VERSION 5.8 ;
BUSBITCHARS "[]" ;
DIVIDERCHAR "/" ;
UNITS
    DATABASE MICRONS 1000 ;
END UNITS

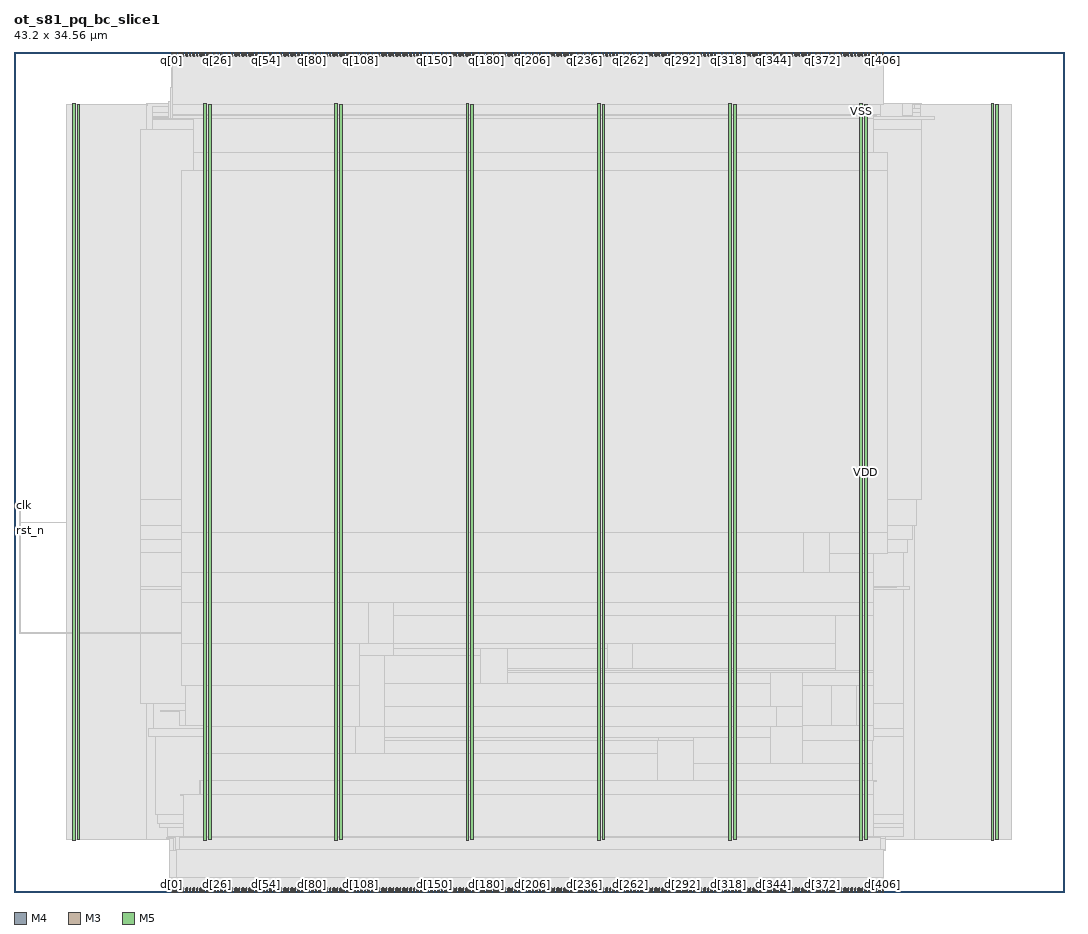
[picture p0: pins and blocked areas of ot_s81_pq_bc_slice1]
MACRO ot_s81_pq_bc_slice1
  FOREIGN ot_s81_pq_bc_slice1 0 0 ;
  CLASS BLOCK ;
  SIZE 43.2 BY 34.56 ;
  PIN clk
    DIRECTION INPUT ;
    USE SIGNAL ;
    PORT
      LAYER M4 ;
        RECT  0 15.888 0.192 15.912 ;
    END
    PORT
      LAYER M4 ;
        RECT  0.156 15.888 0.275 15.912 ;
    END
  END clk
  PIN d[0]
    DIRECTION INPUT ;
    USE SIGNAL ;
    PORT
      LAYER M3 ;
        RECT  6.48 0 6.498 0.144 ;
    END
  END d[0]
  PIN d[100]
    DIRECTION INPUT ;
    USE SIGNAL ;
    PORT
      LAYER M3 ;
        RECT  13.68 0 13.698 0.144 ;
    END
  END d[100]
  PIN d[101]
    DIRECTION INPUT ;
    USE SIGNAL ;
    PORT
      LAYER M5 ;
        RECT  13.728 0 13.752 0.192 ;
    END
  END d[101]
  PIN d[102]
    DIRECTION INPUT ;
    USE SIGNAL ;
    PORT
      LAYER M3 ;
        RECT  13.824 0 13.842 0.144 ;
    END
  END d[102]
  PIN d[103]
    DIRECTION INPUT ;
    USE SIGNAL ;
    PORT
      LAYER M5 ;
        RECT  13.872 0 13.896 0.192 ;
    END
  END d[103]
  PIN d[104]
    DIRECTION INPUT ;
    USE SIGNAL ;
    PORT
      LAYER M3 ;
        RECT  13.968 0 13.986 0.144 ;
    END
  END d[104]
  PIN d[105]
    DIRECTION INPUT ;
    USE SIGNAL ;
    PORT
      LAYER M5 ;
        RECT  14.016 0 14.04 0.192 ;
    END
  END d[105]
  PIN d[106]
    DIRECTION INPUT ;
    USE SIGNAL ;
    PORT
      LAYER M3 ;
        RECT  14.112 0 14.13 0.144 ;
    END
  END d[106]
  PIN d[107]
    DIRECTION INPUT ;
    USE SIGNAL ;
    PORT
      LAYER M5 ;
        RECT  14.16 0 14.184 0.192 ;
    END
  END d[107]
  PIN d[108]
    DIRECTION INPUT ;
    USE SIGNAL ;
    PORT
      LAYER M3 ;
        RECT  14.256 0 14.274 0.144 ;
    END
  END d[108]
  PIN d[109]
    DIRECTION INPUT ;
    USE SIGNAL ;
    PORT
      LAYER M5 ;
        RECT  14.304 0 14.328 0.192 ;
    END
  END d[109]
  PIN d[10]
    DIRECTION INPUT ;
    USE SIGNAL ;
    PORT
      LAYER M3 ;
        RECT  7.2 0 7.218 0.144 ;
    END
  END d[10]
  PIN d[110]
    DIRECTION INPUT ;
    USE SIGNAL ;
    PORT
      LAYER M3 ;
        RECT  14.4 0 14.418 0.144 ;
    END
  END d[110]
  PIN d[111]
    DIRECTION INPUT ;
    USE SIGNAL ;
    PORT
      LAYER M5 ;
        RECT  14.448 0 14.472 0.192 ;
    END
  END d[111]
  PIN d[112]
    DIRECTION INPUT ;
    USE SIGNAL ;
    PORT
      LAYER M3 ;
        RECT  14.544 0 14.562 0.144 ;
    END
  END d[112]
  PIN d[113]
    DIRECTION INPUT ;
    USE SIGNAL ;
    PORT
      LAYER M5 ;
        RECT  14.592 0 14.616 0.192 ;
    END
  END d[113]
  PIN d[114]
    DIRECTION INPUT ;
    USE SIGNAL ;
    PORT
      LAYER M3 ;
        RECT  14.688 0 14.706 0.144 ;
    END
  END d[114]
  PIN d[115]
    DIRECTION INPUT ;
    USE SIGNAL ;
    PORT
      LAYER M5 ;
        RECT  14.736 0 14.76 0.192 ;
    END
  END d[115]
  PIN d[116]
    DIRECTION INPUT ;
    USE SIGNAL ;
    PORT
      LAYER M3 ;
        RECT  14.832 0 14.85 0.144 ;
    END
  END d[116]
  PIN d[117]
    DIRECTION INPUT ;
    USE SIGNAL ;
    PORT
      LAYER M5 ;
        RECT  14.88 0 14.904 0.192 ;
    END
  END d[117]
  PIN d[118]
    DIRECTION INPUT ;
    USE SIGNAL ;
    PORT
      LAYER M3 ;
        RECT  14.976 0 14.994 0.144 ;
    END
  END d[118]
  PIN d[119]
    DIRECTION INPUT ;
    USE SIGNAL ;
    PORT
      LAYER M5 ;
        RECT  15.024 0 15.048 0.192 ;
    END
  END d[119]
  PIN d[11]
    DIRECTION INPUT ;
    USE SIGNAL ;
    PORT
      LAYER M5 ;
        RECT  7.248 0 7.272 0.192 ;
    END
  END d[11]
  PIN d[120]
    DIRECTION INPUT ;
    USE SIGNAL ;
    PORT
      LAYER M3 ;
        RECT  15.12 0 15.138 0.144 ;
    END
  END d[120]
  PIN d[121]
    DIRECTION INPUT ;
    USE SIGNAL ;
    PORT
      LAYER M5 ;
        RECT  15.168 0 15.192 0.192 ;
    END
  END d[121]
  PIN d[122]
    DIRECTION INPUT ;
    USE SIGNAL ;
    PORT
      LAYER M3 ;
        RECT  15.264 0 15.282 0.144 ;
    END
  END d[122]
  PIN d[123]
    DIRECTION INPUT ;
    USE SIGNAL ;
    PORT
      LAYER M5 ;
        RECT  15.312 0 15.336 0.192 ;
    END
  END d[123]
  PIN d[124]
    DIRECTION INPUT ;
    USE SIGNAL ;
    PORT
      LAYER M3 ;
        RECT  15.408 0 15.426 0.144 ;
    END
  END d[124]
  PIN d[125]
    DIRECTION INPUT ;
    USE SIGNAL ;
    PORT
      LAYER M5 ;
        RECT  15.456 0 15.48 0.192 ;
    END
  END d[125]
  PIN d[126]
    DIRECTION INPUT ;
    USE SIGNAL ;
    PORT
      LAYER M3 ;
        RECT  15.552 0 15.57 0.144 ;
    END
  END d[126]
  PIN d[127]
    DIRECTION INPUT ;
    USE SIGNAL ;
    PORT
      LAYER M5 ;
        RECT  15.6 0 15.624 0.192 ;
    END
  END d[127]
  PIN d[128]
    DIRECTION INPUT ;
    USE SIGNAL ;
    PORT
      LAYER M3 ;
        RECT  15.696 0 15.714 0.144 ;
    END
  END d[128]
  PIN d[129]
    DIRECTION INPUT ;
    USE SIGNAL ;
    PORT
      LAYER M5 ;
        RECT  15.744 0 15.768 0.192 ;
    END
  END d[129]
  PIN d[12]
    DIRECTION INPUT ;
    USE SIGNAL ;
    PORT
      LAYER M3 ;
        RECT  7.344 0 7.362 0.144 ;
    END
  END d[12]
  PIN d[130]
    DIRECTION INPUT ;
    USE SIGNAL ;
    PORT
      LAYER M3 ;
        RECT  15.84 0 15.858 0.144 ;
    END
  END d[130]
  PIN d[131]
    DIRECTION INPUT ;
    USE SIGNAL ;
    PORT
      LAYER M5 ;
        RECT  15.888 0 15.912 0.192 ;
    END
  END d[131]
  PIN d[132]
    DIRECTION INPUT ;
    USE SIGNAL ;
    PORT
      LAYER M3 ;
        RECT  15.984 0 16.002 0.144 ;
    END
  END d[132]
  PIN d[133]
    DIRECTION INPUT ;
    USE SIGNAL ;
    PORT
      LAYER M5 ;
        RECT  16.032 0 16.056 0.192 ;
    END
  END d[133]
  PIN d[134]
    DIRECTION INPUT ;
    USE SIGNAL ;
    PORT
      LAYER M3 ;
        RECT  16.128 0 16.146 0.144 ;
    END
  END d[134]
  PIN d[135]
    DIRECTION INPUT ;
    USE SIGNAL ;
    PORT
      LAYER M5 ;
        RECT  16.176 0 16.2 0.192 ;
    END
  END d[135]
  PIN d[136]
    DIRECTION INPUT ;
    USE SIGNAL ;
    PORT
      LAYER M3 ;
        RECT  16.272 0 16.29 0.144 ;
    END
  END d[136]
  PIN d[137]
    DIRECTION INPUT ;
    USE SIGNAL ;
    PORT
      LAYER M5 ;
        RECT  16.32 0 16.344 0.192 ;
    END
  END d[137]
  PIN d[138]
    DIRECTION INPUT ;
    USE SIGNAL ;
    PORT
      LAYER M3 ;
        RECT  16.416 0 16.434 0.144 ;
    END
  END d[138]
  PIN d[139]
    DIRECTION INPUT ;
    USE SIGNAL ;
    PORT
      LAYER M5 ;
        RECT  16.464 0 16.488 0.192 ;
    END
  END d[139]
  PIN d[13]
    DIRECTION INPUT ;
    USE SIGNAL ;
    PORT
      LAYER M5 ;
        RECT  7.392 0 7.416 0.192 ;
    END
  END d[13]
  PIN d[140]
    DIRECTION INPUT ;
    USE SIGNAL ;
    PORT
      LAYER M3 ;
        RECT  16.56 0 16.578 0.144 ;
    END
  END d[140]
  PIN d[141]
    DIRECTION INPUT ;
    USE SIGNAL ;
    PORT
      LAYER M5 ;
        RECT  16.608 0 16.632 0.192 ;
    END
  END d[141]
  PIN d[142]
    DIRECTION INPUT ;
    USE SIGNAL ;
    PORT
      LAYER M3 ;
        RECT  16.704 0 16.722 0.144 ;
    END
  END d[142]
  PIN d[143]
    DIRECTION INPUT ;
    USE SIGNAL ;
    PORT
      LAYER M5 ;
        RECT  16.752 0 16.776 0.192 ;
    END
  END d[143]
  PIN d[144]
    DIRECTION INPUT ;
    USE SIGNAL ;
    PORT
      LAYER M3 ;
        RECT  16.848 0 16.866 0.144 ;
    END
  END d[144]
  PIN d[145]
    DIRECTION INPUT ;
    USE SIGNAL ;
    PORT
      LAYER M5 ;
        RECT  16.896 0 16.92 0.192 ;
    END
  END d[145]
  PIN d[146]
    DIRECTION INPUT ;
    USE SIGNAL ;
    PORT
      LAYER M3 ;
        RECT  16.992 0 17.01 0.144 ;
    END
  END d[146]
  PIN d[147]
    DIRECTION INPUT ;
    USE SIGNAL ;
    PORT
      LAYER M5 ;
        RECT  17.04 0 17.064 0.192 ;
    END
  END d[147]
  PIN d[148]
    DIRECTION INPUT ;
    USE SIGNAL ;
    PORT
      LAYER M3 ;
        RECT  17.136 0 17.154 0.144 ;
    END
  END d[148]
  PIN d[149]
    DIRECTION INPUT ;
    USE SIGNAL ;
    PORT
      LAYER M5 ;
        RECT  17.184 0 17.208 0.192 ;
    END
  END d[149]
  PIN d[14]
    DIRECTION INPUT ;
    USE SIGNAL ;
    PORT
      LAYER M3 ;
        RECT  7.488 0 7.506 0.144 ;
    END
  END d[14]
  PIN d[150]
    DIRECTION INPUT ;
    USE SIGNAL ;
    PORT
      LAYER M3 ;
        RECT  17.28 0 17.298 0.144 ;
    END
  END d[150]
  PIN d[151]
    DIRECTION INPUT ;
    USE SIGNAL ;
    PORT
      LAYER M5 ;
        RECT  17.328 0 17.352 0.192 ;
    END
  END d[151]
  PIN d[152]
    DIRECTION INPUT ;
    USE SIGNAL ;
    PORT
      LAYER M3 ;
        RECT  17.424 0 17.442 0.144 ;
    END
  END d[152]
  PIN d[153]
    DIRECTION INPUT ;
    USE SIGNAL ;
    PORT
      LAYER M5 ;
        RECT  17.472 0 17.496 0.192 ;
    END
  END d[153]
  PIN d[154]
    DIRECTION INPUT ;
    USE SIGNAL ;
    PORT
      LAYER M3 ;
        RECT  17.568 0 17.586 0.144 ;
    END
  END d[154]
  PIN d[155]
    DIRECTION INPUT ;
    USE SIGNAL ;
    PORT
      LAYER M5 ;
        RECT  17.616 0 17.64 0.192 ;
    END
  END d[155]
  PIN d[156]
    DIRECTION INPUT ;
    USE SIGNAL ;
    PORT
      LAYER M3 ;
        RECT  17.712 0 17.73 0.144 ;
    END
  END d[156]
  PIN d[157]
    DIRECTION INPUT ;
    USE SIGNAL ;
    PORT
      LAYER M5 ;
        RECT  17.76 0 17.784 0.192 ;
    END
  END d[157]
  PIN d[158]
    DIRECTION INPUT ;
    USE SIGNAL ;
    PORT
      LAYER M3 ;
        RECT  17.856 0 17.874 0.144 ;
    END
  END d[158]
  PIN d[159]
    DIRECTION INPUT ;
    USE SIGNAL ;
    PORT
      LAYER M5 ;
        RECT  17.904 0 17.928 0.192 ;
    END
  END d[159]
  PIN d[15]
    DIRECTION INPUT ;
    USE SIGNAL ;
    PORT
      LAYER M5 ;
        RECT  7.536 0 7.56 0.192 ;
    END
  END d[15]
  PIN d[160]
    DIRECTION INPUT ;
    USE SIGNAL ;
    PORT
      LAYER M3 ;
        RECT  18 0 18.018 0.144 ;
    END
  END d[160]
  PIN d[161]
    DIRECTION INPUT ;
    USE SIGNAL ;
    PORT
      LAYER M5 ;
        RECT  18.048 0 18.072 0.192 ;
    END
  END d[161]
  PIN d[162]
    DIRECTION INPUT ;
    USE SIGNAL ;
    PORT
      LAYER M3 ;
        RECT  18.144 0 18.162 0.144 ;
    END
  END d[162]
  PIN d[163]
    DIRECTION INPUT ;
    USE SIGNAL ;
    PORT
      LAYER M5 ;
        RECT  18.192 0 18.216 0.192 ;
    END
  END d[163]
  PIN d[164]
    DIRECTION INPUT ;
    USE SIGNAL ;
    PORT
      LAYER M3 ;
        RECT  18.288 0 18.306 0.144 ;
    END
  END d[164]
  PIN d[165]
    DIRECTION INPUT ;
    USE SIGNAL ;
    PORT
      LAYER M5 ;
        RECT  18.336 0 18.36 0.192 ;
    END
  END d[165]
  PIN d[166]
    DIRECTION INPUT ;
    USE SIGNAL ;
    PORT
      LAYER M3 ;
        RECT  18.432 0 18.45 0.144 ;
    END
  END d[166]
  PIN d[167]
    DIRECTION INPUT ;
    USE SIGNAL ;
    PORT
      LAYER M5 ;
        RECT  18.48 0 18.504 0.192 ;
    END
  END d[167]
  PIN d[168]
    DIRECTION INPUT ;
    USE SIGNAL ;
    PORT
      LAYER M3 ;
        RECT  18.576 0 18.594 0.144 ;
    END
  END d[168]
  PIN d[169]
    DIRECTION INPUT ;
    USE SIGNAL ;
    PORT
      LAYER M5 ;
        RECT  18.624 0 18.648 0.192 ;
    END
  END d[169]
  PIN d[16]
    DIRECTION INPUT ;
    USE SIGNAL ;
    PORT
      LAYER M3 ;
        RECT  7.632 0 7.65 0.144 ;
    END
  END d[16]
  PIN d[170]
    DIRECTION INPUT ;
    USE SIGNAL ;
    PORT
      LAYER M3 ;
        RECT  18.72 0 18.738 0.144 ;
    END
  END d[170]
  PIN d[171]
    DIRECTION INPUT ;
    USE SIGNAL ;
    PORT
      LAYER M5 ;
        RECT  18.768 0 18.792 0.192 ;
    END
  END d[171]
  PIN d[172]
    DIRECTION INPUT ;
    USE SIGNAL ;
    PORT
      LAYER M3 ;
        RECT  18.864 0 18.882 0.144 ;
    END
  END d[172]
  PIN d[173]
    DIRECTION INPUT ;
    USE SIGNAL ;
    PORT
      LAYER M5 ;
        RECT  18.912 0 18.936 0.192 ;
    END
  END d[173]
  PIN d[174]
    DIRECTION INPUT ;
    USE SIGNAL ;
    PORT
      LAYER M3 ;
        RECT  19.008 0 19.026 0.144 ;
    END
  END d[174]
  PIN d[175]
    DIRECTION INPUT ;
    USE SIGNAL ;
    PORT
      LAYER M5 ;
        RECT  19.056 0 19.08 0.192 ;
    END
  END d[175]
  PIN d[176]
    DIRECTION INPUT ;
    USE SIGNAL ;
    PORT
      LAYER M3 ;
        RECT  19.152 0 19.17 0.144 ;
    END
  END d[176]
  PIN d[177]
    DIRECTION INPUT ;
    USE SIGNAL ;
    PORT
      LAYER M5 ;
        RECT  19.2 0 19.224 0.192 ;
    END
  END d[177]
  PIN d[178]
    DIRECTION INPUT ;
    USE SIGNAL ;
    PORT
      LAYER M3 ;
        RECT  19.296 0 19.314 0.144 ;
    END
  END d[178]
  PIN d[179]
    DIRECTION INPUT ;
    USE SIGNAL ;
    PORT
      LAYER M5 ;
        RECT  19.344 0 19.368 0.192 ;
    END
  END d[179]
  PIN d[17]
    DIRECTION INPUT ;
    USE SIGNAL ;
    PORT
      LAYER M5 ;
        RECT  7.68 0 7.704 0.192 ;
    END
  END d[17]
  PIN d[180]
    DIRECTION INPUT ;
    USE SIGNAL ;
    PORT
      LAYER M3 ;
        RECT  19.44 0 19.458 0.144 ;
    END
  END d[180]
  PIN d[181]
    DIRECTION INPUT ;
    USE SIGNAL ;
    PORT
      LAYER M5 ;
        RECT  19.488 0 19.512 0.192 ;
    END
  END d[181]
  PIN d[182]
    DIRECTION INPUT ;
    USE SIGNAL ;
    PORT
      LAYER M3 ;
        RECT  19.584 0 19.602 0.144 ;
    END
  END d[182]
  PIN d[183]
    DIRECTION INPUT ;
    USE SIGNAL ;
    PORT
      LAYER M5 ;
        RECT  19.632 0 19.656 0.192 ;
    END
  END d[183]
  PIN d[184]
    DIRECTION INPUT ;
    USE SIGNAL ;
    PORT
      LAYER M3 ;
        RECT  19.728 0 19.746 0.144 ;
    END
  END d[184]
  PIN d[185]
    DIRECTION INPUT ;
    USE SIGNAL ;
    PORT
      LAYER M5 ;
        RECT  19.776 0 19.8 0.192 ;
    END
  END d[185]
  PIN d[186]
    DIRECTION INPUT ;
    USE SIGNAL ;
    PORT
      LAYER M3 ;
        RECT  19.872 0 19.89 0.144 ;
    END
  END d[186]
  PIN d[187]
    DIRECTION INPUT ;
    USE SIGNAL ;
    PORT
      LAYER M5 ;
        RECT  19.92 0 19.944 0.192 ;
    END
  END d[187]
  PIN d[188]
    DIRECTION INPUT ;
    USE SIGNAL ;
    PORT
      LAYER M3 ;
        RECT  20.016 0 20.034 0.144 ;
    END
  END d[188]
  PIN d[189]
    DIRECTION INPUT ;
    USE SIGNAL ;
    PORT
      LAYER M5 ;
        RECT  20.064 0 20.088 0.192 ;
    END
  END d[189]
  PIN d[18]
    DIRECTION INPUT ;
    USE SIGNAL ;
    PORT
      LAYER M3 ;
        RECT  7.776 0 7.794 0.144 ;
    END
  END d[18]
  PIN d[190]
    DIRECTION INPUT ;
    USE SIGNAL ;
    PORT
      LAYER M3 ;
        RECT  20.16 0 20.178 0.144 ;
    END
  END d[190]
  PIN d[191]
    DIRECTION INPUT ;
    USE SIGNAL ;
    PORT
      LAYER M5 ;
        RECT  20.208 0 20.232 0.192 ;
    END
  END d[191]
  PIN d[192]
    DIRECTION INPUT ;
    USE SIGNAL ;
    PORT
      LAYER M3 ;
        RECT  20.304 0 20.322 0.144 ;
    END
  END d[192]
  PIN d[193]
    DIRECTION INPUT ;
    USE SIGNAL ;
    PORT
      LAYER M5 ;
        RECT  20.352 0 20.376 0.192 ;
    END
  END d[193]
  PIN d[194]
    DIRECTION INPUT ;
    USE SIGNAL ;
    PORT
      LAYER M3 ;
        RECT  20.448 0 20.466 0.144 ;
    END
  END d[194]
  PIN d[195]
    DIRECTION INPUT ;
    USE SIGNAL ;
    PORT
      LAYER M5 ;
        RECT  20.496 0 20.52 0.192 ;
    END
  END d[195]
  PIN d[196]
    DIRECTION INPUT ;
    USE SIGNAL ;
    PORT
      LAYER M3 ;
        RECT  20.592 0 20.61 0.144 ;
    END
  END d[196]
  PIN d[197]
    DIRECTION INPUT ;
    USE SIGNAL ;
    PORT
      LAYER M5 ;
        RECT  20.64 0 20.664 0.192 ;
    END
  END d[197]
  PIN d[198]
    DIRECTION INPUT ;
    USE SIGNAL ;
    PORT
      LAYER M3 ;
        RECT  20.736 0 20.754 0.144 ;
    END
  END d[198]
  PIN d[199]
    DIRECTION INPUT ;
    USE SIGNAL ;
    PORT
      LAYER M5 ;
        RECT  20.784 0 20.808 0.192 ;
    END
  END d[199]
  PIN d[19]
    DIRECTION INPUT ;
    USE SIGNAL ;
    PORT
      LAYER M5 ;
        RECT  7.824 0 7.848 0.192 ;
    END
  END d[19]
  PIN d[1]
    DIRECTION INPUT ;
    USE SIGNAL ;
    PORT
      LAYER M5 ;
        RECT  6.528 0 6.552 0.192 ;
    END
  END d[1]
  PIN d[200]
    DIRECTION INPUT ;
    USE SIGNAL ;
    PORT
      LAYER M3 ;
        RECT  20.88 0 20.898 0.144 ;
    END
  END d[200]
  PIN d[201]
    DIRECTION INPUT ;
    USE SIGNAL ;
    PORT
      LAYER M5 ;
        RECT  20.928 0 20.952 0.192 ;
    END
  END d[201]
  PIN d[202]
    DIRECTION INPUT ;
    USE SIGNAL ;
    PORT
      LAYER M3 ;
        RECT  21.024 0 21.042 0.144 ;
    END
  END d[202]
  PIN d[203]
    DIRECTION INPUT ;
    USE SIGNAL ;
    PORT
      LAYER M5 ;
        RECT  21.072 0 21.096 0.192 ;
    END
  END d[203]
  PIN d[204]
    DIRECTION INPUT ;
    USE SIGNAL ;
    PORT
      LAYER M3 ;
        RECT  21.168 0 21.186 0.144 ;
    END
  END d[204]
  PIN d[205]
    DIRECTION INPUT ;
    USE SIGNAL ;
    PORT
      LAYER M5 ;
        RECT  21.216 0 21.24 0.192 ;
    END
  END d[205]
  PIN d[206]
    DIRECTION INPUT ;
    USE SIGNAL ;
    PORT
      LAYER M3 ;
        RECT  21.312 0 21.33 0.144 ;
    END
  END d[206]
  PIN d[207]
    DIRECTION INPUT ;
    USE SIGNAL ;
    PORT
      LAYER M5 ;
        RECT  21.36 0 21.384 0.192 ;
    END
  END d[207]
  PIN d[208]
    DIRECTION INPUT ;
    USE SIGNAL ;
    PORT
      LAYER M3 ;
        RECT  21.456 0 21.474 0.144 ;
    END
  END d[208]
  PIN d[209]
    DIRECTION INPUT ;
    USE SIGNAL ;
    PORT
      LAYER M5 ;
        RECT  21.504 0 21.528 0.192 ;
    END
  END d[209]
  PIN d[20]
    DIRECTION INPUT ;
    USE SIGNAL ;
    PORT
      LAYER M3 ;
        RECT  7.92 0 7.938 0.144 ;
    END
  END d[20]
  PIN d[210]
    DIRECTION INPUT ;
    USE SIGNAL ;
    PORT
      LAYER M3 ;
        RECT  21.6 0 21.618 0.144 ;
    END
  END d[210]
  PIN d[211]
    DIRECTION INPUT ;
    USE SIGNAL ;
    PORT
      LAYER M5 ;
        RECT  21.648 0 21.672 0.192 ;
    END
  END d[211]
  PIN d[212]
    DIRECTION INPUT ;
    USE SIGNAL ;
    PORT
      LAYER M3 ;
        RECT  21.744 0 21.762 0.144 ;
    END
  END d[212]
  PIN d[213]
    DIRECTION INPUT ;
    USE SIGNAL ;
    PORT
      LAYER M5 ;
        RECT  21.792 0 21.816 0.192 ;
    END
  END d[213]
  PIN d[214]
    DIRECTION INPUT ;
    USE SIGNAL ;
    PORT
      LAYER M3 ;
        RECT  21.888 0 21.906 0.144 ;
    END
  END d[214]
  PIN d[215]
    DIRECTION INPUT ;
    USE SIGNAL ;
    PORT
      LAYER M5 ;
        RECT  21.936 0 21.96 0.192 ;
    END
  END d[215]
  PIN d[216]
    DIRECTION INPUT ;
    USE SIGNAL ;
    PORT
      LAYER M3 ;
        RECT  22.032 0 22.05 0.144 ;
    END
  END d[216]
  PIN d[217]
    DIRECTION INPUT ;
    USE SIGNAL ;
    PORT
      LAYER M5 ;
        RECT  22.08 0 22.104 0.192 ;
    END
  END d[217]
  PIN d[218]
    DIRECTION INPUT ;
    USE SIGNAL ;
    PORT
      LAYER M3 ;
        RECT  22.176 0 22.194 0.144 ;
    END
  END d[218]
  PIN d[219]
    DIRECTION INPUT ;
    USE SIGNAL ;
    PORT
      LAYER M5 ;
        RECT  22.224 0 22.248 0.192 ;
    END
  END d[219]
  PIN d[21]
    DIRECTION INPUT ;
    USE SIGNAL ;
    PORT
      LAYER M5 ;
        RECT  7.968 0 7.992 0.192 ;
    END
  END d[21]
  PIN d[220]
    DIRECTION INPUT ;
    USE SIGNAL ;
    PORT
      LAYER M3 ;
        RECT  22.32 0 22.338 0.144 ;
    END
  END d[220]
  PIN d[221]
    DIRECTION INPUT ;
    USE SIGNAL ;
    PORT
      LAYER M5 ;
        RECT  22.368 0 22.392 0.192 ;
    END
  END d[221]
  PIN d[222]
    DIRECTION INPUT ;
    USE SIGNAL ;
    PORT
      LAYER M3 ;
        RECT  22.464 0 22.482 0.144 ;
    END
  END d[222]
  PIN d[223]
    DIRECTION INPUT ;
    USE SIGNAL ;
    PORT
      LAYER M5 ;
        RECT  22.512 0 22.536 0.192 ;
    END
  END d[223]
  PIN d[224]
    DIRECTION INPUT ;
    USE SIGNAL ;
    PORT
      LAYER M3 ;
        RECT  22.608 0 22.626 0.144 ;
    END
  END d[224]
  PIN d[225]
    DIRECTION INPUT ;
    USE SIGNAL ;
    PORT
      LAYER M5 ;
        RECT  22.656 0 22.68 0.192 ;
    END
  END d[225]
  PIN d[226]
    DIRECTION INPUT ;
    USE SIGNAL ;
    PORT
      LAYER M3 ;
        RECT  22.752 0 22.77 0.144 ;
    END
  END d[226]
  PIN d[227]
    DIRECTION INPUT ;
    USE SIGNAL ;
    PORT
      LAYER M5 ;
        RECT  22.8 0 22.824 0.192 ;
    END
  END d[227]
  PIN d[228]
    DIRECTION INPUT ;
    USE SIGNAL ;
    PORT
      LAYER M3 ;
        RECT  22.896 0 22.914 0.144 ;
    END
  END d[228]
  PIN d[229]
    DIRECTION INPUT ;
    USE SIGNAL ;
    PORT
      LAYER M5 ;
        RECT  22.944 0 22.968 0.192 ;
    END
  END d[229]
  PIN d[22]
    DIRECTION INPUT ;
    USE SIGNAL ;
    PORT
      LAYER M3 ;
        RECT  8.064 0 8.082 0.144 ;
    END
  END d[22]
  PIN d[230]
    DIRECTION INPUT ;
    USE SIGNAL ;
    PORT
      LAYER M3 ;
        RECT  23.04 0 23.058 0.144 ;
    END
  END d[230]
  PIN d[231]
    DIRECTION INPUT ;
    USE SIGNAL ;
    PORT
      LAYER M5 ;
        RECT  23.088 0 23.112 0.192 ;
    END
  END d[231]
  PIN d[232]
    DIRECTION INPUT ;
    USE SIGNAL ;
    PORT
      LAYER M3 ;
        RECT  23.184 0 23.202 0.144 ;
    END
  END d[232]
  PIN d[233]
    DIRECTION INPUT ;
    USE SIGNAL ;
    PORT
      LAYER M5 ;
        RECT  23.232 0 23.256 0.192 ;
    END
  END d[233]
  PIN d[234]
    DIRECTION INPUT ;
    USE SIGNAL ;
    PORT
      LAYER M3 ;
        RECT  23.328 0 23.346 0.144 ;
    END
  END d[234]
  PIN d[235]
    DIRECTION INPUT ;
    USE SIGNAL ;
    PORT
      LAYER M5 ;
        RECT  23.376 0 23.4 0.192 ;
    END
  END d[235]
  PIN d[236]
    DIRECTION INPUT ;
    USE SIGNAL ;
    PORT
      LAYER M3 ;
        RECT  23.472 0 23.49 0.144 ;
    END
  END d[236]
  PIN d[237]
    DIRECTION INPUT ;
    USE SIGNAL ;
    PORT
      LAYER M5 ;
        RECT  23.52 0 23.544 0.192 ;
    END
  END d[237]
  PIN d[238]
    DIRECTION INPUT ;
    USE SIGNAL ;
    PORT
      LAYER M3 ;
        RECT  23.616 0 23.634 0.144 ;
    END
  END d[238]
  PIN d[239]
    DIRECTION INPUT ;
    USE SIGNAL ;
    PORT
      LAYER M5 ;
        RECT  23.664 0 23.688 0.192 ;
    END
  END d[239]
  PIN d[23]
    DIRECTION INPUT ;
    USE SIGNAL ;
    PORT
      LAYER M5 ;
        RECT  8.112 0 8.136 0.192 ;
    END
  END d[23]
  PIN d[240]
    DIRECTION INPUT ;
    USE SIGNAL ;
    PORT
      LAYER M3 ;
        RECT  23.76 0 23.778 0.144 ;
    END
  END d[240]
  PIN d[241]
    DIRECTION INPUT ;
    USE SIGNAL ;
    PORT
      LAYER M5 ;
        RECT  23.808 0 23.832 0.192 ;
    END
  END d[241]
  PIN d[242]
    DIRECTION INPUT ;
    USE SIGNAL ;
    PORT
      LAYER M3 ;
        RECT  23.904 0 23.922 0.144 ;
    END
  END d[242]
  PIN d[243]
    DIRECTION INPUT ;
    USE SIGNAL ;
    PORT
      LAYER M5 ;
        RECT  23.952 0 23.976 0.192 ;
    END
  END d[243]
  PIN d[244]
    DIRECTION INPUT ;
    USE SIGNAL ;
    PORT
      LAYER M3 ;
        RECT  24.048 0 24.066 0.144 ;
    END
  END d[244]
  PIN d[245]
    DIRECTION INPUT ;
    USE SIGNAL ;
    PORT
      LAYER M5 ;
        RECT  24.096 0 24.12 0.192 ;
    END
  END d[245]
  PIN d[246]
    DIRECTION INPUT ;
    USE SIGNAL ;
    PORT
      LAYER M3 ;
        RECT  24.192 0 24.21 0.144 ;
    END
  END d[246]
  PIN d[247]
    DIRECTION INPUT ;
    USE SIGNAL ;
    PORT
      LAYER M5 ;
        RECT  24.24 0 24.264 0.192 ;
    END
  END d[247]
  PIN d[248]
    DIRECTION INPUT ;
    USE SIGNAL ;
    PORT
      LAYER M3 ;
        RECT  24.336 0 24.354 0.144 ;
    END
  END d[248]
  PIN d[249]
    DIRECTION INPUT ;
    USE SIGNAL ;
    PORT
      LAYER M5 ;
        RECT  24.384 0 24.408 0.192 ;
    END
  END d[249]
  PIN d[24]
    DIRECTION INPUT ;
    USE SIGNAL ;
    PORT
      LAYER M3 ;
        RECT  8.208 0 8.226 0.144 ;
    END
  END d[24]
  PIN d[250]
    DIRECTION INPUT ;
    USE SIGNAL ;
    PORT
      LAYER M3 ;
        RECT  24.48 0 24.498 0.144 ;
    END
  END d[250]
  PIN d[251]
    DIRECTION INPUT ;
    USE SIGNAL ;
    PORT
      LAYER M5 ;
        RECT  24.528 0 24.552 0.192 ;
    END
  END d[251]
  PIN d[252]
    DIRECTION INPUT ;
    USE SIGNAL ;
    PORT
      LAYER M3 ;
        RECT  24.624 0 24.642 0.144 ;
    END
  END d[252]
  PIN d[253]
    DIRECTION INPUT ;
    USE SIGNAL ;
    PORT
      LAYER M5 ;
        RECT  24.672 0 24.696 0.192 ;
    END
  END d[253]
  PIN d[254]
    DIRECTION INPUT ;
    USE SIGNAL ;
    PORT
      LAYER M3 ;
        RECT  24.768 0 24.786 0.144 ;
    END
  END d[254]
  PIN d[255]
    DIRECTION INPUT ;
    USE SIGNAL ;
    PORT
      LAYER M5 ;
        RECT  24.816 0 24.84 0.192 ;
    END
  END d[255]
  PIN d[256]
    DIRECTION INPUT ;
    USE SIGNAL ;
    PORT
      LAYER M3 ;
        RECT  24.912 0 24.93 0.144 ;
    END
  END d[256]
  PIN d[257]
    DIRECTION INPUT ;
    USE SIGNAL ;
    PORT
      LAYER M5 ;
        RECT  24.96 0 24.984 0.192 ;
    END
  END d[257]
  PIN d[258]
    DIRECTION INPUT ;
    USE SIGNAL ;
    PORT
      LAYER M3 ;
        RECT  25.056 0 25.074 0.144 ;
    END
  END d[258]
  PIN d[259]
    DIRECTION INPUT ;
    USE SIGNAL ;
    PORT
      LAYER M5 ;
        RECT  25.104 0 25.128 0.192 ;
    END
  END d[259]
  PIN d[25]
    DIRECTION INPUT ;
    USE SIGNAL ;
    PORT
      LAYER M5 ;
        RECT  8.256 0 8.28 0.192 ;
    END
  END d[25]
  PIN d[260]
    DIRECTION INPUT ;
    USE SIGNAL ;
    PORT
      LAYER M3 ;
        RECT  25.2 0 25.218 0.144 ;
    END
  END d[260]
  PIN d[261]
    DIRECTION INPUT ;
    USE SIGNAL ;
    PORT
      LAYER M5 ;
        RECT  25.248 0 25.272 0.192 ;
    END
  END d[261]
  PIN d[262]
    DIRECTION INPUT ;
    USE SIGNAL ;
    PORT
      LAYER M3 ;
        RECT  25.344 0 25.362 0.144 ;
    END
  END d[262]
  PIN d[263]
    DIRECTION INPUT ;
    USE SIGNAL ;
    PORT
      LAYER M5 ;
        RECT  25.392 0 25.416 0.192 ;
    END
  END d[263]
  PIN d[264]
    DIRECTION INPUT ;
    USE SIGNAL ;
    PORT
      LAYER M3 ;
        RECT  25.488 0 25.506 0.144 ;
    END
  END d[264]
  PIN d[265]
    DIRECTION INPUT ;
    USE SIGNAL ;
    PORT
      LAYER M5 ;
        RECT  25.536 0 25.56 0.192 ;
    END
  END d[265]
  PIN d[266]
    DIRECTION INPUT ;
    USE SIGNAL ;
    PORT
      LAYER M3 ;
        RECT  25.632 0 25.65 0.144 ;
    END
  END d[266]
  PIN d[267]
    DIRECTION INPUT ;
    USE SIGNAL ;
    PORT
      LAYER M5 ;
        RECT  25.68 0 25.704 0.192 ;
    END
  END d[267]
  PIN d[268]
    DIRECTION INPUT ;
    USE SIGNAL ;
    PORT
      LAYER M3 ;
        RECT  25.776 0 25.794 0.144 ;
    END
  END d[268]
  PIN d[269]
    DIRECTION INPUT ;
    USE SIGNAL ;
    PORT
      LAYER M5 ;
        RECT  25.824 0 25.848 0.192 ;
    END
  END d[269]
  PIN d[26]
    DIRECTION INPUT ;
    USE SIGNAL ;
    PORT
      LAYER M3 ;
        RECT  8.352 0 8.37 0.144 ;
    END
  END d[26]
  PIN d[270]
    DIRECTION INPUT ;
    USE SIGNAL ;
    PORT
      LAYER M3 ;
        RECT  25.92 0 25.938 0.144 ;
    END
  END d[270]
  PIN d[271]
    DIRECTION INPUT ;
    USE SIGNAL ;
    PORT
      LAYER M5 ;
        RECT  25.968 0 25.992 0.192 ;
    END
  END d[271]
  PIN d[272]
    DIRECTION INPUT ;
    USE SIGNAL ;
    PORT
      LAYER M3 ;
        RECT  26.064 0 26.082 0.144 ;
    END
  END d[272]
  PIN d[273]
    DIRECTION INPUT ;
    USE SIGNAL ;
    PORT
      LAYER M5 ;
        RECT  26.112 0 26.136 0.192 ;
    END
  END d[273]
  PIN d[274]
    DIRECTION INPUT ;
    USE SIGNAL ;
    PORT
      LAYER M3 ;
        RECT  26.208 0 26.226 0.144 ;
    END
  END d[274]
  PIN d[275]
    DIRECTION INPUT ;
    USE SIGNAL ;
    PORT
      LAYER M5 ;
        RECT  26.256 0 26.28 0.192 ;
    END
  END d[275]
  PIN d[276]
    DIRECTION INPUT ;
    USE SIGNAL ;
    PORT
      LAYER M3 ;
        RECT  26.352 0 26.37 0.144 ;
    END
  END d[276]
  PIN d[277]
    DIRECTION INPUT ;
    USE SIGNAL ;
    PORT
      LAYER M5 ;
        RECT  26.4 0 26.424 0.192 ;
    END
  END d[277]
  PIN d[278]
    DIRECTION INPUT ;
    USE SIGNAL ;
    PORT
      LAYER M3 ;
        RECT  26.496 0 26.514 0.144 ;
    END
  END d[278]
  PIN d[279]
    DIRECTION INPUT ;
    USE SIGNAL ;
    PORT
      LAYER M5 ;
        RECT  26.544 0 26.568 0.192 ;
    END
  END d[279]
  PIN d[27]
    DIRECTION INPUT ;
    USE SIGNAL ;
    PORT
      LAYER M5 ;
        RECT  8.4 0 8.424 0.192 ;
    END
  END d[27]
  PIN d[280]
    DIRECTION INPUT ;
    USE SIGNAL ;
    PORT
      LAYER M3 ;
        RECT  26.64 0 26.658 0.144 ;
    END
  END d[280]
  PIN d[281]
    DIRECTION INPUT ;
    USE SIGNAL ;
    PORT
      LAYER M5 ;
        RECT  26.688 0 26.712 0.192 ;
    END
  END d[281]
  PIN d[282]
    DIRECTION INPUT ;
    USE SIGNAL ;
    PORT
      LAYER M3 ;
        RECT  26.784 0 26.802 0.144 ;
    END
  END d[282]
  PIN d[283]
    DIRECTION INPUT ;
    USE SIGNAL ;
    PORT
      LAYER M5 ;
        RECT  26.832 0 26.856 0.192 ;
    END
  END d[283]
  PIN d[284]
    DIRECTION INPUT ;
    USE SIGNAL ;
    PORT
      LAYER M3 ;
        RECT  26.928 0 26.946 0.144 ;
    END
  END d[284]
  PIN d[285]
    DIRECTION INPUT ;
    USE SIGNAL ;
    PORT
      LAYER M5 ;
        RECT  26.976 0 27 0.192 ;
    END
  END d[285]
  PIN d[286]
    DIRECTION INPUT ;
    USE SIGNAL ;
    PORT
      LAYER M3 ;
        RECT  27.072 0 27.09 0.144 ;
    END
  END d[286]
  PIN d[287]
    DIRECTION INPUT ;
    USE SIGNAL ;
    PORT
      LAYER M5 ;
        RECT  27.12 0 27.144 0.192 ;
    END
  END d[287]
  PIN d[288]
    DIRECTION INPUT ;
    USE SIGNAL ;
    PORT
      LAYER M3 ;
        RECT  27.216 0 27.234 0.144 ;
    END
  END d[288]
  PIN d[289]
    DIRECTION INPUT ;
    USE SIGNAL ;
    PORT
      LAYER M5 ;
        RECT  27.264 0 27.288 0.192 ;
    END
  END d[289]
  PIN d[28]
    DIRECTION INPUT ;
    USE SIGNAL ;
    PORT
      LAYER M3 ;
        RECT  8.496 0 8.514 0.144 ;
    END
  END d[28]
  PIN d[290]
    DIRECTION INPUT ;
    USE SIGNAL ;
    PORT
      LAYER M3 ;
        RECT  27.36 0 27.378 0.144 ;
    END
  END d[290]
  PIN d[291]
    DIRECTION INPUT ;
    USE SIGNAL ;
    PORT
      LAYER M5 ;
        RECT  27.408 0 27.432 0.192 ;
    END
  END d[291]
  PIN d[292]
    DIRECTION INPUT ;
    USE SIGNAL ;
    PORT
      LAYER M3 ;
        RECT  27.504 0 27.522 0.144 ;
    END
  END d[292]
  PIN d[293]
    DIRECTION INPUT ;
    USE SIGNAL ;
    PORT
      LAYER M5 ;
        RECT  27.552 0 27.576 0.192 ;
    END
  END d[293]
  PIN d[294]
    DIRECTION INPUT ;
    USE SIGNAL ;
    PORT
      LAYER M3 ;
        RECT  27.648 0 27.666 0.144 ;
    END
  END d[294]
  PIN d[295]
    DIRECTION INPUT ;
    USE SIGNAL ;
    PORT
      LAYER M5 ;
        RECT  27.696 0 27.72 0.192 ;
    END
  END d[295]
  PIN d[296]
    DIRECTION INPUT ;
    USE SIGNAL ;
    PORT
      LAYER M3 ;
        RECT  27.792 0 27.81 0.144 ;
    END
  END d[296]
  PIN d[297]
    DIRECTION INPUT ;
    USE SIGNAL ;
    PORT
      LAYER M5 ;
        RECT  27.84 0 27.864 0.192 ;
    END
  END d[297]
  PIN d[298]
    DIRECTION INPUT ;
    USE SIGNAL ;
    PORT
      LAYER M3 ;
        RECT  27.936 0 27.954 0.144 ;
    END
  END d[298]
  PIN d[299]
    DIRECTION INPUT ;
    USE SIGNAL ;
    PORT
      LAYER M5 ;
        RECT  27.984 0 28.008 0.192 ;
    END
  END d[299]
  PIN d[29]
    DIRECTION INPUT ;
    USE SIGNAL ;
    PORT
      LAYER M5 ;
        RECT  8.544 0 8.568 0.192 ;
    END
  END d[29]
  PIN d[2]
    DIRECTION INPUT ;
    USE SIGNAL ;
    PORT
      LAYER M3 ;
        RECT  6.624 0 6.642 0.144 ;
    END
  END d[2]
  PIN d[300]
    DIRECTION INPUT ;
    USE SIGNAL ;
    PORT
      LAYER M3 ;
        RECT  28.08 0 28.098 0.144 ;
    END
  END d[300]
  PIN d[301]
    DIRECTION INPUT ;
    USE SIGNAL ;
    PORT
      LAYER M5 ;
        RECT  28.128 0 28.152 0.192 ;
    END
  END d[301]
  PIN d[302]
    DIRECTION INPUT ;
    USE SIGNAL ;
    PORT
      LAYER M3 ;
        RECT  28.224 0 28.242 0.144 ;
    END
  END d[302]
  PIN d[303]
    DIRECTION INPUT ;
    USE SIGNAL ;
    PORT
      LAYER M5 ;
        RECT  28.272 0 28.296 0.192 ;
    END
  END d[303]
  PIN d[304]
    DIRECTION INPUT ;
    USE SIGNAL ;
    PORT
      LAYER M3 ;
        RECT  28.368 0 28.386 0.144 ;
    END
  END d[304]
  PIN d[305]
    DIRECTION INPUT ;
    USE SIGNAL ;
    PORT
      LAYER M5 ;
        RECT  28.416 0 28.44 0.192 ;
    END
  END d[305]
  PIN d[306]
    DIRECTION INPUT ;
    USE SIGNAL ;
    PORT
      LAYER M3 ;
        RECT  28.512 0 28.53 0.144 ;
    END
  END d[306]
  PIN d[307]
    DIRECTION INPUT ;
    USE SIGNAL ;
    PORT
      LAYER M5 ;
        RECT  28.56 0 28.584 0.192 ;
    END
  END d[307]
  PIN d[308]
    DIRECTION INPUT ;
    USE SIGNAL ;
    PORT
      LAYER M3 ;
        RECT  28.656 0 28.674 0.144 ;
    END
  END d[308]
  PIN d[309]
    DIRECTION INPUT ;
    USE SIGNAL ;
    PORT
      LAYER M5 ;
        RECT  28.704 0 28.728 0.192 ;
    END
  END d[309]
  PIN d[30]
    DIRECTION INPUT ;
    USE SIGNAL ;
    PORT
      LAYER M3 ;
        RECT  8.64 0 8.658 0.144 ;
    END
  END d[30]
  PIN d[310]
    DIRECTION INPUT ;
    USE SIGNAL ;
    PORT
      LAYER M3 ;
        RECT  28.8 0 28.818 0.144 ;
    END
  END d[310]
  PIN d[311]
    DIRECTION INPUT ;
    USE SIGNAL ;
    PORT
      LAYER M5 ;
        RECT  28.848 0 28.872 0.192 ;
    END
  END d[311]
  PIN d[312]
    DIRECTION INPUT ;
    USE SIGNAL ;
    PORT
      LAYER M3 ;
        RECT  28.944 0 28.962 0.144 ;
    END
  END d[312]
  PIN d[313]
    DIRECTION INPUT ;
    USE SIGNAL ;
    PORT
      LAYER M5 ;
        RECT  28.992 0 29.016 0.192 ;
    END
  END d[313]
  PIN d[314]
    DIRECTION INPUT ;
    USE SIGNAL ;
    PORT
      LAYER M3 ;
        RECT  29.088 0 29.106 0.144 ;
    END
  END d[314]
  PIN d[315]
    DIRECTION INPUT ;
    USE SIGNAL ;
    PORT
      LAYER M5 ;
        RECT  29.136 0 29.16 0.192 ;
    END
  END d[315]
  PIN d[316]
    DIRECTION INPUT ;
    USE SIGNAL ;
    PORT
      LAYER M3 ;
        RECT  29.232 0 29.25 0.144 ;
    END
  END d[316]
  PIN d[317]
    DIRECTION INPUT ;
    USE SIGNAL ;
    PORT
      LAYER M5 ;
        RECT  29.28 0 29.304 0.192 ;
    END
  END d[317]
  PIN d[318]
    DIRECTION INPUT ;
    USE SIGNAL ;
    PORT
      LAYER M3 ;
        RECT  29.376 0 29.394 0.144 ;
    END
  END d[318]
  PIN d[319]
    DIRECTION INPUT ;
    USE SIGNAL ;
    PORT
      LAYER M5 ;
        RECT  29.424 0 29.448 0.192 ;
    END
  END d[319]
  PIN d[31]
    DIRECTION INPUT ;
    USE SIGNAL ;
    PORT
      LAYER M5 ;
        RECT  8.688 0 8.712 0.192 ;
    END
  END d[31]
  PIN d[320]
    DIRECTION INPUT ;
    USE SIGNAL ;
    PORT
      LAYER M3 ;
        RECT  29.52 0 29.538 0.144 ;
    END
  END d[320]
  PIN d[321]
    DIRECTION INPUT ;
    USE SIGNAL ;
    PORT
      LAYER M5 ;
        RECT  29.568 0 29.592 0.192 ;
    END
  END d[321]
  PIN d[322]
    DIRECTION INPUT ;
    USE SIGNAL ;
    PORT
      LAYER M3 ;
        RECT  29.664 0 29.682 0.144 ;
    END
  END d[322]
  PIN d[323]
    DIRECTION INPUT ;
    USE SIGNAL ;
    PORT
      LAYER M5 ;
        RECT  29.712 0 29.736 0.192 ;
    END
  END d[323]
  PIN d[324]
    DIRECTION INPUT ;
    USE SIGNAL ;
    PORT
      LAYER M3 ;
        RECT  29.808 0 29.826 0.144 ;
    END
  END d[324]
  PIN d[325]
    DIRECTION INPUT ;
    USE SIGNAL ;
    PORT
      LAYER M5 ;
        RECT  29.856 0 29.88 0.192 ;
    END
  END d[325]
  PIN d[326]
    DIRECTION INPUT ;
    USE SIGNAL ;
    PORT
      LAYER M3 ;
        RECT  29.952 0 29.97 0.144 ;
    END
  END d[326]
  PIN d[327]
    DIRECTION INPUT ;
    USE SIGNAL ;
    PORT
      LAYER M5 ;
        RECT  30 0 30.024 0.192 ;
    END
  END d[327]
  PIN d[328]
    DIRECTION INPUT ;
    USE SIGNAL ;
    PORT
      LAYER M3 ;
        RECT  30.096 0 30.114 0.144 ;
    END
  END d[328]
  PIN d[329]
    DIRECTION INPUT ;
    USE SIGNAL ;
    PORT
      LAYER M5 ;
        RECT  30.144 0 30.168 0.192 ;
    END
  END d[329]
  PIN d[32]
    DIRECTION INPUT ;
    USE SIGNAL ;
    PORT
      LAYER M3 ;
        RECT  8.784 0 8.802 0.144 ;
    END
  END d[32]
  PIN d[330]
    DIRECTION INPUT ;
    USE SIGNAL ;
    PORT
      LAYER M3 ;
        RECT  30.24 0 30.258 0.144 ;
    END
  END d[330]
  PIN d[331]
    DIRECTION INPUT ;
    USE SIGNAL ;
    PORT
      LAYER M5 ;
        RECT  30.288 0 30.312 0.192 ;
    END
  END d[331]
  PIN d[332]
    DIRECTION INPUT ;
    USE SIGNAL ;
    PORT
      LAYER M3 ;
        RECT  30.384 0 30.402 0.144 ;
    END
  END d[332]
  PIN d[333]
    DIRECTION INPUT ;
    USE SIGNAL ;
    PORT
      LAYER M5 ;
        RECT  30.432 0 30.456 0.192 ;
    END
  END d[333]
  PIN d[334]
    DIRECTION INPUT ;
    USE SIGNAL ;
    PORT
      LAYER M3 ;
        RECT  30.528 0 30.546 0.144 ;
    END
  END d[334]
  PIN d[335]
    DIRECTION INPUT ;
    USE SIGNAL ;
    PORT
      LAYER M5 ;
        RECT  30.576 0 30.6 0.192 ;
    END
  END d[335]
  PIN d[336]
    DIRECTION INPUT ;
    USE SIGNAL ;
    PORT
      LAYER M3 ;
        RECT  30.672 0 30.69 0.144 ;
    END
  END d[336]
  PIN d[337]
    DIRECTION INPUT ;
    USE SIGNAL ;
    PORT
      LAYER M5 ;
        RECT  30.72 0 30.744 0.192 ;
    END
  END d[337]
  PIN d[338]
    DIRECTION INPUT ;
    USE SIGNAL ;
    PORT
      LAYER M3 ;
        RECT  30.816 0 30.834 0.144 ;
    END
  END d[338]
  PIN d[339]
    DIRECTION INPUT ;
    USE SIGNAL ;
    PORT
      LAYER M5 ;
        RECT  30.864 0 30.888 0.192 ;
    END
  END d[339]
  PIN d[33]
    DIRECTION INPUT ;
    USE SIGNAL ;
    PORT
      LAYER M5 ;
        RECT  8.832 0 8.856 0.192 ;
    END
  END d[33]
  PIN d[340]
    DIRECTION INPUT ;
    USE SIGNAL ;
    PORT
      LAYER M3 ;
        RECT  30.96 0 30.978 0.144 ;
    END
  END d[340]
  PIN d[341]
    DIRECTION INPUT ;
    USE SIGNAL ;
    PORT
      LAYER M5 ;
        RECT  31.008 0 31.032 0.192 ;
    END
  END d[341]
  PIN d[342]
    DIRECTION INPUT ;
    USE SIGNAL ;
    PORT
      LAYER M3 ;
        RECT  31.104 0 31.122 0.144 ;
    END
  END d[342]
  PIN d[343]
    DIRECTION INPUT ;
    USE SIGNAL ;
    PORT
      LAYER M5 ;
        RECT  31.152 0 31.176 0.192 ;
    END
  END d[343]
  PIN d[344]
    DIRECTION INPUT ;
    USE SIGNAL ;
    PORT
      LAYER M3 ;
        RECT  31.248 0 31.266 0.144 ;
    END
  END d[344]
  PIN d[345]
    DIRECTION INPUT ;
    USE SIGNAL ;
    PORT
      LAYER M5 ;
        RECT  31.296 0 31.32 0.192 ;
    END
  END d[345]
  PIN d[346]
    DIRECTION INPUT ;
    USE SIGNAL ;
    PORT
      LAYER M3 ;
        RECT  31.392 0 31.41 0.144 ;
    END
  END d[346]
  PIN d[347]
    DIRECTION INPUT ;
    USE SIGNAL ;
    PORT
      LAYER M5 ;
        RECT  31.44 0 31.464 0.192 ;
    END
  END d[347]
  PIN d[348]
    DIRECTION INPUT ;
    USE SIGNAL ;
    PORT
      LAYER M3 ;
        RECT  31.536 0 31.554 0.144 ;
    END
  END d[348]
  PIN d[349]
    DIRECTION INPUT ;
    USE SIGNAL ;
    PORT
      LAYER M5 ;
        RECT  31.584 0 31.608 0.192 ;
    END
  END d[349]
  PIN d[34]
    DIRECTION INPUT ;
    USE SIGNAL ;
    PORT
      LAYER M3 ;
        RECT  8.928 0 8.946 0.144 ;
    END
  END d[34]
  PIN d[350]
    DIRECTION INPUT ;
    USE SIGNAL ;
    PORT
      LAYER M3 ;
        RECT  31.68 0 31.698 0.144 ;
    END
  END d[350]
  PIN d[351]
    DIRECTION INPUT ;
    USE SIGNAL ;
    PORT
      LAYER M5 ;
        RECT  31.728 0 31.752 0.192 ;
    END
  END d[351]
  PIN d[352]
    DIRECTION INPUT ;
    USE SIGNAL ;
    PORT
      LAYER M3 ;
        RECT  31.824 0 31.842 0.144 ;
    END
  END d[352]
  PIN d[353]
    DIRECTION INPUT ;
    USE SIGNAL ;
    PORT
      LAYER M5 ;
        RECT  31.872 0 31.896 0.192 ;
    END
  END d[353]
  PIN d[354]
    DIRECTION INPUT ;
    USE SIGNAL ;
    PORT
      LAYER M3 ;
        RECT  31.968 0 31.986 0.144 ;
    END
  END d[354]
  PIN d[355]
    DIRECTION INPUT ;
    USE SIGNAL ;
    PORT
      LAYER M5 ;
        RECT  32.016 0 32.04 0.192 ;
    END
  END d[355]
  PIN d[356]
    DIRECTION INPUT ;
    USE SIGNAL ;
    PORT
      LAYER M3 ;
        RECT  32.112 0 32.13 0.144 ;
    END
  END d[356]
  PIN d[357]
    DIRECTION INPUT ;
    USE SIGNAL ;
    PORT
      LAYER M5 ;
        RECT  32.16 0 32.184 0.192 ;
    END
  END d[357]
  PIN d[358]
    DIRECTION INPUT ;
    USE SIGNAL ;
    PORT
      LAYER M3 ;
        RECT  32.256 0 32.274 0.144 ;
    END
  END d[358]
  PIN d[359]
    DIRECTION INPUT ;
    USE SIGNAL ;
    PORT
      LAYER M5 ;
        RECT  32.304 0 32.328 0.192 ;
    END
  END d[359]
  PIN d[35]
    DIRECTION INPUT ;
    USE SIGNAL ;
    PORT
      LAYER M5 ;
        RECT  8.976 0 9 0.192 ;
    END
  END d[35]
  PIN d[360]
    DIRECTION INPUT ;
    USE SIGNAL ;
    PORT
      LAYER M3 ;
        RECT  32.4 0 32.418 0.144 ;
    END
  END d[360]
  PIN d[361]
    DIRECTION INPUT ;
    USE SIGNAL ;
    PORT
      LAYER M5 ;
        RECT  32.448 0 32.472 0.192 ;
    END
  END d[361]
  PIN d[362]
    DIRECTION INPUT ;
    USE SIGNAL ;
    PORT
      LAYER M3 ;
        RECT  32.544 0 32.562 0.144 ;
    END
  END d[362]
  PIN d[363]
    DIRECTION INPUT ;
    USE SIGNAL ;
    PORT
      LAYER M5 ;
        RECT  32.592 0 32.616 0.192 ;
    END
  END d[363]
  PIN d[364]
    DIRECTION INPUT ;
    USE SIGNAL ;
    PORT
      LAYER M3 ;
        RECT  32.688 0 32.706 0.144 ;
    END
  END d[364]
  PIN d[365]
    DIRECTION INPUT ;
    USE SIGNAL ;
    PORT
      LAYER M5 ;
        RECT  32.736 0 32.76 0.192 ;
    END
  END d[365]
  PIN d[366]
    DIRECTION INPUT ;
    USE SIGNAL ;
    PORT
      LAYER M3 ;
        RECT  32.832 0 32.85 0.144 ;
    END
  END d[366]
  PIN d[367]
    DIRECTION INPUT ;
    USE SIGNAL ;
    PORT
      LAYER M5 ;
        RECT  32.88 0 32.904 0.192 ;
    END
  END d[367]
  PIN d[368]
    DIRECTION INPUT ;
    USE SIGNAL ;
    PORT
      LAYER M3 ;
        RECT  32.976 0 32.994 0.144 ;
    END
  END d[368]
  PIN d[369]
    DIRECTION INPUT ;
    USE SIGNAL ;
    PORT
      LAYER M5 ;
        RECT  33.024 0 33.048 0.192 ;
    END
  END d[369]
  PIN d[36]
    DIRECTION INPUT ;
    USE SIGNAL ;
    PORT
      LAYER M3 ;
        RECT  9.072 0 9.09 0.144 ;
    END
  END d[36]
  PIN d[370]
    DIRECTION INPUT ;
    USE SIGNAL ;
    PORT
      LAYER M3 ;
        RECT  33.12 0 33.138 0.144 ;
    END
  END d[370]
  PIN d[371]
    DIRECTION INPUT ;
    USE SIGNAL ;
    PORT
      LAYER M5 ;
        RECT  33.168 0 33.192 0.192 ;
    END
  END d[371]
  PIN d[372]
    DIRECTION INPUT ;
    USE SIGNAL ;
    PORT
      LAYER M3 ;
        RECT  33.264 0 33.282 0.144 ;
    END
  END d[372]
  PIN d[373]
    DIRECTION INPUT ;
    USE SIGNAL ;
    PORT
      LAYER M5 ;
        RECT  33.312 0 33.336 0.192 ;
    END
  END d[373]
  PIN d[374]
    DIRECTION INPUT ;
    USE SIGNAL ;
    PORT
      LAYER M3 ;
        RECT  33.408 0 33.426 0.144 ;
    END
  END d[374]
  PIN d[375]
    DIRECTION INPUT ;
    USE SIGNAL ;
    PORT
      LAYER M5 ;
        RECT  33.456 0 33.48 0.192 ;
    END
  END d[375]
  PIN d[376]
    DIRECTION INPUT ;
    USE SIGNAL ;
    PORT
      LAYER M3 ;
        RECT  33.552 0 33.57 0.144 ;
    END
  END d[376]
  PIN d[377]
    DIRECTION INPUT ;
    USE SIGNAL ;
    PORT
      LAYER M5 ;
        RECT  33.6 0 33.624 0.192 ;
    END
  END d[377]
  PIN d[378]
    DIRECTION INPUT ;
    USE SIGNAL ;
    PORT
      LAYER M3 ;
        RECT  33.696 0 33.714 0.144 ;
    END
  END d[378]
  PIN d[379]
    DIRECTION INPUT ;
    USE SIGNAL ;
    PORT
      LAYER M5 ;
        RECT  33.744 0 33.768 0.192 ;
    END
  END d[379]
  PIN d[37]
    DIRECTION INPUT ;
    USE SIGNAL ;
    PORT
      LAYER M5 ;
        RECT  9.12 0 9.144 0.192 ;
    END
  END d[37]
  PIN d[380]
    DIRECTION INPUT ;
    USE SIGNAL ;
    PORT
      LAYER M3 ;
        RECT  33.84 0 33.858 0.144 ;
    END
  END d[380]
  PIN d[381]
    DIRECTION INPUT ;
    USE SIGNAL ;
    PORT
      LAYER M5 ;
        RECT  33.888 0 33.912 0.192 ;
    END
  END d[381]
  PIN d[382]
    DIRECTION INPUT ;
    USE SIGNAL ;
    PORT
      LAYER M3 ;
        RECT  33.984 0 34.002 0.144 ;
    END
  END d[382]
  PIN d[383]
    DIRECTION INPUT ;
    USE SIGNAL ;
    PORT
      LAYER M5 ;
        RECT  34.032 0 34.056 0.192 ;
    END
  END d[383]
  PIN d[384]
    DIRECTION INPUT ;
    USE SIGNAL ;
    PORT
      LAYER M3 ;
        RECT  34.128 0 34.146 0.144 ;
    END
  END d[384]
  PIN d[385]
    DIRECTION INPUT ;
    USE SIGNAL ;
    PORT
      LAYER M5 ;
        RECT  34.176 0 34.2 0.192 ;
    END
  END d[385]
  PIN d[386]
    DIRECTION INPUT ;
    USE SIGNAL ;
    PORT
      LAYER M3 ;
        RECT  34.272 0 34.29 0.144 ;
    END
  END d[386]
  PIN d[387]
    DIRECTION INPUT ;
    USE SIGNAL ;
    PORT
      LAYER M5 ;
        RECT  34.32 0 34.344 0.192 ;
    END
  END d[387]
  PIN d[388]
    DIRECTION INPUT ;
    USE SIGNAL ;
    PORT
      LAYER M3 ;
        RECT  34.416 0 34.434 0.144 ;
    END
  END d[388]
  PIN d[389]
    DIRECTION INPUT ;
    USE SIGNAL ;
    PORT
      LAYER M5 ;
        RECT  34.464 0 34.488 0.192 ;
    END
  END d[389]
  PIN d[38]
    DIRECTION INPUT ;
    USE SIGNAL ;
    PORT
      LAYER M3 ;
        RECT  9.216 0 9.234 0.144 ;
    END
  END d[38]
  PIN d[390]
    DIRECTION INPUT ;
    USE SIGNAL ;
    PORT
      LAYER M3 ;
        RECT  34.56 0 34.578 0.144 ;
    END
  END d[390]
  PIN d[391]
    DIRECTION INPUT ;
    USE SIGNAL ;
    PORT
      LAYER M5 ;
        RECT  34.608 0 34.632 0.192 ;
    END
  END d[391]
  PIN d[392]
    DIRECTION INPUT ;
    USE SIGNAL ;
    PORT
      LAYER M3 ;
        RECT  34.704 0 34.722 0.144 ;
    END
  END d[392]
  PIN d[393]
    DIRECTION INPUT ;
    USE SIGNAL ;
    PORT
      LAYER M5 ;
        RECT  34.752 0 34.776 0.192 ;
    END
  END d[393]
  PIN d[394]
    DIRECTION INPUT ;
    USE SIGNAL ;
    PORT
      LAYER M3 ;
        RECT  34.848 0 34.866 0.144 ;
    END
  END d[394]
  PIN d[395]
    DIRECTION INPUT ;
    USE SIGNAL ;
    PORT
      LAYER M5 ;
        RECT  34.896 0 34.92 0.192 ;
    END
  END d[395]
  PIN d[396]
    DIRECTION INPUT ;
    USE SIGNAL ;
    PORT
      LAYER M3 ;
        RECT  34.992 0 35.01 0.144 ;
    END
  END d[396]
  PIN d[397]
    DIRECTION INPUT ;
    USE SIGNAL ;
    PORT
      LAYER M5 ;
        RECT  35.04 0 35.064 0.192 ;
    END
  END d[397]
  PIN d[398]
    DIRECTION INPUT ;
    USE SIGNAL ;
    PORT
      LAYER M3 ;
        RECT  35.136 0 35.154 0.144 ;
    END
  END d[398]
  PIN d[399]
    DIRECTION INPUT ;
    USE SIGNAL ;
    PORT
      LAYER M5 ;
        RECT  35.184 0 35.208 0.192 ;
    END
  END d[399]
  PIN d[39]
    DIRECTION INPUT ;
    USE SIGNAL ;
    PORT
      LAYER M5 ;
        RECT  9.264 0 9.288 0.192 ;
    END
  END d[39]
  PIN d[3]
    DIRECTION INPUT ;
    USE SIGNAL ;
    PORT
      LAYER M5 ;
        RECT  6.672 0 6.696 0.192 ;
    END
  END d[3]
  PIN d[400]
    DIRECTION INPUT ;
    USE SIGNAL ;
    PORT
      LAYER M3 ;
        RECT  35.28 0 35.298 0.144 ;
    END
  END d[400]
  PIN d[401]
    DIRECTION INPUT ;
    USE SIGNAL ;
    PORT
      LAYER M5 ;
        RECT  35.328 0 35.352 0.192 ;
    END
  END d[401]
  PIN d[402]
    DIRECTION INPUT ;
    USE SIGNAL ;
    PORT
      LAYER M3 ;
        RECT  35.424 0 35.442 0.144 ;
    END
  END d[402]
  PIN d[403]
    DIRECTION INPUT ;
    USE SIGNAL ;
    PORT
      LAYER M5 ;
        RECT  35.472 0 35.496 0.192 ;
    END
  END d[403]
  PIN d[404]
    DIRECTION INPUT ;
    USE SIGNAL ;
    PORT
      LAYER M3 ;
        RECT  35.568 0 35.586 0.144 ;
    END
  END d[404]
  PIN d[405]
    DIRECTION INPUT ;
    USE SIGNAL ;
    PORT
      LAYER M5 ;
        RECT  35.616 0 35.64 0.192 ;
    END
  END d[405]
  PIN d[406]
    DIRECTION INPUT ;
    USE SIGNAL ;
    PORT
      LAYER M3 ;
        RECT  35.712 0 35.73 0.144 ;
    END
  END d[406]
  PIN d[407]
    DIRECTION INPUT ;
    USE SIGNAL ;
    PORT
      LAYER M5 ;
        RECT  35.76 0 35.784 0.192 ;
    END
  END d[407]
  PIN d[40]
    DIRECTION INPUT ;
    USE SIGNAL ;
    PORT
      LAYER M3 ;
        RECT  9.36 0 9.378 0.144 ;
    END
  END d[40]
  PIN d[41]
    DIRECTION INPUT ;
    USE SIGNAL ;
    PORT
      LAYER M5 ;
        RECT  9.408 0 9.432 0.192 ;
    END
  END d[41]
  PIN d[42]
    DIRECTION INPUT ;
    USE SIGNAL ;
    PORT
      LAYER M3 ;
        RECT  9.504 0 9.522 0.144 ;
    END
  END d[42]
  PIN d[43]
    DIRECTION INPUT ;
    USE SIGNAL ;
    PORT
      LAYER M5 ;
        RECT  9.552 0 9.576 0.192 ;
    END
  END d[43]
  PIN d[44]
    DIRECTION INPUT ;
    USE SIGNAL ;
    PORT
      LAYER M3 ;
        RECT  9.648 0 9.666 0.144 ;
    END
  END d[44]
  PIN d[45]
    DIRECTION INPUT ;
    USE SIGNAL ;
    PORT
      LAYER M5 ;
        RECT  9.696 0 9.72 0.192 ;
    END
  END d[45]
  PIN d[46]
    DIRECTION INPUT ;
    USE SIGNAL ;
    PORT
      LAYER M3 ;
        RECT  9.792 0 9.81 0.144 ;
    END
  END d[46]
  PIN d[47]
    DIRECTION INPUT ;
    USE SIGNAL ;
    PORT
      LAYER M5 ;
        RECT  9.84 0 9.864 0.192 ;
    END
  END d[47]
  PIN d[48]
    DIRECTION INPUT ;
    USE SIGNAL ;
    PORT
      LAYER M3 ;
        RECT  9.936 0 9.954 0.144 ;
    END
  END d[48]
  PIN d[49]
    DIRECTION INPUT ;
    USE SIGNAL ;
    PORT
      LAYER M5 ;
        RECT  9.984 0 10.008 0.192 ;
    END
  END d[49]
  PIN d[4]
    DIRECTION INPUT ;
    USE SIGNAL ;
    PORT
      LAYER M3 ;
        RECT  6.768 0 6.786 0.144 ;
    END
  END d[4]
  PIN d[50]
    DIRECTION INPUT ;
    USE SIGNAL ;
    PORT
      LAYER M3 ;
        RECT  10.08 0 10.098 0.144 ;
    END
  END d[50]
  PIN d[51]
    DIRECTION INPUT ;
    USE SIGNAL ;
    PORT
      LAYER M5 ;
        RECT  10.128 0 10.152 0.192 ;
    END
  END d[51]
  PIN d[52]
    DIRECTION INPUT ;
    USE SIGNAL ;
    PORT
      LAYER M3 ;
        RECT  10.224 0 10.242 0.144 ;
    END
  END d[52]
  PIN d[53]
    DIRECTION INPUT ;
    USE SIGNAL ;
    PORT
      LAYER M5 ;
        RECT  10.272 0 10.296 0.192 ;
    END
  END d[53]
  PIN d[54]
    DIRECTION INPUT ;
    USE SIGNAL ;
    PORT
      LAYER M3 ;
        RECT  10.368 0 10.386 0.144 ;
    END
  END d[54]
  PIN d[55]
    DIRECTION INPUT ;
    USE SIGNAL ;
    PORT
      LAYER M5 ;
        RECT  10.416 0 10.44 0.192 ;
    END
  END d[55]
  PIN d[56]
    DIRECTION INPUT ;
    USE SIGNAL ;
    PORT
      LAYER M3 ;
        RECT  10.512 0 10.53 0.144 ;
    END
  END d[56]
  PIN d[57]
    DIRECTION INPUT ;
    USE SIGNAL ;
    PORT
      LAYER M5 ;
        RECT  10.56 0 10.584 0.192 ;
    END
  END d[57]
  PIN d[58]
    DIRECTION INPUT ;
    USE SIGNAL ;
    PORT
      LAYER M3 ;
        RECT  10.656 0 10.674 0.144 ;
    END
  END d[58]
  PIN d[59]
    DIRECTION INPUT ;
    USE SIGNAL ;
    PORT
      LAYER M5 ;
        RECT  10.704 0 10.728 0.192 ;
    END
  END d[59]
  PIN d[5]
    DIRECTION INPUT ;
    USE SIGNAL ;
    PORT
      LAYER M5 ;
        RECT  6.816 0 6.84 0.192 ;
    END
  END d[5]
  PIN d[60]
    DIRECTION INPUT ;
    USE SIGNAL ;
    PORT
      LAYER M3 ;
        RECT  10.8 0 10.818 0.144 ;
    END
  END d[60]
  PIN d[61]
    DIRECTION INPUT ;
    USE SIGNAL ;
    PORT
      LAYER M5 ;
        RECT  10.848 0 10.872 0.192 ;
    END
  END d[61]
  PIN d[62]
    DIRECTION INPUT ;
    USE SIGNAL ;
    PORT
      LAYER M3 ;
        RECT  10.944 0 10.962 0.144 ;
    END
  END d[62]
  PIN d[63]
    DIRECTION INPUT ;
    USE SIGNAL ;
    PORT
      LAYER M5 ;
        RECT  10.992 0 11.016 0.192 ;
    END
  END d[63]
  PIN d[64]
    DIRECTION INPUT ;
    USE SIGNAL ;
    PORT
      LAYER M3 ;
        RECT  11.088 0 11.106 0.144 ;
    END
  END d[64]
  PIN d[65]
    DIRECTION INPUT ;
    USE SIGNAL ;
    PORT
      LAYER M5 ;
        RECT  11.136 0 11.16 0.192 ;
    END
  END d[65]
  PIN d[66]
    DIRECTION INPUT ;
    USE SIGNAL ;
    PORT
      LAYER M3 ;
        RECT  11.232 0 11.25 0.144 ;
    END
  END d[66]
  PIN d[67]
    DIRECTION INPUT ;
    USE SIGNAL ;
    PORT
      LAYER M5 ;
        RECT  11.28 0 11.304 0.192 ;
    END
  END d[67]
  PIN d[68]
    DIRECTION INPUT ;
    USE SIGNAL ;
    PORT
      LAYER M3 ;
        RECT  11.376 0 11.394 0.144 ;
    END
  END d[68]
  PIN d[69]
    DIRECTION INPUT ;
    USE SIGNAL ;
    PORT
      LAYER M5 ;
        RECT  11.424 0 11.448 0.192 ;
    END
  END d[69]
  PIN d[6]
    DIRECTION INPUT ;
    USE SIGNAL ;
    PORT
      LAYER M3 ;
        RECT  6.912 0 6.93 0.144 ;
    END
  END d[6]
  PIN d[70]
    DIRECTION INPUT ;
    USE SIGNAL ;
    PORT
      LAYER M3 ;
        RECT  11.52 0 11.538 0.144 ;
    END
  END d[70]
  PIN d[71]
    DIRECTION INPUT ;
    USE SIGNAL ;
    PORT
      LAYER M5 ;
        RECT  11.568 0 11.592 0.192 ;
    END
  END d[71]
  PIN d[72]
    DIRECTION INPUT ;
    USE SIGNAL ;
    PORT
      LAYER M3 ;
        RECT  11.664 0 11.682 0.144 ;
    END
  END d[72]
  PIN d[73]
    DIRECTION INPUT ;
    USE SIGNAL ;
    PORT
      LAYER M5 ;
        RECT  11.712 0 11.736 0.192 ;
    END
  END d[73]
  PIN d[74]
    DIRECTION INPUT ;
    USE SIGNAL ;
    PORT
      LAYER M3 ;
        RECT  11.808 0 11.826 0.144 ;
    END
  END d[74]
  PIN d[75]
    DIRECTION INPUT ;
    USE SIGNAL ;
    PORT
      LAYER M5 ;
        RECT  11.856 0 11.88 0.192 ;
    END
  END d[75]
  PIN d[76]
    DIRECTION INPUT ;
    USE SIGNAL ;
    PORT
      LAYER M3 ;
        RECT  11.952 0 11.97 0.144 ;
    END
  END d[76]
  PIN d[77]
    DIRECTION INPUT ;
    USE SIGNAL ;
    PORT
      LAYER M5 ;
        RECT  12 0 12.024 0.192 ;
    END
  END d[77]
  PIN d[78]
    DIRECTION INPUT ;
    USE SIGNAL ;
    PORT
      LAYER M3 ;
        RECT  12.096 0 12.114 0.144 ;
    END
  END d[78]
  PIN d[79]
    DIRECTION INPUT ;
    USE SIGNAL ;
    PORT
      LAYER M5 ;
        RECT  12.144 0 12.168 0.192 ;
    END
  END d[79]
  PIN d[7]
    DIRECTION INPUT ;
    USE SIGNAL ;
    PORT
      LAYER M5 ;
        RECT  6.96 0 6.984 0.192 ;
    END
  END d[7]
  PIN d[80]
    DIRECTION INPUT ;
    USE SIGNAL ;
    PORT
      LAYER M3 ;
        RECT  12.24 0 12.258 0.144 ;
    END
  END d[80]
  PIN d[81]
    DIRECTION INPUT ;
    USE SIGNAL ;
    PORT
      LAYER M5 ;
        RECT  12.288 0 12.312 0.192 ;
    END
  END d[81]
  PIN d[82]
    DIRECTION INPUT ;
    USE SIGNAL ;
    PORT
      LAYER M3 ;
        RECT  12.384 0 12.402 0.144 ;
    END
  END d[82]
  PIN d[83]
    DIRECTION INPUT ;
    USE SIGNAL ;
    PORT
      LAYER M5 ;
        RECT  12.432 0 12.456 0.192 ;
    END
  END d[83]
  PIN d[84]
    DIRECTION INPUT ;
    USE SIGNAL ;
    PORT
      LAYER M3 ;
        RECT  12.528 0 12.546 0.144 ;
    END
  END d[84]
  PIN d[85]
    DIRECTION INPUT ;
    USE SIGNAL ;
    PORT
      LAYER M5 ;
        RECT  12.576 0 12.6 0.192 ;
    END
  END d[85]
  PIN d[86]
    DIRECTION INPUT ;
    USE SIGNAL ;
    PORT
      LAYER M3 ;
        RECT  12.672 0 12.69 0.144 ;
    END
  END d[86]
  PIN d[87]
    DIRECTION INPUT ;
    USE SIGNAL ;
    PORT
      LAYER M5 ;
        RECT  12.72 0 12.744 0.192 ;
    END
  END d[87]
  PIN d[88]
    DIRECTION INPUT ;
    USE SIGNAL ;
    PORT
      LAYER M3 ;
        RECT  12.816 0 12.834 0.144 ;
    END
  END d[88]
  PIN d[89]
    DIRECTION INPUT ;
    USE SIGNAL ;
    PORT
      LAYER M5 ;
        RECT  12.864 0 12.888 0.192 ;
    END
  END d[89]
  PIN d[8]
    DIRECTION INPUT ;
    USE SIGNAL ;
    PORT
      LAYER M3 ;
        RECT  7.056 0 7.074 0.144 ;
    END
  END d[8]
  PIN d[90]
    DIRECTION INPUT ;
    USE SIGNAL ;
    PORT
      LAYER M3 ;
        RECT  12.96 0 12.978 0.144 ;
    END
  END d[90]
  PIN d[91]
    DIRECTION INPUT ;
    USE SIGNAL ;
    PORT
      LAYER M5 ;
        RECT  13.008 0 13.032 0.192 ;
    END
  END d[91]
  PIN d[92]
    DIRECTION INPUT ;
    USE SIGNAL ;
    PORT
      LAYER M3 ;
        RECT  13.104 0 13.122 0.144 ;
    END
  END d[92]
  PIN d[93]
    DIRECTION INPUT ;
    USE SIGNAL ;
    PORT
      LAYER M5 ;
        RECT  13.152 0 13.176 0.192 ;
    END
  END d[93]
  PIN d[94]
    DIRECTION INPUT ;
    USE SIGNAL ;
    PORT
      LAYER M3 ;
        RECT  13.248 0 13.266 0.144 ;
    END
  END d[94]
  PIN d[95]
    DIRECTION INPUT ;
    USE SIGNAL ;
    PORT
      LAYER M5 ;
        RECT  13.296 0 13.32 0.192 ;
    END
  END d[95]
  PIN d[96]
    DIRECTION INPUT ;
    USE SIGNAL ;
    PORT
      LAYER M3 ;
        RECT  13.392 0 13.41 0.144 ;
    END
  END d[96]
  PIN d[97]
    DIRECTION INPUT ;
    USE SIGNAL ;
    PORT
      LAYER M5 ;
        RECT  13.44 0 13.464 0.192 ;
    END
  END d[97]
  PIN d[98]
    DIRECTION INPUT ;
    USE SIGNAL ;
    PORT
      LAYER M3 ;
        RECT  13.536 0 13.554 0.144 ;
    END
  END d[98]
  PIN d[99]
    DIRECTION INPUT ;
    USE SIGNAL ;
    PORT
      LAYER M5 ;
        RECT  13.584 0 13.608 0.192 ;
    END
  END d[99]
  PIN d[9]
    DIRECTION INPUT ;
    USE SIGNAL ;
    PORT
      LAYER M5 ;
        RECT  7.104 0 7.128 0.192 ;
    END
  END d[9]
  PIN q[0]
    DIRECTION OUTPUT ;
    USE SIGNAL ;
    PORT
      LAYER M3 ;
        RECT  6.48 34.416 6.498 34.56 ;
    END
  END q[0]
  PIN q[100]
    DIRECTION OUTPUT ;
    USE SIGNAL ;
    PORT
      LAYER M3 ;
        RECT  13.68 34.416 13.698 34.56 ;
    END
  END q[100]
  PIN q[101]
    DIRECTION OUTPUT ;
    USE SIGNAL ;
    PORT
      LAYER M5 ;
        RECT  13.728 34.368 13.752 34.56 ;
    END
  END q[101]
  PIN q[102]
    DIRECTION OUTPUT ;
    USE SIGNAL ;
    PORT
      LAYER M3 ;
        RECT  13.824 34.416 13.842 34.56 ;
    END
  END q[102]
  PIN q[103]
    DIRECTION OUTPUT ;
    USE SIGNAL ;
    PORT
      LAYER M5 ;
        RECT  13.872 34.368 13.896 34.56 ;
    END
  END q[103]
  PIN q[104]
    DIRECTION OUTPUT ;
    USE SIGNAL ;
    PORT
      LAYER M3 ;
        RECT  13.968 34.416 13.986 34.56 ;
    END
  END q[104]
  PIN q[105]
    DIRECTION OUTPUT ;
    USE SIGNAL ;
    PORT
      LAYER M5 ;
        RECT  14.016 34.368 14.04 34.56 ;
    END
  END q[105]
  PIN q[106]
    DIRECTION OUTPUT ;
    USE SIGNAL ;
    PORT
      LAYER M3 ;
        RECT  14.112 34.416 14.13 34.56 ;
    END
  END q[106]
  PIN q[107]
    DIRECTION OUTPUT ;
    USE SIGNAL ;
    PORT
      LAYER M5 ;
        RECT  14.16 34.368 14.184 34.56 ;
    END
  END q[107]
  PIN q[108]
    DIRECTION OUTPUT ;
    USE SIGNAL ;
    PORT
      LAYER M3 ;
        RECT  14.256 34.416 14.274 34.56 ;
    END
  END q[108]
  PIN q[109]
    DIRECTION OUTPUT ;
    USE SIGNAL ;
    PORT
      LAYER M5 ;
        RECT  14.304 34.368 14.328 34.56 ;
    END
  END q[109]
  PIN q[10]
    DIRECTION OUTPUT ;
    USE SIGNAL ;
    PORT
      LAYER M3 ;
        RECT  7.2 34.416 7.218 34.56 ;
    END
  END q[10]
  PIN q[110]
    DIRECTION OUTPUT ;
    USE SIGNAL ;
    PORT
      LAYER M3 ;
        RECT  14.4 34.416 14.418 34.56 ;
    END
  END q[110]
  PIN q[111]
    DIRECTION OUTPUT ;
    USE SIGNAL ;
    PORT
      LAYER M5 ;
        RECT  14.448 34.368 14.472 34.56 ;
    END
  END q[111]
  PIN q[112]
    DIRECTION OUTPUT ;
    USE SIGNAL ;
    PORT
      LAYER M3 ;
        RECT  14.544 34.416 14.562 34.56 ;
    END
  END q[112]
  PIN q[113]
    DIRECTION OUTPUT ;
    USE SIGNAL ;
    PORT
      LAYER M5 ;
        RECT  14.592 34.368 14.616 34.56 ;
    END
  END q[113]
  PIN q[114]
    DIRECTION OUTPUT ;
    USE SIGNAL ;
    PORT
      LAYER M3 ;
        RECT  14.688 34.416 14.706 34.56 ;
    END
  END q[114]
  PIN q[115]
    DIRECTION OUTPUT ;
    USE SIGNAL ;
    PORT
      LAYER M5 ;
        RECT  14.736 34.368 14.76 34.56 ;
    END
  END q[115]
  PIN q[116]
    DIRECTION OUTPUT ;
    USE SIGNAL ;
    PORT
      LAYER M3 ;
        RECT  14.832 34.416 14.85 34.56 ;
    END
  END q[116]
  PIN q[117]
    DIRECTION OUTPUT ;
    USE SIGNAL ;
    PORT
      LAYER M5 ;
        RECT  14.88 34.368 14.904 34.56 ;
    END
  END q[117]
  PIN q[118]
    DIRECTION OUTPUT ;
    USE SIGNAL ;
    PORT
      LAYER M3 ;
        RECT  14.976 34.416 14.994 34.56 ;
    END
  END q[118]
  PIN q[119]
    DIRECTION OUTPUT ;
    USE SIGNAL ;
    PORT
      LAYER M5 ;
        RECT  15.024 34.368 15.048 34.56 ;
    END
  END q[119]
  PIN q[11]
    DIRECTION OUTPUT ;
    USE SIGNAL ;
    PORT
      LAYER M5 ;
        RECT  7.248 34.368 7.272 34.56 ;
    END
  END q[11]
  PIN q[120]
    DIRECTION OUTPUT ;
    USE SIGNAL ;
    PORT
      LAYER M3 ;
        RECT  15.12 34.416 15.138 34.56 ;
    END
  END q[120]
  PIN q[121]
    DIRECTION OUTPUT ;
    USE SIGNAL ;
    PORT
      LAYER M5 ;
        RECT  15.168 34.368 15.192 34.56 ;
    END
  END q[121]
  PIN q[122]
    DIRECTION OUTPUT ;
    USE SIGNAL ;
    PORT
      LAYER M3 ;
        RECT  15.264 34.416 15.282 34.56 ;
    END
  END q[122]
  PIN q[123]
    DIRECTION OUTPUT ;
    USE SIGNAL ;
    PORT
      LAYER M5 ;
        RECT  15.312 34.368 15.336 34.56 ;
    END
  END q[123]
  PIN q[124]
    DIRECTION OUTPUT ;
    USE SIGNAL ;
    PORT
      LAYER M3 ;
        RECT  15.408 34.416 15.426 34.56 ;
    END
  END q[124]
  PIN q[125]
    DIRECTION OUTPUT ;
    USE SIGNAL ;
    PORT
      LAYER M5 ;
        RECT  15.456 34.368 15.48 34.56 ;
    END
  END q[125]
  PIN q[126]
    DIRECTION OUTPUT ;
    USE SIGNAL ;
    PORT
      LAYER M3 ;
        RECT  15.552 34.416 15.57 34.56 ;
    END
  END q[126]
  PIN q[127]
    DIRECTION OUTPUT ;
    USE SIGNAL ;
    PORT
      LAYER M5 ;
        RECT  15.6 34.368 15.624 34.56 ;
    END
  END q[127]
  PIN q[128]
    DIRECTION OUTPUT ;
    USE SIGNAL ;
    PORT
      LAYER M3 ;
        RECT  15.696 34.416 15.714 34.56 ;
    END
  END q[128]
  PIN q[129]
    DIRECTION OUTPUT ;
    USE SIGNAL ;
    PORT
      LAYER M5 ;
        RECT  15.744 34.368 15.768 34.56 ;
    END
  END q[129]
  PIN q[12]
    DIRECTION OUTPUT ;
    USE SIGNAL ;
    PORT
      LAYER M3 ;
        RECT  7.344 34.416 7.362 34.56 ;
    END
  END q[12]
  PIN q[130]
    DIRECTION OUTPUT ;
    USE SIGNAL ;
    PORT
      LAYER M3 ;
        RECT  15.84 34.416 15.858 34.56 ;
    END
  END q[130]
  PIN q[131]
    DIRECTION OUTPUT ;
    USE SIGNAL ;
    PORT
      LAYER M5 ;
        RECT  15.888 34.368 15.912 34.56 ;
    END
  END q[131]
  PIN q[132]
    DIRECTION OUTPUT ;
    USE SIGNAL ;
    PORT
      LAYER M3 ;
        RECT  15.984 34.416 16.002 34.56 ;
    END
  END q[132]
  PIN q[133]
    DIRECTION OUTPUT ;
    USE SIGNAL ;
    PORT
      LAYER M5 ;
        RECT  16.032 34.368 16.056 34.56 ;
    END
  END q[133]
  PIN q[134]
    DIRECTION OUTPUT ;
    USE SIGNAL ;
    PORT
      LAYER M3 ;
        RECT  16.128 34.416 16.146 34.56 ;
    END
  END q[134]
  PIN q[135]
    DIRECTION OUTPUT ;
    USE SIGNAL ;
    PORT
      LAYER M5 ;
        RECT  16.176 34.368 16.2 34.56 ;
    END
  END q[135]
  PIN q[136]
    DIRECTION OUTPUT ;
    USE SIGNAL ;
    PORT
      LAYER M3 ;
        RECT  16.272 34.416 16.29 34.56 ;
    END
  END q[136]
  PIN q[137]
    DIRECTION OUTPUT ;
    USE SIGNAL ;
    PORT
      LAYER M5 ;
        RECT  16.32 34.368 16.344 34.56 ;
    END
  END q[137]
  PIN q[138]
    DIRECTION OUTPUT ;
    USE SIGNAL ;
    PORT
      LAYER M3 ;
        RECT  16.416 34.416 16.434 34.56 ;
    END
  END q[138]
  PIN q[139]
    DIRECTION OUTPUT ;
    USE SIGNAL ;
    PORT
      LAYER M5 ;
        RECT  16.464 34.368 16.488 34.56 ;
    END
  END q[139]
  PIN q[13]
    DIRECTION OUTPUT ;
    USE SIGNAL ;
    PORT
      LAYER M5 ;
        RECT  7.392 34.368 7.416 34.56 ;
    END
  END q[13]
  PIN q[140]
    DIRECTION OUTPUT ;
    USE SIGNAL ;
    PORT
      LAYER M3 ;
        RECT  16.56 34.416 16.578 34.56 ;
    END
  END q[140]
  PIN q[141]
    DIRECTION OUTPUT ;
    USE SIGNAL ;
    PORT
      LAYER M5 ;
        RECT  16.608 34.368 16.632 34.56 ;
    END
  END q[141]
  PIN q[142]
    DIRECTION OUTPUT ;
    USE SIGNAL ;
    PORT
      LAYER M3 ;
        RECT  16.704 34.416 16.722 34.56 ;
    END
  END q[142]
  PIN q[143]
    DIRECTION OUTPUT ;
    USE SIGNAL ;
    PORT
      LAYER M5 ;
        RECT  16.752 34.368 16.776 34.56 ;
    END
  END q[143]
  PIN q[144]
    DIRECTION OUTPUT ;
    USE SIGNAL ;
    PORT
      LAYER M3 ;
        RECT  16.848 34.416 16.866 34.56 ;
    END
  END q[144]
  PIN q[145]
    DIRECTION OUTPUT ;
    USE SIGNAL ;
    PORT
      LAYER M5 ;
        RECT  16.896 34.368 16.92 34.56 ;
    END
  END q[145]
  PIN q[146]
    DIRECTION OUTPUT ;
    USE SIGNAL ;
    PORT
      LAYER M3 ;
        RECT  16.992 34.416 17.01 34.56 ;
    END
  END q[146]
  PIN q[147]
    DIRECTION OUTPUT ;
    USE SIGNAL ;
    PORT
      LAYER M5 ;
        RECT  17.04 34.368 17.064 34.56 ;
    END
  END q[147]
  PIN q[148]
    DIRECTION OUTPUT ;
    USE SIGNAL ;
    PORT
      LAYER M3 ;
        RECT  17.136 34.416 17.154 34.56 ;
    END
  END q[148]
  PIN q[149]
    DIRECTION OUTPUT ;
    USE SIGNAL ;
    PORT
      LAYER M5 ;
        RECT  17.184 34.368 17.208 34.56 ;
    END
  END q[149]
  PIN q[14]
    DIRECTION OUTPUT ;
    USE SIGNAL ;
    PORT
      LAYER M3 ;
        RECT  7.488 34.416 7.506 34.56 ;
    END
  END q[14]
  PIN q[150]
    DIRECTION OUTPUT ;
    USE SIGNAL ;
    PORT
      LAYER M3 ;
        RECT  17.28 34.416 17.298 34.56 ;
    END
  END q[150]
  PIN q[151]
    DIRECTION OUTPUT ;
    USE SIGNAL ;
    PORT
      LAYER M5 ;
        RECT  17.328 34.368 17.352 34.56 ;
    END
  END q[151]
  PIN q[152]
    DIRECTION OUTPUT ;
    USE SIGNAL ;
    PORT
      LAYER M3 ;
        RECT  17.424 34.416 17.442 34.56 ;
    END
  END q[152]
  PIN q[153]
    DIRECTION OUTPUT ;
    USE SIGNAL ;
    PORT
      LAYER M5 ;
        RECT  17.472 34.368 17.496 34.56 ;
    END
  END q[153]
  PIN q[154]
    DIRECTION OUTPUT ;
    USE SIGNAL ;
    PORT
      LAYER M3 ;
        RECT  17.568 34.416 17.586 34.56 ;
    END
  END q[154]
  PIN q[155]
    DIRECTION OUTPUT ;
    USE SIGNAL ;
    PORT
      LAYER M5 ;
        RECT  17.616 34.368 17.64 34.56 ;
    END
  END q[155]
  PIN q[156]
    DIRECTION OUTPUT ;
    USE SIGNAL ;
    PORT
      LAYER M3 ;
        RECT  17.712 34.416 17.73 34.56 ;
    END
  END q[156]
  PIN q[157]
    DIRECTION OUTPUT ;
    USE SIGNAL ;
    PORT
      LAYER M5 ;
        RECT  17.76 34.368 17.784 34.56 ;
    END
  END q[157]
  PIN q[158]
    DIRECTION OUTPUT ;
    USE SIGNAL ;
    PORT
      LAYER M3 ;
        RECT  17.856 34.416 17.874 34.56 ;
    END
  END q[158]
  PIN q[159]
    DIRECTION OUTPUT ;
    USE SIGNAL ;
    PORT
      LAYER M5 ;
        RECT  17.904 34.368 17.928 34.56 ;
    END
  END q[159]
  PIN q[15]
    DIRECTION OUTPUT ;
    USE SIGNAL ;
    PORT
      LAYER M5 ;
        RECT  7.536 34.368 7.56 34.56 ;
    END
  END q[15]
  PIN q[160]
    DIRECTION OUTPUT ;
    USE SIGNAL ;
    PORT
      LAYER M3 ;
        RECT  18 34.416 18.018 34.56 ;
    END
  END q[160]
  PIN q[161]
    DIRECTION OUTPUT ;
    USE SIGNAL ;
    PORT
      LAYER M5 ;
        RECT  18.048 34.368 18.072 34.56 ;
    END
  END q[161]
  PIN q[162]
    DIRECTION OUTPUT ;
    USE SIGNAL ;
    PORT
      LAYER M3 ;
        RECT  18.144 34.416 18.162 34.56 ;
    END
  END q[162]
  PIN q[163]
    DIRECTION OUTPUT ;
    USE SIGNAL ;
    PORT
      LAYER M5 ;
        RECT  18.192 34.368 18.216 34.56 ;
    END
  END q[163]
  PIN q[164]
    DIRECTION OUTPUT ;
    USE SIGNAL ;
    PORT
      LAYER M3 ;
        RECT  18.288 34.416 18.306 34.56 ;
    END
  END q[164]
  PIN q[165]
    DIRECTION OUTPUT ;
    USE SIGNAL ;
    PORT
      LAYER M5 ;
        RECT  18.336 34.368 18.36 34.56 ;
    END
  END q[165]
  PIN q[166]
    DIRECTION OUTPUT ;
    USE SIGNAL ;
    PORT
      LAYER M3 ;
        RECT  18.432 34.416 18.45 34.56 ;
    END
  END q[166]
  PIN q[167]
    DIRECTION OUTPUT ;
    USE SIGNAL ;
    PORT
      LAYER M5 ;
        RECT  18.48 34.368 18.504 34.56 ;
    END
  END q[167]
  PIN q[168]
    DIRECTION OUTPUT ;
    USE SIGNAL ;
    PORT
      LAYER M3 ;
        RECT  18.576 34.416 18.594 34.56 ;
    END
  END q[168]
  PIN q[169]
    DIRECTION OUTPUT ;
    USE SIGNAL ;
    PORT
      LAYER M5 ;
        RECT  18.624 34.368 18.648 34.56 ;
    END
  END q[169]
  PIN q[16]
    DIRECTION OUTPUT ;
    USE SIGNAL ;
    PORT
      LAYER M3 ;
        RECT  7.632 34.416 7.65 34.56 ;
    END
  END q[16]
  PIN q[170]
    DIRECTION OUTPUT ;
    USE SIGNAL ;
    PORT
      LAYER M3 ;
        RECT  18.72 34.416 18.738 34.56 ;
    END
  END q[170]
  PIN q[171]
    DIRECTION OUTPUT ;
    USE SIGNAL ;
    PORT
      LAYER M5 ;
        RECT  18.768 34.368 18.792 34.56 ;
    END
  END q[171]
  PIN q[172]
    DIRECTION OUTPUT ;
    USE SIGNAL ;
    PORT
      LAYER M3 ;
        RECT  18.864 34.416 18.882 34.56 ;
    END
  END q[172]
  PIN q[173]
    DIRECTION OUTPUT ;
    USE SIGNAL ;
    PORT
      LAYER M5 ;
        RECT  18.912 34.368 18.936 34.56 ;
    END
  END q[173]
  PIN q[174]
    DIRECTION OUTPUT ;
    USE SIGNAL ;
    PORT
      LAYER M3 ;
        RECT  19.008 34.416 19.026 34.56 ;
    END
  END q[174]
  PIN q[175]
    DIRECTION OUTPUT ;
    USE SIGNAL ;
    PORT
      LAYER M5 ;
        RECT  19.056 34.368 19.08 34.56 ;
    END
  END q[175]
  PIN q[176]
    DIRECTION OUTPUT ;
    USE SIGNAL ;
    PORT
      LAYER M3 ;
        RECT  19.152 34.416 19.17 34.56 ;
    END
  END q[176]
  PIN q[177]
    DIRECTION OUTPUT ;
    USE SIGNAL ;
    PORT
      LAYER M5 ;
        RECT  19.2 34.368 19.224 34.56 ;
    END
  END q[177]
  PIN q[178]
    DIRECTION OUTPUT ;
    USE SIGNAL ;
    PORT
      LAYER M3 ;
        RECT  19.296 34.416 19.314 34.56 ;
    END
  END q[178]
  PIN q[179]
    DIRECTION OUTPUT ;
    USE SIGNAL ;
    PORT
      LAYER M5 ;
        RECT  19.344 34.368 19.368 34.56 ;
    END
  END q[179]
  PIN q[17]
    DIRECTION OUTPUT ;
    USE SIGNAL ;
    PORT
      LAYER M5 ;
        RECT  7.68 34.368 7.704 34.56 ;
    END
  END q[17]
  PIN q[180]
    DIRECTION OUTPUT ;
    USE SIGNAL ;
    PORT
      LAYER M3 ;
        RECT  19.44 34.416 19.458 34.56 ;
    END
  END q[180]
  PIN q[181]
    DIRECTION OUTPUT ;
    USE SIGNAL ;
    PORT
      LAYER M5 ;
        RECT  19.488 34.368 19.512 34.56 ;
    END
  END q[181]
  PIN q[182]
    DIRECTION OUTPUT ;
    USE SIGNAL ;
    PORT
      LAYER M3 ;
        RECT  19.584 34.416 19.602 34.56 ;
    END
  END q[182]
  PIN q[183]
    DIRECTION OUTPUT ;
    USE SIGNAL ;
    PORT
      LAYER M5 ;
        RECT  19.632 34.368 19.656 34.56 ;
    END
  END q[183]
  PIN q[184]
    DIRECTION OUTPUT ;
    USE SIGNAL ;
    PORT
      LAYER M3 ;
        RECT  19.728 34.416 19.746 34.56 ;
    END
  END q[184]
  PIN q[185]
    DIRECTION OUTPUT ;
    USE SIGNAL ;
    PORT
      LAYER M5 ;
        RECT  19.776 34.368 19.8 34.56 ;
    END
  END q[185]
  PIN q[186]
    DIRECTION OUTPUT ;
    USE SIGNAL ;
    PORT
      LAYER M3 ;
        RECT  19.872 34.416 19.89 34.56 ;
    END
  END q[186]
  PIN q[187]
    DIRECTION OUTPUT ;
    USE SIGNAL ;
    PORT
      LAYER M5 ;
        RECT  19.92 34.368 19.944 34.56 ;
    END
  END q[187]
  PIN q[188]
    DIRECTION OUTPUT ;
    USE SIGNAL ;
    PORT
      LAYER M3 ;
        RECT  20.016 34.416 20.034 34.56 ;
    END
  END q[188]
  PIN q[189]
    DIRECTION OUTPUT ;
    USE SIGNAL ;
    PORT
      LAYER M5 ;
        RECT  20.064 34.368 20.088 34.56 ;
    END
  END q[189]
  PIN q[18]
    DIRECTION OUTPUT ;
    USE SIGNAL ;
    PORT
      LAYER M3 ;
        RECT  7.776 34.416 7.794 34.56 ;
    END
  END q[18]
  PIN q[190]
    DIRECTION OUTPUT ;
    USE SIGNAL ;
    PORT
      LAYER M3 ;
        RECT  20.16 34.416 20.178 34.56 ;
    END
  END q[190]
  PIN q[191]
    DIRECTION OUTPUT ;
    USE SIGNAL ;
    PORT
      LAYER M5 ;
        RECT  20.208 34.368 20.232 34.56 ;
    END
  END q[191]
  PIN q[192]
    DIRECTION OUTPUT ;
    USE SIGNAL ;
    PORT
      LAYER M3 ;
        RECT  20.304 34.416 20.322 34.56 ;
    END
  END q[192]
  PIN q[193]
    DIRECTION OUTPUT ;
    USE SIGNAL ;
    PORT
      LAYER M5 ;
        RECT  20.352 34.368 20.376 34.56 ;
    END
  END q[193]
  PIN q[194]
    DIRECTION OUTPUT ;
    USE SIGNAL ;
    PORT
      LAYER M3 ;
        RECT  20.448 34.416 20.466 34.56 ;
    END
  END q[194]
  PIN q[195]
    DIRECTION OUTPUT ;
    USE SIGNAL ;
    PORT
      LAYER M5 ;
        RECT  20.496 34.368 20.52 34.56 ;
    END
  END q[195]
  PIN q[196]
    DIRECTION OUTPUT ;
    USE SIGNAL ;
    PORT
      LAYER M3 ;
        RECT  20.592 34.416 20.61 34.56 ;
    END
  END q[196]
  PIN q[197]
    DIRECTION OUTPUT ;
    USE SIGNAL ;
    PORT
      LAYER M5 ;
        RECT  20.64 34.368 20.664 34.56 ;
    END
  END q[197]
  PIN q[198]
    DIRECTION OUTPUT ;
    USE SIGNAL ;
    PORT
      LAYER M3 ;
        RECT  20.736 34.416 20.754 34.56 ;
    END
  END q[198]
  PIN q[199]
    DIRECTION OUTPUT ;
    USE SIGNAL ;
    PORT
      LAYER M5 ;
        RECT  20.784 34.368 20.808 34.56 ;
    END
  END q[199]
  PIN q[19]
    DIRECTION OUTPUT ;
    USE SIGNAL ;
    PORT
      LAYER M5 ;
        RECT  7.824 34.368 7.848 34.56 ;
    END
  END q[19]
  PIN q[1]
    DIRECTION OUTPUT ;
    USE SIGNAL ;
    PORT
      LAYER M5 ;
        RECT  6.528 34.368 6.552 34.56 ;
    END
  END q[1]
  PIN q[200]
    DIRECTION OUTPUT ;
    USE SIGNAL ;
    PORT
      LAYER M3 ;
        RECT  20.88 34.416 20.898 34.56 ;
    END
  END q[200]
  PIN q[201]
    DIRECTION OUTPUT ;
    USE SIGNAL ;
    PORT
      LAYER M5 ;
        RECT  20.928 34.368 20.952 34.56 ;
    END
  END q[201]
  PIN q[202]
    DIRECTION OUTPUT ;
    USE SIGNAL ;
    PORT
      LAYER M3 ;
        RECT  21.024 34.416 21.042 34.56 ;
    END
  END q[202]
  PIN q[203]
    DIRECTION OUTPUT ;
    USE SIGNAL ;
    PORT
      LAYER M5 ;
        RECT  21.072 34.368 21.096 34.56 ;
    END
  END q[203]
  PIN q[204]
    DIRECTION OUTPUT ;
    USE SIGNAL ;
    PORT
      LAYER M3 ;
        RECT  21.168 34.416 21.186 34.56 ;
    END
  END q[204]
  PIN q[205]
    DIRECTION OUTPUT ;
    USE SIGNAL ;
    PORT
      LAYER M5 ;
        RECT  21.216 34.368 21.24 34.56 ;
    END
  END q[205]
  PIN q[206]
    DIRECTION OUTPUT ;
    USE SIGNAL ;
    PORT
      LAYER M3 ;
        RECT  21.312 34.416 21.33 34.56 ;
    END
  END q[206]
  PIN q[207]
    DIRECTION OUTPUT ;
    USE SIGNAL ;
    PORT
      LAYER M5 ;
        RECT  21.36 34.368 21.384 34.56 ;
    END
  END q[207]
  PIN q[208]
    DIRECTION OUTPUT ;
    USE SIGNAL ;
    PORT
      LAYER M3 ;
        RECT  21.456 34.416 21.474 34.56 ;
    END
  END q[208]
  PIN q[209]
    DIRECTION OUTPUT ;
    USE SIGNAL ;
    PORT
      LAYER M5 ;
        RECT  21.504 34.368 21.528 34.56 ;
    END
  END q[209]
  PIN q[20]
    DIRECTION OUTPUT ;
    USE SIGNAL ;
    PORT
      LAYER M3 ;
        RECT  7.92 34.416 7.938 34.56 ;
    END
  END q[20]
  PIN q[210]
    DIRECTION OUTPUT ;
    USE SIGNAL ;
    PORT
      LAYER M3 ;
        RECT  21.6 34.416 21.618 34.56 ;
    END
  END q[210]
  PIN q[211]
    DIRECTION OUTPUT ;
    USE SIGNAL ;
    PORT
      LAYER M5 ;
        RECT  21.648 34.368 21.672 34.56 ;
    END
  END q[211]
  PIN q[212]
    DIRECTION OUTPUT ;
    USE SIGNAL ;
    PORT
      LAYER M3 ;
        RECT  21.744 34.416 21.762 34.56 ;
    END
  END q[212]
  PIN q[213]
    DIRECTION OUTPUT ;
    USE SIGNAL ;
    PORT
      LAYER M5 ;
        RECT  21.792 34.368 21.816 34.56 ;
    END
  END q[213]
  PIN q[214]
    DIRECTION OUTPUT ;
    USE SIGNAL ;
    PORT
      LAYER M3 ;
        RECT  21.888 34.416 21.906 34.56 ;
    END
  END q[214]
  PIN q[215]
    DIRECTION OUTPUT ;
    USE SIGNAL ;
    PORT
      LAYER M5 ;
        RECT  21.936 34.368 21.96 34.56 ;
    END
  END q[215]
  PIN q[216]
    DIRECTION OUTPUT ;
    USE SIGNAL ;
    PORT
      LAYER M3 ;
        RECT  22.032 34.416 22.05 34.56 ;
    END
  END q[216]
  PIN q[217]
    DIRECTION OUTPUT ;
    USE SIGNAL ;
    PORT
      LAYER M5 ;
        RECT  22.08 34.368 22.104 34.56 ;
    END
  END q[217]
  PIN q[218]
    DIRECTION OUTPUT ;
    USE SIGNAL ;
    PORT
      LAYER M3 ;
        RECT  22.176 34.416 22.194 34.56 ;
    END
  END q[218]
  PIN q[219]
    DIRECTION OUTPUT ;
    USE SIGNAL ;
    PORT
      LAYER M5 ;
        RECT  22.224 34.368 22.248 34.56 ;
    END
  END q[219]
  PIN q[21]
    DIRECTION OUTPUT ;
    USE SIGNAL ;
    PORT
      LAYER M5 ;
        RECT  7.968 34.368 7.992 34.56 ;
    END
  END q[21]
  PIN q[220]
    DIRECTION OUTPUT ;
    USE SIGNAL ;
    PORT
      LAYER M3 ;
        RECT  22.32 34.416 22.338 34.56 ;
    END
  END q[220]
  PIN q[221]
    DIRECTION OUTPUT ;
    USE SIGNAL ;
    PORT
      LAYER M5 ;
        RECT  22.368 34.368 22.392 34.56 ;
    END
  END q[221]
  PIN q[222]
    DIRECTION OUTPUT ;
    USE SIGNAL ;
    PORT
      LAYER M3 ;
        RECT  22.464 34.416 22.482 34.56 ;
    END
  END q[222]
  PIN q[223]
    DIRECTION OUTPUT ;
    USE SIGNAL ;
    PORT
      LAYER M5 ;
        RECT  22.512 34.368 22.536 34.56 ;
    END
  END q[223]
  PIN q[224]
    DIRECTION OUTPUT ;
    USE SIGNAL ;
    PORT
      LAYER M3 ;
        RECT  22.608 34.416 22.626 34.56 ;
    END
  END q[224]
  PIN q[225]
    DIRECTION OUTPUT ;
    USE SIGNAL ;
    PORT
      LAYER M5 ;
        RECT  22.656 34.368 22.68 34.56 ;
    END
  END q[225]
  PIN q[226]
    DIRECTION OUTPUT ;
    USE SIGNAL ;
    PORT
      LAYER M3 ;
        RECT  22.752 34.416 22.77 34.56 ;
    END
  END q[226]
  PIN q[227]
    DIRECTION OUTPUT ;
    USE SIGNAL ;
    PORT
      LAYER M5 ;
        RECT  22.8 34.368 22.824 34.56 ;
    END
  END q[227]
  PIN q[228]
    DIRECTION OUTPUT ;
    USE SIGNAL ;
    PORT
      LAYER M3 ;
        RECT  22.896 34.416 22.914 34.56 ;
    END
  END q[228]
  PIN q[229]
    DIRECTION OUTPUT ;
    USE SIGNAL ;
    PORT
      LAYER M5 ;
        RECT  22.944 34.368 22.968 34.56 ;
    END
  END q[229]
  PIN q[22]
    DIRECTION OUTPUT ;
    USE SIGNAL ;
    PORT
      LAYER M3 ;
        RECT  8.064 34.416 8.082 34.56 ;
    END
  END q[22]
  PIN q[230]
    DIRECTION OUTPUT ;
    USE SIGNAL ;
    PORT
      LAYER M3 ;
        RECT  23.04 34.416 23.058 34.56 ;
    END
  END q[230]
  PIN q[231]
    DIRECTION OUTPUT ;
    USE SIGNAL ;
    PORT
      LAYER M5 ;
        RECT  23.088 34.368 23.112 34.56 ;
    END
  END q[231]
  PIN q[232]
    DIRECTION OUTPUT ;
    USE SIGNAL ;
    PORT
      LAYER M3 ;
        RECT  23.184 34.416 23.202 34.56 ;
    END
  END q[232]
  PIN q[233]
    DIRECTION OUTPUT ;
    USE SIGNAL ;
    PORT
      LAYER M5 ;
        RECT  23.232 34.368 23.256 34.56 ;
    END
  END q[233]
  PIN q[234]
    DIRECTION OUTPUT ;
    USE SIGNAL ;
    PORT
      LAYER M3 ;
        RECT  23.328 34.416 23.346 34.56 ;
    END
  END q[234]
  PIN q[235]
    DIRECTION OUTPUT ;
    USE SIGNAL ;
    PORT
      LAYER M5 ;
        RECT  23.376 34.368 23.4 34.56 ;
    END
  END q[235]
  PIN q[236]
    DIRECTION OUTPUT ;
    USE SIGNAL ;
    PORT
      LAYER M3 ;
        RECT  23.472 34.416 23.49 34.56 ;
    END
  END q[236]
  PIN q[237]
    DIRECTION OUTPUT ;
    USE SIGNAL ;
    PORT
      LAYER M5 ;
        RECT  23.52 34.368 23.544 34.56 ;
    END
  END q[237]
  PIN q[238]
    DIRECTION OUTPUT ;
    USE SIGNAL ;
    PORT
      LAYER M3 ;
        RECT  23.616 34.416 23.634 34.56 ;
    END
  END q[238]
  PIN q[239]
    DIRECTION OUTPUT ;
    USE SIGNAL ;
    PORT
      LAYER M5 ;
        RECT  23.664 34.368 23.688 34.56 ;
    END
  END q[239]
  PIN q[23]
    DIRECTION OUTPUT ;
    USE SIGNAL ;
    PORT
      LAYER M5 ;
        RECT  8.112 34.368 8.136 34.56 ;
    END
  END q[23]
  PIN q[240]
    DIRECTION OUTPUT ;
    USE SIGNAL ;
    PORT
      LAYER M3 ;
        RECT  23.76 34.416 23.778 34.56 ;
    END
  END q[240]
  PIN q[241]
    DIRECTION OUTPUT ;
    USE SIGNAL ;
    PORT
      LAYER M5 ;
        RECT  23.808 34.368 23.832 34.56 ;
    END
  END q[241]
  PIN q[242]
    DIRECTION OUTPUT ;
    USE SIGNAL ;
    PORT
      LAYER M3 ;
        RECT  23.904 34.416 23.922 34.56 ;
    END
  END q[242]
  PIN q[243]
    DIRECTION OUTPUT ;
    USE SIGNAL ;
    PORT
      LAYER M5 ;
        RECT  23.952 34.368 23.976 34.56 ;
    END
  END q[243]
  PIN q[244]
    DIRECTION OUTPUT ;
    USE SIGNAL ;
    PORT
      LAYER M3 ;
        RECT  24.048 34.416 24.066 34.56 ;
    END
  END q[244]
  PIN q[245]
    DIRECTION OUTPUT ;
    USE SIGNAL ;
    PORT
      LAYER M5 ;
        RECT  24.096 34.368 24.12 34.56 ;
    END
  END q[245]
  PIN q[246]
    DIRECTION OUTPUT ;
    USE SIGNAL ;
    PORT
      LAYER M3 ;
        RECT  24.192 34.416 24.21 34.56 ;
    END
  END q[246]
  PIN q[247]
    DIRECTION OUTPUT ;
    USE SIGNAL ;
    PORT
      LAYER M5 ;
        RECT  24.24 34.368 24.264 34.56 ;
    END
  END q[247]
  PIN q[248]
    DIRECTION OUTPUT ;
    USE SIGNAL ;
    PORT
      LAYER M3 ;
        RECT  24.336 34.416 24.354 34.56 ;
    END
  END q[248]
  PIN q[249]
    DIRECTION OUTPUT ;
    USE SIGNAL ;
    PORT
      LAYER M5 ;
        RECT  24.384 34.368 24.408 34.56 ;
    END
  END q[249]
  PIN q[24]
    DIRECTION OUTPUT ;
    USE SIGNAL ;
    PORT
      LAYER M3 ;
        RECT  8.208 34.416 8.226 34.56 ;
    END
  END q[24]
  PIN q[250]
    DIRECTION OUTPUT ;
    USE SIGNAL ;
    PORT
      LAYER M3 ;
        RECT  24.48 34.416 24.498 34.56 ;
    END
  END q[250]
  PIN q[251]
    DIRECTION OUTPUT ;
    USE SIGNAL ;
    PORT
      LAYER M5 ;
        RECT  24.528 34.368 24.552 34.56 ;
    END
  END q[251]
  PIN q[252]
    DIRECTION OUTPUT ;
    USE SIGNAL ;
    PORT
      LAYER M3 ;
        RECT  24.624 34.416 24.642 34.56 ;
    END
  END q[252]
  PIN q[253]
    DIRECTION OUTPUT ;
    USE SIGNAL ;
    PORT
      LAYER M5 ;
        RECT  24.672 34.368 24.696 34.56 ;
    END
  END q[253]
  PIN q[254]
    DIRECTION OUTPUT ;
    USE SIGNAL ;
    PORT
      LAYER M3 ;
        RECT  24.768 34.416 24.786 34.56 ;
    END
  END q[254]
  PIN q[255]
    DIRECTION OUTPUT ;
    USE SIGNAL ;
    PORT
      LAYER M5 ;
        RECT  24.816 34.368 24.84 34.56 ;
    END
  END q[255]
  PIN q[256]
    DIRECTION OUTPUT ;
    USE SIGNAL ;
    PORT
      LAYER M3 ;
        RECT  24.912 34.416 24.93 34.56 ;
    END
  END q[256]
  PIN q[257]
    DIRECTION OUTPUT ;
    USE SIGNAL ;
    PORT
      LAYER M5 ;
        RECT  24.96 34.368 24.984 34.56 ;
    END
  END q[257]
  PIN q[258]
    DIRECTION OUTPUT ;
    USE SIGNAL ;
    PORT
      LAYER M3 ;
        RECT  25.056 34.416 25.074 34.56 ;
    END
  END q[258]
  PIN q[259]
    DIRECTION OUTPUT ;
    USE SIGNAL ;
    PORT
      LAYER M5 ;
        RECT  25.104 34.368 25.128 34.56 ;
    END
  END q[259]
  PIN q[25]
    DIRECTION OUTPUT ;
    USE SIGNAL ;
    PORT
      LAYER M5 ;
        RECT  8.256 34.368 8.28 34.56 ;
    END
  END q[25]
  PIN q[260]
    DIRECTION OUTPUT ;
    USE SIGNAL ;
    PORT
      LAYER M3 ;
        RECT  25.2 34.416 25.218 34.56 ;
    END
  END q[260]
  PIN q[261]
    DIRECTION OUTPUT ;
    USE SIGNAL ;
    PORT
      LAYER M5 ;
        RECT  25.248 34.368 25.272 34.56 ;
    END
  END q[261]
  PIN q[262]
    DIRECTION OUTPUT ;
    USE SIGNAL ;
    PORT
      LAYER M3 ;
        RECT  25.344 34.416 25.362 34.56 ;
    END
  END q[262]
  PIN q[263]
    DIRECTION OUTPUT ;
    USE SIGNAL ;
    PORT
      LAYER M5 ;
        RECT  25.392 34.368 25.416 34.56 ;
    END
  END q[263]
  PIN q[264]
    DIRECTION OUTPUT ;
    USE SIGNAL ;
    PORT
      LAYER M3 ;
        RECT  25.488 34.416 25.506 34.56 ;
    END
  END q[264]
  PIN q[265]
    DIRECTION OUTPUT ;
    USE SIGNAL ;
    PORT
      LAYER M5 ;
        RECT  25.536 34.368 25.56 34.56 ;
    END
  END q[265]
  PIN q[266]
    DIRECTION OUTPUT ;
    USE SIGNAL ;
    PORT
      LAYER M3 ;
        RECT  25.632 34.416 25.65 34.56 ;
    END
  END q[266]
  PIN q[267]
    DIRECTION OUTPUT ;
    USE SIGNAL ;
    PORT
      LAYER M5 ;
        RECT  25.68 34.368 25.704 34.56 ;
    END
  END q[267]
  PIN q[268]
    DIRECTION OUTPUT ;
    USE SIGNAL ;
    PORT
      LAYER M3 ;
        RECT  25.776 34.416 25.794 34.56 ;
    END
  END q[268]
  PIN q[269]
    DIRECTION OUTPUT ;
    USE SIGNAL ;
    PORT
      LAYER M5 ;
        RECT  25.824 34.368 25.848 34.56 ;
    END
  END q[269]
  PIN q[26]
    DIRECTION OUTPUT ;
    USE SIGNAL ;
    PORT
      LAYER M3 ;
        RECT  8.352 34.416 8.37 34.56 ;
    END
  END q[26]
  PIN q[270]
    DIRECTION OUTPUT ;
    USE SIGNAL ;
    PORT
      LAYER M3 ;
        RECT  25.92 34.416 25.938 34.56 ;
    END
  END q[270]
  PIN q[271]
    DIRECTION OUTPUT ;
    USE SIGNAL ;
    PORT
      LAYER M5 ;
        RECT  25.968 34.368 25.992 34.56 ;
    END
  END q[271]
  PIN q[272]
    DIRECTION OUTPUT ;
    USE SIGNAL ;
    PORT
      LAYER M3 ;
        RECT  26.064 34.416 26.082 34.56 ;
    END
  END q[272]
  PIN q[273]
    DIRECTION OUTPUT ;
    USE SIGNAL ;
    PORT
      LAYER M5 ;
        RECT  26.112 34.368 26.136 34.56 ;
    END
  END q[273]
  PIN q[274]
    DIRECTION OUTPUT ;
    USE SIGNAL ;
    PORT
      LAYER M3 ;
        RECT  26.208 34.416 26.226 34.56 ;
    END
  END q[274]
  PIN q[275]
    DIRECTION OUTPUT ;
    USE SIGNAL ;
    PORT
      LAYER M5 ;
        RECT  26.256 34.368 26.28 34.56 ;
    END
  END q[275]
  PIN q[276]
    DIRECTION OUTPUT ;
    USE SIGNAL ;
    PORT
      LAYER M3 ;
        RECT  26.352 34.416 26.37 34.56 ;
    END
  END q[276]
  PIN q[277]
    DIRECTION OUTPUT ;
    USE SIGNAL ;
    PORT
      LAYER M5 ;
        RECT  26.4 34.368 26.424 34.56 ;
    END
  END q[277]
  PIN q[278]
    DIRECTION OUTPUT ;
    USE SIGNAL ;
    PORT
      LAYER M3 ;
        RECT  26.496 34.416 26.514 34.56 ;
    END
  END q[278]
  PIN q[279]
    DIRECTION OUTPUT ;
    USE SIGNAL ;
    PORT
      LAYER M5 ;
        RECT  26.544 34.368 26.568 34.56 ;
    END
  END q[279]
  PIN q[27]
    DIRECTION OUTPUT ;
    USE SIGNAL ;
    PORT
      LAYER M5 ;
        RECT  8.4 34.368 8.424 34.56 ;
    END
  END q[27]
  PIN q[280]
    DIRECTION OUTPUT ;
    USE SIGNAL ;
    PORT
      LAYER M3 ;
        RECT  26.64 34.416 26.658 34.56 ;
    END
  END q[280]
  PIN q[281]
    DIRECTION OUTPUT ;
    USE SIGNAL ;
    PORT
      LAYER M5 ;
        RECT  26.688 34.368 26.712 34.56 ;
    END
  END q[281]
  PIN q[282]
    DIRECTION OUTPUT ;
    USE SIGNAL ;
    PORT
      LAYER M3 ;
        RECT  26.784 34.416 26.802 34.56 ;
    END
  END q[282]
  PIN q[283]
    DIRECTION OUTPUT ;
    USE SIGNAL ;
    PORT
      LAYER M5 ;
        RECT  26.832 34.368 26.856 34.56 ;
    END
  END q[283]
  PIN q[284]
    DIRECTION OUTPUT ;
    USE SIGNAL ;
    PORT
      LAYER M3 ;
        RECT  26.928 34.416 26.946 34.56 ;
    END
  END q[284]
  PIN q[285]
    DIRECTION OUTPUT ;
    USE SIGNAL ;
    PORT
      LAYER M5 ;
        RECT  26.976 34.368 27 34.56 ;
    END
  END q[285]
  PIN q[286]
    DIRECTION OUTPUT ;
    USE SIGNAL ;
    PORT
      LAYER M3 ;
        RECT  27.072 34.416 27.09 34.56 ;
    END
  END q[286]
  PIN q[287]
    DIRECTION OUTPUT ;
    USE SIGNAL ;
    PORT
      LAYER M5 ;
        RECT  27.12 34.368 27.144 34.56 ;
    END
  END q[287]
  PIN q[288]
    DIRECTION OUTPUT ;
    USE SIGNAL ;
    PORT
      LAYER M3 ;
        RECT  27.216 34.416 27.234 34.56 ;
    END
  END q[288]
  PIN q[289]
    DIRECTION OUTPUT ;
    USE SIGNAL ;
    PORT
      LAYER M5 ;
        RECT  27.264 34.368 27.288 34.56 ;
    END
  END q[289]
  PIN q[28]
    DIRECTION OUTPUT ;
    USE SIGNAL ;
    PORT
      LAYER M3 ;
        RECT  8.496 34.416 8.514 34.56 ;
    END
  END q[28]
  PIN q[290]
    DIRECTION OUTPUT ;
    USE SIGNAL ;
    PORT
      LAYER M3 ;
        RECT  27.36 34.416 27.378 34.56 ;
    END
  END q[290]
  PIN q[291]
    DIRECTION OUTPUT ;
    USE SIGNAL ;
    PORT
      LAYER M5 ;
        RECT  27.408 34.368 27.432 34.56 ;
    END
  END q[291]
  PIN q[292]
    DIRECTION OUTPUT ;
    USE SIGNAL ;
    PORT
      LAYER M3 ;
        RECT  27.504 34.416 27.522 34.56 ;
    END
  END q[292]
  PIN q[293]
    DIRECTION OUTPUT ;
    USE SIGNAL ;
    PORT
      LAYER M5 ;
        RECT  27.552 34.368 27.576 34.56 ;
    END
  END q[293]
  PIN q[294]
    DIRECTION OUTPUT ;
    USE SIGNAL ;
    PORT
      LAYER M3 ;
        RECT  27.648 34.416 27.666 34.56 ;
    END
  END q[294]
  PIN q[295]
    DIRECTION OUTPUT ;
    USE SIGNAL ;
    PORT
      LAYER M5 ;
        RECT  27.696 34.368 27.72 34.56 ;
    END
  END q[295]
  PIN q[296]
    DIRECTION OUTPUT ;
    USE SIGNAL ;
    PORT
      LAYER M3 ;
        RECT  27.792 34.416 27.81 34.56 ;
    END
  END q[296]
  PIN q[297]
    DIRECTION OUTPUT ;
    USE SIGNAL ;
    PORT
      LAYER M5 ;
        RECT  27.84 34.368 27.864 34.56 ;
    END
  END q[297]
  PIN q[298]
    DIRECTION OUTPUT ;
    USE SIGNAL ;
    PORT
      LAYER M3 ;
        RECT  27.936 34.416 27.954 34.56 ;
    END
  END q[298]
  PIN q[299]
    DIRECTION OUTPUT ;
    USE SIGNAL ;
    PORT
      LAYER M5 ;
        RECT  27.984 34.368 28.008 34.56 ;
    END
  END q[299]
  PIN q[29]
    DIRECTION OUTPUT ;
    USE SIGNAL ;
    PORT
      LAYER M5 ;
        RECT  8.544 34.368 8.568 34.56 ;
    END
  END q[29]
  PIN q[2]
    DIRECTION OUTPUT ;
    USE SIGNAL ;
    PORT
      LAYER M3 ;
        RECT  6.624 34.416 6.642 34.56 ;
    END
  END q[2]
  PIN q[300]
    DIRECTION OUTPUT ;
    USE SIGNAL ;
    PORT
      LAYER M3 ;
        RECT  28.08 34.416 28.098 34.56 ;
    END
  END q[300]
  PIN q[301]
    DIRECTION OUTPUT ;
    USE SIGNAL ;
    PORT
      LAYER M5 ;
        RECT  28.128 34.368 28.152 34.56 ;
    END
  END q[301]
  PIN q[302]
    DIRECTION OUTPUT ;
    USE SIGNAL ;
    PORT
      LAYER M3 ;
        RECT  28.224 34.416 28.242 34.56 ;
    END
  END q[302]
  PIN q[303]
    DIRECTION OUTPUT ;
    USE SIGNAL ;
    PORT
      LAYER M5 ;
        RECT  28.272 34.368 28.296 34.56 ;
    END
  END q[303]
  PIN q[304]
    DIRECTION OUTPUT ;
    USE SIGNAL ;
    PORT
      LAYER M3 ;
        RECT  28.368 34.416 28.386 34.56 ;
    END
  END q[304]
  PIN q[305]
    DIRECTION OUTPUT ;
    USE SIGNAL ;
    PORT
      LAYER M5 ;
        RECT  28.416 34.368 28.44 34.56 ;
    END
  END q[305]
  PIN q[306]
    DIRECTION OUTPUT ;
    USE SIGNAL ;
    PORT
      LAYER M3 ;
        RECT  28.512 34.416 28.53 34.56 ;
    END
  END q[306]
  PIN q[307]
    DIRECTION OUTPUT ;
    USE SIGNAL ;
    PORT
      LAYER M5 ;
        RECT  28.56 34.368 28.584 34.56 ;
    END
  END q[307]
  PIN q[308]
    DIRECTION OUTPUT ;
    USE SIGNAL ;
    PORT
      LAYER M3 ;
        RECT  28.656 34.416 28.674 34.56 ;
    END
  END q[308]
  PIN q[309]
    DIRECTION OUTPUT ;
    USE SIGNAL ;
    PORT
      LAYER M5 ;
        RECT  28.704 34.368 28.728 34.56 ;
    END
  END q[309]
  PIN q[30]
    DIRECTION OUTPUT ;
    USE SIGNAL ;
    PORT
      LAYER M3 ;
        RECT  8.64 34.416 8.658 34.56 ;
    END
  END q[30]
  PIN q[310]
    DIRECTION OUTPUT ;
    USE SIGNAL ;
    PORT
      LAYER M3 ;
        RECT  28.8 34.416 28.818 34.56 ;
    END
  END q[310]
  PIN q[311]
    DIRECTION OUTPUT ;
    USE SIGNAL ;
    PORT
      LAYER M5 ;
        RECT  28.848 34.368 28.872 34.56 ;
    END
  END q[311]
  PIN q[312]
    DIRECTION OUTPUT ;
    USE SIGNAL ;
    PORT
      LAYER M3 ;
        RECT  28.944 34.416 28.962 34.56 ;
    END
  END q[312]
  PIN q[313]
    DIRECTION OUTPUT ;
    USE SIGNAL ;
    PORT
      LAYER M5 ;
        RECT  28.992 34.368 29.016 34.56 ;
    END
  END q[313]
  PIN q[314]
    DIRECTION OUTPUT ;
    USE SIGNAL ;
    PORT
      LAYER M3 ;
        RECT  29.088 34.416 29.106 34.56 ;
    END
  END q[314]
  PIN q[315]
    DIRECTION OUTPUT ;
    USE SIGNAL ;
    PORT
      LAYER M5 ;
        RECT  29.136 34.368 29.16 34.56 ;
    END
  END q[315]
  PIN q[316]
    DIRECTION OUTPUT ;
    USE SIGNAL ;
    PORT
      LAYER M3 ;
        RECT  29.232 34.416 29.25 34.56 ;
    END
  END q[316]
  PIN q[317]
    DIRECTION OUTPUT ;
    USE SIGNAL ;
    PORT
      LAYER M5 ;
        RECT  29.28 34.368 29.304 34.56 ;
    END
  END q[317]
  PIN q[318]
    DIRECTION OUTPUT ;
    USE SIGNAL ;
    PORT
      LAYER M3 ;
        RECT  29.376 34.416 29.394 34.56 ;
    END
  END q[318]
  PIN q[319]
    DIRECTION OUTPUT ;
    USE SIGNAL ;
    PORT
      LAYER M5 ;
        RECT  29.424 34.368 29.448 34.56 ;
    END
  END q[319]
  PIN q[31]
    DIRECTION OUTPUT ;
    USE SIGNAL ;
    PORT
      LAYER M5 ;
        RECT  8.688 34.368 8.712 34.56 ;
    END
  END q[31]
  PIN q[320]
    DIRECTION OUTPUT ;
    USE SIGNAL ;
    PORT
      LAYER M3 ;
        RECT  29.52 34.416 29.538 34.56 ;
    END
  END q[320]
  PIN q[321]
    DIRECTION OUTPUT ;
    USE SIGNAL ;
    PORT
      LAYER M5 ;
        RECT  29.568 34.368 29.592 34.56 ;
    END
  END q[321]
  PIN q[322]
    DIRECTION OUTPUT ;
    USE SIGNAL ;
    PORT
      LAYER M3 ;
        RECT  29.664 34.416 29.682 34.56 ;
    END
  END q[322]
  PIN q[323]
    DIRECTION OUTPUT ;
    USE SIGNAL ;
    PORT
      LAYER M5 ;
        RECT  29.712 34.368 29.736 34.56 ;
    END
  END q[323]
  PIN q[324]
    DIRECTION OUTPUT ;
    USE SIGNAL ;
    PORT
      LAYER M3 ;
        RECT  29.808 34.416 29.826 34.56 ;
    END
  END q[324]
  PIN q[325]
    DIRECTION OUTPUT ;
    USE SIGNAL ;
    PORT
      LAYER M5 ;
        RECT  29.856 34.368 29.88 34.56 ;
    END
  END q[325]
  PIN q[326]
    DIRECTION OUTPUT ;
    USE SIGNAL ;
    PORT
      LAYER M3 ;
        RECT  29.952 34.416 29.97 34.56 ;
    END
  END q[326]
  PIN q[327]
    DIRECTION OUTPUT ;
    USE SIGNAL ;
    PORT
      LAYER M5 ;
        RECT  30 34.368 30.024 34.56 ;
    END
  END q[327]
  PIN q[328]
    DIRECTION OUTPUT ;
    USE SIGNAL ;
    PORT
      LAYER M3 ;
        RECT  30.096 34.416 30.114 34.56 ;
    END
  END q[328]
  PIN q[329]
    DIRECTION OUTPUT ;
    USE SIGNAL ;
    PORT
      LAYER M5 ;
        RECT  30.144 34.368 30.168 34.56 ;
    END
  END q[329]
  PIN q[32]
    DIRECTION OUTPUT ;
    USE SIGNAL ;
    PORT
      LAYER M3 ;
        RECT  8.784 34.416 8.802 34.56 ;
    END
  END q[32]
  PIN q[330]
    DIRECTION OUTPUT ;
    USE SIGNAL ;
    PORT
      LAYER M3 ;
        RECT  30.24 34.416 30.258 34.56 ;
    END
  END q[330]
  PIN q[331]
    DIRECTION OUTPUT ;
    USE SIGNAL ;
    PORT
      LAYER M5 ;
        RECT  30.288 34.368 30.312 34.56 ;
    END
  END q[331]
  PIN q[332]
    DIRECTION OUTPUT ;
    USE SIGNAL ;
    PORT
      LAYER M3 ;
        RECT  30.384 34.416 30.402 34.56 ;
    END
  END q[332]
  PIN q[333]
    DIRECTION OUTPUT ;
    USE SIGNAL ;
    PORT
      LAYER M5 ;
        RECT  30.432 34.368 30.456 34.56 ;
    END
  END q[333]
  PIN q[334]
    DIRECTION OUTPUT ;
    USE SIGNAL ;
    PORT
      LAYER M3 ;
        RECT  30.528 34.416 30.546 34.56 ;
    END
  END q[334]
  PIN q[335]
    DIRECTION OUTPUT ;
    USE SIGNAL ;
    PORT
      LAYER M5 ;
        RECT  30.576 34.368 30.6 34.56 ;
    END
  END q[335]
  PIN q[336]
    DIRECTION OUTPUT ;
    USE SIGNAL ;
    PORT
      LAYER M3 ;
        RECT  30.672 34.416 30.69 34.56 ;
    END
  END q[336]
  PIN q[337]
    DIRECTION OUTPUT ;
    USE SIGNAL ;
    PORT
      LAYER M5 ;
        RECT  30.72 34.368 30.744 34.56 ;
    END
  END q[337]
  PIN q[338]
    DIRECTION OUTPUT ;
    USE SIGNAL ;
    PORT
      LAYER M3 ;
        RECT  30.816 34.416 30.834 34.56 ;
    END
  END q[338]
  PIN q[339]
    DIRECTION OUTPUT ;
    USE SIGNAL ;
    PORT
      LAYER M5 ;
        RECT  30.864 34.368 30.888 34.56 ;
    END
  END q[339]
  PIN q[33]
    DIRECTION OUTPUT ;
    USE SIGNAL ;
    PORT
      LAYER M5 ;
        RECT  8.832 34.368 8.856 34.56 ;
    END
  END q[33]
  PIN q[340]
    DIRECTION OUTPUT ;
    USE SIGNAL ;
    PORT
      LAYER M3 ;
        RECT  30.96 34.416 30.978 34.56 ;
    END
  END q[340]
  PIN q[341]
    DIRECTION OUTPUT ;
    USE SIGNAL ;
    PORT
      LAYER M5 ;
        RECT  31.008 34.368 31.032 34.56 ;
    END
  END q[341]
  PIN q[342]
    DIRECTION OUTPUT ;
    USE SIGNAL ;
    PORT
      LAYER M3 ;
        RECT  31.104 34.416 31.122 34.56 ;
    END
  END q[342]
  PIN q[343]
    DIRECTION OUTPUT ;
    USE SIGNAL ;
    PORT
      LAYER M5 ;
        RECT  31.152 34.368 31.176 34.56 ;
    END
  END q[343]
  PIN q[344]
    DIRECTION OUTPUT ;
    USE SIGNAL ;
    PORT
      LAYER M3 ;
        RECT  31.248 34.416 31.266 34.56 ;
    END
  END q[344]
  PIN q[345]
    DIRECTION OUTPUT ;
    USE SIGNAL ;
    PORT
      LAYER M5 ;
        RECT  31.296 34.368 31.32 34.56 ;
    END
  END q[345]
  PIN q[346]
    DIRECTION OUTPUT ;
    USE SIGNAL ;
    PORT
      LAYER M3 ;
        RECT  31.392 34.416 31.41 34.56 ;
    END
  END q[346]
  PIN q[347]
    DIRECTION OUTPUT ;
    USE SIGNAL ;
    PORT
      LAYER M5 ;
        RECT  31.44 34.368 31.464 34.56 ;
    END
  END q[347]
  PIN q[348]
    DIRECTION OUTPUT ;
    USE SIGNAL ;
    PORT
      LAYER M3 ;
        RECT  31.536 34.416 31.554 34.56 ;
    END
  END q[348]
  PIN q[349]
    DIRECTION OUTPUT ;
    USE SIGNAL ;
    PORT
      LAYER M5 ;
        RECT  31.584 34.368 31.608 34.56 ;
    END
  END q[349]
  PIN q[34]
    DIRECTION OUTPUT ;
    USE SIGNAL ;
    PORT
      LAYER M3 ;
        RECT  8.928 34.416 8.946 34.56 ;
    END
  END q[34]
  PIN q[350]
    DIRECTION OUTPUT ;
    USE SIGNAL ;
    PORT
      LAYER M3 ;
        RECT  31.68 34.416 31.698 34.56 ;
    END
  END q[350]
  PIN q[351]
    DIRECTION OUTPUT ;
    USE SIGNAL ;
    PORT
      LAYER M5 ;
        RECT  31.728 34.368 31.752 34.56 ;
    END
  END q[351]
  PIN q[352]
    DIRECTION OUTPUT ;
    USE SIGNAL ;
    PORT
      LAYER M3 ;
        RECT  31.824 34.416 31.842 34.56 ;
    END
  END q[352]
  PIN q[353]
    DIRECTION OUTPUT ;
    USE SIGNAL ;
    PORT
      LAYER M5 ;
        RECT  31.872 34.368 31.896 34.56 ;
    END
  END q[353]
  PIN q[354]
    DIRECTION OUTPUT ;
    USE SIGNAL ;
    PORT
      LAYER M3 ;
        RECT  31.968 34.416 31.986 34.56 ;
    END
  END q[354]
  PIN q[355]
    DIRECTION OUTPUT ;
    USE SIGNAL ;
    PORT
      LAYER M5 ;
        RECT  32.016 34.368 32.04 34.56 ;
    END
  END q[355]
  PIN q[356]
    DIRECTION OUTPUT ;
    USE SIGNAL ;
    PORT
      LAYER M3 ;
        RECT  32.112 34.416 32.13 34.56 ;
    END
  END q[356]
  PIN q[357]
    DIRECTION OUTPUT ;
    USE SIGNAL ;
    PORT
      LAYER M5 ;
        RECT  32.16 34.368 32.184 34.56 ;
    END
  END q[357]
  PIN q[358]
    DIRECTION OUTPUT ;
    USE SIGNAL ;
    PORT
      LAYER M3 ;
        RECT  32.256 34.416 32.274 34.56 ;
    END
  END q[358]
  PIN q[359]
    DIRECTION OUTPUT ;
    USE SIGNAL ;
    PORT
      LAYER M5 ;
        RECT  32.304 34.368 32.328 34.56 ;
    END
  END q[359]
  PIN q[35]
    DIRECTION OUTPUT ;
    USE SIGNAL ;
    PORT
      LAYER M5 ;
        RECT  8.976 34.368 9 34.56 ;
    END
  END q[35]
  PIN q[360]
    DIRECTION OUTPUT ;
    USE SIGNAL ;
    PORT
      LAYER M3 ;
        RECT  32.4 34.416 32.418 34.56 ;
    END
  END q[360]
  PIN q[361]
    DIRECTION OUTPUT ;
    USE SIGNAL ;
    PORT
      LAYER M5 ;
        RECT  32.448 34.368 32.472 34.56 ;
    END
  END q[361]
  PIN q[362]
    DIRECTION OUTPUT ;
    USE SIGNAL ;
    PORT
      LAYER M3 ;
        RECT  32.544 34.416 32.562 34.56 ;
    END
  END q[362]
  PIN q[363]
    DIRECTION OUTPUT ;
    USE SIGNAL ;
    PORT
      LAYER M5 ;
        RECT  32.592 34.368 32.616 34.56 ;
    END
  END q[363]
  PIN q[364]
    DIRECTION OUTPUT ;
    USE SIGNAL ;
    PORT
      LAYER M3 ;
        RECT  32.688 34.416 32.706 34.56 ;
    END
  END q[364]
  PIN q[365]
    DIRECTION OUTPUT ;
    USE SIGNAL ;
    PORT
      LAYER M5 ;
        RECT  32.736 34.368 32.76 34.56 ;
    END
  END q[365]
  PIN q[366]
    DIRECTION OUTPUT ;
    USE SIGNAL ;
    PORT
      LAYER M3 ;
        RECT  32.832 34.416 32.85 34.56 ;
    END
  END q[366]
  PIN q[367]
    DIRECTION OUTPUT ;
    USE SIGNAL ;
    PORT
      LAYER M5 ;
        RECT  32.88 34.368 32.904 34.56 ;
    END
  END q[367]
  PIN q[368]
    DIRECTION OUTPUT ;
    USE SIGNAL ;
    PORT
      LAYER M3 ;
        RECT  32.976 34.416 32.994 34.56 ;
    END
  END q[368]
  PIN q[369]
    DIRECTION OUTPUT ;
    USE SIGNAL ;
    PORT
      LAYER M5 ;
        RECT  33.024 34.368 33.048 34.56 ;
    END
  END q[369]
  PIN q[36]
    DIRECTION OUTPUT ;
    USE SIGNAL ;
    PORT
      LAYER M3 ;
        RECT  9.072 34.416 9.09 34.56 ;
    END
  END q[36]
  PIN q[370]
    DIRECTION OUTPUT ;
    USE SIGNAL ;
    PORT
      LAYER M3 ;
        RECT  33.12 34.416 33.138 34.56 ;
    END
  END q[370]
  PIN q[371]
    DIRECTION OUTPUT ;
    USE SIGNAL ;
    PORT
      LAYER M5 ;
        RECT  33.168 34.368 33.192 34.56 ;
    END
  END q[371]
  PIN q[372]
    DIRECTION OUTPUT ;
    USE SIGNAL ;
    PORT
      LAYER M3 ;
        RECT  33.264 34.416 33.282 34.56 ;
    END
  END q[372]
  PIN q[373]
    DIRECTION OUTPUT ;
    USE SIGNAL ;
    PORT
      LAYER M5 ;
        RECT  33.312 34.368 33.336 34.56 ;
    END
  END q[373]
  PIN q[374]
    DIRECTION OUTPUT ;
    USE SIGNAL ;
    PORT
      LAYER M3 ;
        RECT  33.408 34.416 33.426 34.56 ;
    END
  END q[374]
  PIN q[375]
    DIRECTION OUTPUT ;
    USE SIGNAL ;
    PORT
      LAYER M5 ;
        RECT  33.456 34.368 33.48 34.56 ;
    END
  END q[375]
  PIN q[376]
    DIRECTION OUTPUT ;
    USE SIGNAL ;
    PORT
      LAYER M3 ;
        RECT  33.552 34.416 33.57 34.56 ;
    END
  END q[376]
  PIN q[377]
    DIRECTION OUTPUT ;
    USE SIGNAL ;
    PORT
      LAYER M5 ;
        RECT  33.6 34.368 33.624 34.56 ;
    END
  END q[377]
  PIN q[378]
    DIRECTION OUTPUT ;
    USE SIGNAL ;
    PORT
      LAYER M3 ;
        RECT  33.696 34.416 33.714 34.56 ;
    END
  END q[378]
  PIN q[379]
    DIRECTION OUTPUT ;
    USE SIGNAL ;
    PORT
      LAYER M5 ;
        RECT  33.744 34.368 33.768 34.56 ;
    END
  END q[379]
  PIN q[37]
    DIRECTION OUTPUT ;
    USE SIGNAL ;
    PORT
      LAYER M5 ;
        RECT  9.12 34.368 9.144 34.56 ;
    END
  END q[37]
  PIN q[380]
    DIRECTION OUTPUT ;
    USE SIGNAL ;
    PORT
      LAYER M3 ;
        RECT  33.84 34.416 33.858 34.56 ;
    END
  END q[380]
  PIN q[381]
    DIRECTION OUTPUT ;
    USE SIGNAL ;
    PORT
      LAYER M5 ;
        RECT  33.888 34.368 33.912 34.56 ;
    END
  END q[381]
  PIN q[382]
    DIRECTION OUTPUT ;
    USE SIGNAL ;
    PORT
      LAYER M3 ;
        RECT  33.984 34.416 34.002 34.56 ;
    END
  END q[382]
  PIN q[383]
    DIRECTION OUTPUT ;
    USE SIGNAL ;
    PORT
      LAYER M5 ;
        RECT  34.032 34.368 34.056 34.56 ;
    END
  END q[383]
  PIN q[384]
    DIRECTION OUTPUT ;
    USE SIGNAL ;
    PORT
      LAYER M3 ;
        RECT  34.128 34.416 34.146 34.56 ;
    END
  END q[384]
  PIN q[385]
    DIRECTION OUTPUT ;
    USE SIGNAL ;
    PORT
      LAYER M5 ;
        RECT  34.176 34.368 34.2 34.56 ;
    END
  END q[385]
  PIN q[386]
    DIRECTION OUTPUT ;
    USE SIGNAL ;
    PORT
      LAYER M3 ;
        RECT  34.272 34.416 34.29 34.56 ;
    END
  END q[386]
  PIN q[387]
    DIRECTION OUTPUT ;
    USE SIGNAL ;
    PORT
      LAYER M5 ;
        RECT  34.32 34.368 34.344 34.56 ;
    END
  END q[387]
  PIN q[388]
    DIRECTION OUTPUT ;
    USE SIGNAL ;
    PORT
      LAYER M3 ;
        RECT  34.416 34.416 34.434 34.56 ;
    END
  END q[388]
  PIN q[389]
    DIRECTION OUTPUT ;
    USE SIGNAL ;
    PORT
      LAYER M5 ;
        RECT  34.464 34.368 34.488 34.56 ;
    END
  END q[389]
  PIN q[38]
    DIRECTION OUTPUT ;
    USE SIGNAL ;
    PORT
      LAYER M3 ;
        RECT  9.216 34.416 9.234 34.56 ;
    END
  END q[38]
  PIN q[390]
    DIRECTION OUTPUT ;
    USE SIGNAL ;
    PORT
      LAYER M3 ;
        RECT  34.56 34.416 34.578 34.56 ;
    END
  END q[390]
  PIN q[391]
    DIRECTION OUTPUT ;
    USE SIGNAL ;
    PORT
      LAYER M5 ;
        RECT  34.608 34.368 34.632 34.56 ;
    END
  END q[391]
  PIN q[392]
    DIRECTION OUTPUT ;
    USE SIGNAL ;
    PORT
      LAYER M3 ;
        RECT  34.704 34.416 34.722 34.56 ;
    END
  END q[392]
  PIN q[393]
    DIRECTION OUTPUT ;
    USE SIGNAL ;
    PORT
      LAYER M5 ;
        RECT  34.752 34.368 34.776 34.56 ;
    END
  END q[393]
  PIN q[394]
    DIRECTION OUTPUT ;
    USE SIGNAL ;
    PORT
      LAYER M3 ;
        RECT  34.848 34.416 34.866 34.56 ;
    END
  END q[394]
  PIN q[395]
    DIRECTION OUTPUT ;
    USE SIGNAL ;
    PORT
      LAYER M5 ;
        RECT  34.896 34.368 34.92 34.56 ;
    END
  END q[395]
  PIN q[396]
    DIRECTION OUTPUT ;
    USE SIGNAL ;
    PORT
      LAYER M3 ;
        RECT  34.992 34.416 35.01 34.56 ;
    END
  END q[396]
  PIN q[397]
    DIRECTION OUTPUT ;
    USE SIGNAL ;
    PORT
      LAYER M5 ;
        RECT  35.04 34.368 35.064 34.56 ;
    END
  END q[397]
  PIN q[398]
    DIRECTION OUTPUT ;
    USE SIGNAL ;
    PORT
      LAYER M3 ;
        RECT  35.136 34.416 35.154 34.56 ;
    END
  END q[398]
  PIN q[399]
    DIRECTION OUTPUT ;
    USE SIGNAL ;
    PORT
      LAYER M5 ;
        RECT  35.184 34.368 35.208 34.56 ;
    END
  END q[399]
  PIN q[39]
    DIRECTION OUTPUT ;
    USE SIGNAL ;
    PORT
      LAYER M5 ;
        RECT  9.264 34.368 9.288 34.56 ;
    END
  END q[39]
  PIN q[3]
    DIRECTION OUTPUT ;
    USE SIGNAL ;
    PORT
      LAYER M5 ;
        RECT  6.672 34.368 6.696 34.56 ;
    END
  END q[3]
  PIN q[400]
    DIRECTION OUTPUT ;
    USE SIGNAL ;
    PORT
      LAYER M3 ;
        RECT  35.28 34.416 35.298 34.56 ;
    END
  END q[400]
  PIN q[401]
    DIRECTION OUTPUT ;
    USE SIGNAL ;
    PORT
      LAYER M5 ;
        RECT  35.328 34.368 35.352 34.56 ;
    END
  END q[401]
  PIN q[402]
    DIRECTION OUTPUT ;
    USE SIGNAL ;
    PORT
      LAYER M3 ;
        RECT  35.424 34.416 35.442 34.56 ;
    END
  END q[402]
  PIN q[403]
    DIRECTION OUTPUT ;
    USE SIGNAL ;
    PORT
      LAYER M5 ;
        RECT  35.472 34.368 35.496 34.56 ;
    END
  END q[403]
  PIN q[404]
    DIRECTION OUTPUT ;
    USE SIGNAL ;
    PORT
      LAYER M3 ;
        RECT  35.568 34.416 35.586 34.56 ;
    END
  END q[404]
  PIN q[405]
    DIRECTION OUTPUT ;
    USE SIGNAL ;
    PORT
      LAYER M5 ;
        RECT  35.616 34.368 35.64 34.56 ;
    END
  END q[405]
  PIN q[406]
    DIRECTION OUTPUT ;
    USE SIGNAL ;
    PORT
      LAYER M3 ;
        RECT  35.712 34.416 35.73 34.56 ;
    END
  END q[406]
  PIN q[407]
    DIRECTION OUTPUT ;
    USE SIGNAL ;
    PORT
      LAYER M5 ;
        RECT  35.76 34.368 35.784 34.56 ;
    END
  END q[407]
  PIN q[40]
    DIRECTION OUTPUT ;
    USE SIGNAL ;
    PORT
      LAYER M3 ;
        RECT  9.36 34.416 9.378 34.56 ;
    END
  END q[40]
  PIN q[41]
    DIRECTION OUTPUT ;
    USE SIGNAL ;
    PORT
      LAYER M5 ;
        RECT  9.408 34.368 9.432 34.56 ;
    END
  END q[41]
  PIN q[42]
    DIRECTION OUTPUT ;
    USE SIGNAL ;
    PORT
      LAYER M3 ;
        RECT  9.504 34.416 9.522 34.56 ;
    END
  END q[42]
  PIN q[43]
    DIRECTION OUTPUT ;
    USE SIGNAL ;
    PORT
      LAYER M5 ;
        RECT  9.552 34.368 9.576 34.56 ;
    END
  END q[43]
  PIN q[44]
    DIRECTION OUTPUT ;
    USE SIGNAL ;
    PORT
      LAYER M3 ;
        RECT  9.648 34.416 9.666 34.56 ;
    END
  END q[44]
  PIN q[45]
    DIRECTION OUTPUT ;
    USE SIGNAL ;
    PORT
      LAYER M5 ;
        RECT  9.696 34.368 9.72 34.56 ;
    END
  END q[45]
  PIN q[46]
    DIRECTION OUTPUT ;
    USE SIGNAL ;
    PORT
      LAYER M3 ;
        RECT  9.792 34.416 9.81 34.56 ;
    END
  END q[46]
  PIN q[47]
    DIRECTION OUTPUT ;
    USE SIGNAL ;
    PORT
      LAYER M5 ;
        RECT  9.84 34.368 9.864 34.56 ;
    END
  END q[47]
  PIN q[48]
    DIRECTION OUTPUT ;
    USE SIGNAL ;
    PORT
      LAYER M3 ;
        RECT  9.936 34.416 9.954 34.56 ;
    END
  END q[48]
  PIN q[49]
    DIRECTION OUTPUT ;
    USE SIGNAL ;
    PORT
      LAYER M5 ;
        RECT  9.984 34.368 10.008 34.56 ;
    END
  END q[49]
  PIN q[4]
    DIRECTION OUTPUT ;
    USE SIGNAL ;
    PORT
      LAYER M3 ;
        RECT  6.768 34.416 6.786 34.56 ;
    END
  END q[4]
  PIN q[50]
    DIRECTION OUTPUT ;
    USE SIGNAL ;
    PORT
      LAYER M3 ;
        RECT  10.08 34.416 10.098 34.56 ;
    END
  END q[50]
  PIN q[51]
    DIRECTION OUTPUT ;
    USE SIGNAL ;
    PORT
      LAYER M5 ;
        RECT  10.128 34.368 10.152 34.56 ;
    END
  END q[51]
  PIN q[52]
    DIRECTION OUTPUT ;
    USE SIGNAL ;
    PORT
      LAYER M3 ;
        RECT  10.224 34.416 10.242 34.56 ;
    END
  END q[52]
  PIN q[53]
    DIRECTION OUTPUT ;
    USE SIGNAL ;
    PORT
      LAYER M5 ;
        RECT  10.272 34.368 10.296 34.56 ;
    END
  END q[53]
  PIN q[54]
    DIRECTION OUTPUT ;
    USE SIGNAL ;
    PORT
      LAYER M3 ;
        RECT  10.368 34.416 10.386 34.56 ;
    END
  END q[54]
  PIN q[55]
    DIRECTION OUTPUT ;
    USE SIGNAL ;
    PORT
      LAYER M5 ;
        RECT  10.416 34.368 10.44 34.56 ;
    END
  END q[55]
  PIN q[56]
    DIRECTION OUTPUT ;
    USE SIGNAL ;
    PORT
      LAYER M3 ;
        RECT  10.512 34.416 10.53 34.56 ;
    END
  END q[56]
  PIN q[57]
    DIRECTION OUTPUT ;
    USE SIGNAL ;
    PORT
      LAYER M5 ;
        RECT  10.56 34.368 10.584 34.56 ;
    END
  END q[57]
  PIN q[58]
    DIRECTION OUTPUT ;
    USE SIGNAL ;
    PORT
      LAYER M3 ;
        RECT  10.656 34.416 10.674 34.56 ;
    END
  END q[58]
  PIN q[59]
    DIRECTION OUTPUT ;
    USE SIGNAL ;
    PORT
      LAYER M5 ;
        RECT  10.704 34.368 10.728 34.56 ;
    END
  END q[59]
  PIN q[5]
    DIRECTION OUTPUT ;
    USE SIGNAL ;
    PORT
      LAYER M5 ;
        RECT  6.816 34.368 6.84 34.56 ;
    END
  END q[5]
  PIN q[60]
    DIRECTION OUTPUT ;
    USE SIGNAL ;
    PORT
      LAYER M3 ;
        RECT  10.8 34.416 10.818 34.56 ;
    END
  END q[60]
  PIN q[61]
    DIRECTION OUTPUT ;
    USE SIGNAL ;
    PORT
      LAYER M5 ;
        RECT  10.848 34.368 10.872 34.56 ;
    END
  END q[61]
  PIN q[62]
    DIRECTION OUTPUT ;
    USE SIGNAL ;
    PORT
      LAYER M3 ;
        RECT  10.944 34.416 10.962 34.56 ;
    END
  END q[62]
  PIN q[63]
    DIRECTION OUTPUT ;
    USE SIGNAL ;
    PORT
      LAYER M5 ;
        RECT  10.992 34.368 11.016 34.56 ;
    END
  END q[63]
  PIN q[64]
    DIRECTION OUTPUT ;
    USE SIGNAL ;
    PORT
      LAYER M3 ;
        RECT  11.088 34.416 11.106 34.56 ;
    END
  END q[64]
  PIN q[65]
    DIRECTION OUTPUT ;
    USE SIGNAL ;
    PORT
      LAYER M5 ;
        RECT  11.136 34.368 11.16 34.56 ;
    END
  END q[65]
  PIN q[66]
    DIRECTION OUTPUT ;
    USE SIGNAL ;
    PORT
      LAYER M3 ;
        RECT  11.232 34.416 11.25 34.56 ;
    END
  END q[66]
  PIN q[67]
    DIRECTION OUTPUT ;
    USE SIGNAL ;
    PORT
      LAYER M5 ;
        RECT  11.28 34.368 11.304 34.56 ;
    END
  END q[67]
  PIN q[68]
    DIRECTION OUTPUT ;
    USE SIGNAL ;
    PORT
      LAYER M3 ;
        RECT  11.376 34.416 11.394 34.56 ;
    END
  END q[68]
  PIN q[69]
    DIRECTION OUTPUT ;
    USE SIGNAL ;
    PORT
      LAYER M5 ;
        RECT  11.424 34.368 11.448 34.56 ;
    END
  END q[69]
  PIN q[6]
    DIRECTION OUTPUT ;
    USE SIGNAL ;
    PORT
      LAYER M3 ;
        RECT  6.912 34.416 6.93 34.56 ;
    END
  END q[6]
  PIN q[70]
    DIRECTION OUTPUT ;
    USE SIGNAL ;
    PORT
      LAYER M3 ;
        RECT  11.52 34.416 11.538 34.56 ;
    END
  END q[70]
  PIN q[71]
    DIRECTION OUTPUT ;
    USE SIGNAL ;
    PORT
      LAYER M5 ;
        RECT  11.568 34.368 11.592 34.56 ;
    END
  END q[71]
  PIN q[72]
    DIRECTION OUTPUT ;
    USE SIGNAL ;
    PORT
      LAYER M3 ;
        RECT  11.664 34.416 11.682 34.56 ;
    END
  END q[72]
  PIN q[73]
    DIRECTION OUTPUT ;
    USE SIGNAL ;
    PORT
      LAYER M5 ;
        RECT  11.712 34.368 11.736 34.56 ;
    END
  END q[73]
  PIN q[74]
    DIRECTION OUTPUT ;
    USE SIGNAL ;
    PORT
      LAYER M3 ;
        RECT  11.808 34.416 11.826 34.56 ;
    END
  END q[74]
  PIN q[75]
    DIRECTION OUTPUT ;
    USE SIGNAL ;
    PORT
      LAYER M5 ;
        RECT  11.856 34.368 11.88 34.56 ;
    END
  END q[75]
  PIN q[76]
    DIRECTION OUTPUT ;
    USE SIGNAL ;
    PORT
      LAYER M3 ;
        RECT  11.952 34.416 11.97 34.56 ;
    END
  END q[76]
  PIN q[77]
    DIRECTION OUTPUT ;
    USE SIGNAL ;
    PORT
      LAYER M5 ;
        RECT  12 34.368 12.024 34.56 ;
    END
  END q[77]
  PIN q[78]
    DIRECTION OUTPUT ;
    USE SIGNAL ;
    PORT
      LAYER M3 ;
        RECT  12.096 34.416 12.114 34.56 ;
    END
  END q[78]
  PIN q[79]
    DIRECTION OUTPUT ;
    USE SIGNAL ;
    PORT
      LAYER M5 ;
        RECT  12.144 34.368 12.168 34.56 ;
    END
  END q[79]
  PIN q[7]
    DIRECTION OUTPUT ;
    USE SIGNAL ;
    PORT
      LAYER M5 ;
        RECT  6.96 34.368 6.984 34.56 ;
    END
  END q[7]
  PIN q[80]
    DIRECTION OUTPUT ;
    USE SIGNAL ;
    PORT
      LAYER M3 ;
        RECT  12.24 34.416 12.258 34.56 ;
    END
  END q[80]
  PIN q[81]
    DIRECTION OUTPUT ;
    USE SIGNAL ;
    PORT
      LAYER M5 ;
        RECT  12.288 34.368 12.312 34.56 ;
    END
  END q[81]
  PIN q[82]
    DIRECTION OUTPUT ;
    USE SIGNAL ;
    PORT
      LAYER M3 ;
        RECT  12.384 34.416 12.402 34.56 ;
    END
  END q[82]
  PIN q[83]
    DIRECTION OUTPUT ;
    USE SIGNAL ;
    PORT
      LAYER M5 ;
        RECT  12.432 34.368 12.456 34.56 ;
    END
  END q[83]
  PIN q[84]
    DIRECTION OUTPUT ;
    USE SIGNAL ;
    PORT
      LAYER M3 ;
        RECT  12.528 34.416 12.546 34.56 ;
    END
  END q[84]
  PIN q[85]
    DIRECTION OUTPUT ;
    USE SIGNAL ;
    PORT
      LAYER M5 ;
        RECT  12.576 34.368 12.6 34.56 ;
    END
  END q[85]
  PIN q[86]
    DIRECTION OUTPUT ;
    USE SIGNAL ;
    PORT
      LAYER M3 ;
        RECT  12.672 34.416 12.69 34.56 ;
    END
  END q[86]
  PIN q[87]
    DIRECTION OUTPUT ;
    USE SIGNAL ;
    PORT
      LAYER M5 ;
        RECT  12.72 34.368 12.744 34.56 ;
    END
  END q[87]
  PIN q[88]
    DIRECTION OUTPUT ;
    USE SIGNAL ;
    PORT
      LAYER M3 ;
        RECT  12.816 34.416 12.834 34.56 ;
    END
  END q[88]
  PIN q[89]
    DIRECTION OUTPUT ;
    USE SIGNAL ;
    PORT
      LAYER M5 ;
        RECT  12.864 34.368 12.888 34.56 ;
    END
  END q[89]
  PIN q[8]
    DIRECTION OUTPUT ;
    USE SIGNAL ;
    PORT
      LAYER M3 ;
        RECT  7.056 34.416 7.074 34.56 ;
    END
  END q[8]
  PIN q[90]
    DIRECTION OUTPUT ;
    USE SIGNAL ;
    PORT
      LAYER M3 ;
        RECT  12.96 34.416 12.978 34.56 ;
    END
  END q[90]
  PIN q[91]
    DIRECTION OUTPUT ;
    USE SIGNAL ;
    PORT
      LAYER M5 ;
        RECT  13.008 34.368 13.032 34.56 ;
    END
  END q[91]
  PIN q[92]
    DIRECTION OUTPUT ;
    USE SIGNAL ;
    PORT
      LAYER M3 ;
        RECT  13.104 34.416 13.122 34.56 ;
    END
  END q[92]
  PIN q[93]
    DIRECTION OUTPUT ;
    USE SIGNAL ;
    PORT
      LAYER M5 ;
        RECT  13.152 34.368 13.176 34.56 ;
    END
  END q[93]
  PIN q[94]
    DIRECTION OUTPUT ;
    USE SIGNAL ;
    PORT
      LAYER M3 ;
        RECT  13.248 34.416 13.266 34.56 ;
    END
  END q[94]
  PIN q[95]
    DIRECTION OUTPUT ;
    USE SIGNAL ;
    PORT
      LAYER M5 ;
        RECT  13.296 34.368 13.32 34.56 ;
    END
  END q[95]
  PIN q[96]
    DIRECTION OUTPUT ;
    USE SIGNAL ;
    PORT
      LAYER M3 ;
        RECT  13.392 34.416 13.41 34.56 ;
    END
  END q[96]
  PIN q[97]
    DIRECTION OUTPUT ;
    USE SIGNAL ;
    PORT
      LAYER M5 ;
        RECT  13.44 34.368 13.464 34.56 ;
    END
  END q[97]
  PIN q[98]
    DIRECTION OUTPUT ;
    USE SIGNAL ;
    PORT
      LAYER M3 ;
        RECT  13.536 34.416 13.554 34.56 ;
    END
  END q[98]
  PIN q[99]
    DIRECTION OUTPUT ;
    USE SIGNAL ;
    PORT
      LAYER M5 ;
        RECT  13.584 34.368 13.608 34.56 ;
    END
  END q[99]
  PIN q[9]
    DIRECTION OUTPUT ;
    USE SIGNAL ;
    PORT
      LAYER M5 ;
        RECT  7.104 34.368 7.128 34.56 ;
    END
  END q[9]
  PIN rst_n
    DIRECTION INPUT ;
    USE SIGNAL ;
    PORT
      LAYER M4 ;
        RECT  0 14.88 0.192 14.904 ;
    END
    PORT
      LAYER M4 ;
        RECT  0.156 14.88 0.245 14.904 ;
    END
  END rst_n
  PIN VDD
    DIRECTION INOUT ;
    USE POWER ;
    PORT
      LAYER M5 ;
        RECT  40.392 2.151 40.512 32.409 ;
        RECT  34.992 2.151 35.112 32.409 ;
        RECT  29.592 2.151 29.712 32.409 ;
        RECT  24.192 2.151 24.312 32.409 ;
        RECT  18.792 2.151 18.912 32.409 ;
        RECT  13.392 2.151 13.512 32.409 ;
        RECT  7.992 2.151 8.112 32.409 ;
        RECT  2.592 2.151 2.712 32.409 ;
    END
  END VDD
  PIN VSS
    DIRECTION INOUT ;
    USE GROUND ;
    PORT
      LAYER M5 ;
        RECT  40.2 2.137 40.32 32.423 ;
        RECT  34.8 2.137 34.92 32.423 ;
        RECT  29.4 2.137 29.52 32.423 ;
        RECT  24 2.137 24.12 32.423 ;
        RECT  18.6 2.137 18.72 32.423 ;
        RECT  13.2 2.137 13.32 32.423 ;
        RECT  7.8 2.137 7.92 32.423 ;
        RECT  2.4 2.137 2.52 32.423 ;
    END
  END VSS
  # OT_OBS_CLOSED layer=M5 d_um=1.536 added=14
  OBS
    LAYER RVTN ;
     RECT  2.16 2.16 41.04 2.295 ;
     RECT  2.16 2.565 41.04 2.835 ;
     RECT  2.16 3.105 41.04 3.375 ;
     RECT  2.16 3.645 41.04 3.915 ;
     RECT  2.16 4.185 41.04 4.455 ;
     RECT  2.16 4.725 41.04 4.995 ;
     RECT  2.16 5.265 41.04 5.535 ;
     RECT  2.16 5.805 41.04 6.075 ;
     RECT  2.16 6.345 41.04 6.615 ;
     RECT  2.16 6.885 41.04 7.155 ;
     RECT  2.16 7.425 41.04 7.695 ;
     RECT  2.16 7.965 41.04 8.235 ;
     RECT  2.16 8.505 41.04 8.775 ;
     RECT  2.16 9.045 41.04 9.315 ;
     RECT  2.16 9.585 41.04 9.855 ;
     RECT  2.16 10.125 41.04 10.395 ;
     RECT  2.16 10.665 41.04 10.935 ;
     RECT  2.16 11.205 41.04 11.475 ;
     RECT  2.16 11.745 41.04 12.015 ;
     RECT  2.16 12.285 41.04 12.555 ;
     RECT  2.16 12.825 41.04 13.095 ;
     RECT  2.16 13.365 41.04 13.635 ;
     RECT  2.16 13.905 41.04 14.175 ;
     RECT  2.16 14.445 41.04 14.715 ;
     RECT  2.16 14.985 41.04 15.255 ;
     RECT  2.16 15.525 41.04 15.795 ;
     RECT  2.16 16.065 41.04 16.335 ;
     RECT  2.16 16.605 41.04 16.875 ;
     RECT  2.16 17.145 41.04 17.415 ;
     RECT  2.16 17.685 41.04 17.955 ;
     RECT  2.16 18.225 41.04 18.495 ;
     RECT  2.16 18.765 41.04 19.035 ;
     RECT  2.16 19.305 41.04 19.575 ;
     RECT  2.16 19.845 41.04 20.115 ;
     RECT  2.16 20.385 41.04 20.655 ;
     RECT  2.16 20.925 41.04 21.195 ;
     RECT  2.16 21.465 41.04 21.735 ;
     RECT  2.16 22.005 41.04 22.275 ;
     RECT  2.16 22.545 41.04 22.815 ;
     RECT  2.16 23.085 41.04 23.355 ;
     RECT  2.16 23.625 41.04 23.895 ;
     RECT  2.16 24.165 41.04 24.435 ;
     RECT  2.16 24.705 41.04 24.975 ;
     RECT  2.16 25.245 41.04 25.515 ;
     RECT  2.16 25.785 41.04 26.055 ;
     RECT  2.16 26.325 41.04 26.595 ;
     RECT  2.16 26.865 41.04 27.135 ;
     RECT  2.16 27.405 41.04 27.675 ;
     RECT  2.16 27.945 41.04 28.215 ;
     RECT  2.16 28.485 41.04 28.755 ;
     RECT  2.16 29.025 41.04 29.295 ;
     RECT  2.16 29.565 41.04 29.835 ;
     RECT  2.16 30.105 41.04 30.375 ;
     RECT  2.16 30.645 41.04 30.915 ;
     RECT  2.16 31.185 41.04 31.455 ;
     RECT  2.16 31.725 41.04 31.995 ;
     RECT  2.16 32.265 41.04 32.4 ;
    LAYER RVTP ;
     RECT  2.16 2.295 41.04 2.565 ;
     RECT  2.16 2.835 41.04 3.105 ;
     RECT  2.16 3.375 41.04 3.645 ;
     RECT  2.16 3.915 41.04 4.185 ;
     RECT  2.16 4.455 41.04 4.725 ;
     RECT  2.16 4.995 41.04 5.265 ;
     RECT  2.16 5.535 41.04 5.805 ;
     RECT  2.16 6.075 41.04 6.345 ;
     RECT  2.16 6.615 41.04 6.885 ;
     RECT  2.16 7.155 41.04 7.425 ;
     RECT  2.16 7.695 41.04 7.965 ;
     RECT  2.16 8.235 41.04 8.505 ;
     RECT  2.16 8.775 41.04 9.045 ;
     RECT  2.16 9.315 41.04 9.585 ;
     RECT  2.16 9.855 41.04 10.125 ;
     RECT  2.16 10.395 41.04 10.665 ;
     RECT  2.16 10.935 41.04 11.205 ;
     RECT  2.16 11.475 41.04 11.745 ;
     RECT  2.16 12.015 41.04 12.285 ;
     RECT  2.16 12.555 41.04 12.825 ;
     RECT  2.16 13.095 41.04 13.365 ;
     RECT  2.16 13.635 41.04 13.905 ;
     RECT  2.16 14.175 41.04 14.445 ;
     RECT  2.16 14.715 41.04 14.985 ;
     RECT  2.16 15.255 41.04 15.525 ;
     RECT  2.16 15.795 41.04 16.065 ;
     RECT  2.16 16.335 41.04 16.605 ;
     RECT  2.16 16.875 41.04 17.145 ;
     RECT  2.16 17.415 41.04 17.685 ;
     RECT  2.16 17.955 41.04 18.225 ;
     RECT  2.16 18.495 41.04 18.765 ;
     RECT  2.16 19.035 41.04 19.305 ;
     RECT  2.16 19.575 41.04 19.845 ;
     RECT  2.16 20.115 41.04 20.385 ;
     RECT  2.16 20.655 41.04 20.925 ;
     RECT  2.16 21.195 41.04 21.465 ;
     RECT  2.16 21.735 41.04 22.005 ;
     RECT  2.16 22.275 41.04 22.545 ;
     RECT  2.16 22.815 41.04 23.085 ;
     RECT  2.16 23.355 41.04 23.625 ;
     RECT  2.16 23.895 41.04 24.165 ;
     RECT  2.16 24.435 41.04 24.705 ;
     RECT  2.16 24.975 41.04 25.245 ;
     RECT  2.16 25.515 41.04 25.785 ;
     RECT  2.16 26.055 41.04 26.325 ;
     RECT  2.16 26.595 41.04 26.865 ;
     RECT  2.16 27.135 41.04 27.405 ;
     RECT  2.16 27.675 41.04 27.945 ;
     RECT  2.16 28.215 41.04 28.485 ;
     RECT  2.16 28.755 41.04 29.025 ;
     RECT  2.16 29.295 41.04 29.565 ;
     RECT  2.16 29.835 41.04 30.105 ;
     RECT  2.16 30.375 41.04 30.645 ;
     RECT  2.16 30.915 41.04 31.185 ;
     RECT  2.16 31.455 41.04 31.725 ;
     RECT  2.16 31.995 41.04 32.265 ;
    LAYER M1 ;
     RECT  2.16 2.151 41.04 32.409 ;
    LAYER M2 ;
     RECT  0.211 15.192 2.16 15.21 ;
     RECT  2.16 2.151 5.467 32.409 ;
     RECT  5.467 2.151 6.619 32.454 ;
     RECT  6.619 2.151 6.755 33.066 ;
     RECT  6.439 0.576 7.511 0.594 ;
     RECT  6.755 2.151 7.735 32.409 ;
     RECT  7.735 1.728 7.915 32.409 ;
     RECT  7.915 1.728 8.203 32.49 ;
     RECT  7.627 0.144 8.447 0.162 ;
     RECT  8.203 1.728 8.591 33.066 ;
     RECT  9.211 0.144 9.419 0.162 ;
     RECT  8.591 2.151 10.291 33.066 ;
     RECT  10.183 0.144 10.363 0.162 ;
     RECT  10.291 2.106 10.391 33.066 ;
     RECT  10.363 0.144 10.679 0.324 ;
     RECT  10.391 2.106 10.823 32.409 ;
     RECT  10.679 0.144 11.219 0.162 ;
     RECT  10.823 2.151 11.767 32.409 ;
     RECT  11.767 2.151 11.947 32.454 ;
     RECT  11.947 1.728 12.191 32.454 ;
     RECT  12.191 2.151 12.235 32.454 ;
     RECT  12.235 2.151 12.371 33.066 ;
     RECT  12.371 2.151 13.531 32.409 ;
     RECT  13.531 2.151 13.667 33.066 ;
     RECT  12.667 0.144 13.927 0.162 ;
     RECT  13.927 0.144 14.099 0.63 ;
     RECT  13.667 2.151 14.107 32.409 ;
     RECT  14.099 0.144 14.279 0.162 ;
     RECT  14.107 1.728 14.459 32.409 ;
     RECT  14.459 2.151 15.187 32.409 ;
     RECT  15.403 0.144 15.691 0.162 ;
     RECT  15.691 0.144 15.791 0.234 ;
     RECT  15.791 0.144 16.295 0.162 ;
     RECT  15.187 2.151 16.943 33.066 ;
     RECT  16.943 2.151 17.627 32.598 ;
     RECT  17.131 0.144 17.959 0.162 ;
     RECT  17.959 0.144 18.247 0.234 ;
     RECT  17.627 2.151 18.355 32.409 ;
     RECT  18.247 0.144 18.391 0.324 ;
     RECT  18.355 2.106 18.391 32.409 ;
     RECT  18.391 0.144 18.527 0.396 ;
     RECT  18.527 0.144 18.743 0.162 ;
     RECT  18.391 2.106 19.003 32.49 ;
     RECT  19.003 2.106 19.103 32.598 ;
     RECT  19.103 2.106 19.139 32.409 ;
     RECT  19.723 0.144 19.795 0.162 ;
     RECT  19.795 0.144 19.895 0.234 ;
     RECT  20.371 33.201 20.471 33.219 ;
     RECT  19.895 0.144 20.615 0.162 ;
     RECT  23.035 33.822 23.135 33.84 ;
     RECT  19.139 2.151 23.323 32.409 ;
     RECT  23.323 1.728 23.459 32.409 ;
     RECT  22.315 0.144 24.071 0.162 ;
     RECT  23.459 2.151 24.475 32.409 ;
     RECT  24.475 1.728 24.611 32.832 ;
     RECT  24.611 1.728 24.719 32.409 ;
     RECT  24.719 2.151 25.483 32.409 ;
     RECT  25.483 2.151 25.583 32.454 ;
     RECT  24.799 0.144 25.799 0.162 ;
     RECT  26.599 0.576 26.807 0.594 ;
     RECT  26.923 34.398 26.959 34.416 ;
     RECT  26.959 34.398 27.059 34.488 ;
     RECT  27.355 0.144 28.147 0.162 ;
     RECT  25.583 2.151 28.327 32.409 ;
     RECT  28.147 0.144 28.391 0.234 ;
     RECT  28.327 2.106 28.939 32.409 ;
     RECT  28.939 2.106 29.039 32.598 ;
     RECT  29.039 2.106 29.327 32.49 ;
     RECT  29.327 2.151 29.543 32.49 ;
     RECT  28.391 0.144 29.803 0.162 ;
     RECT  29.543 2.151 29.939 32.454 ;
     RECT  29.803 0.144 30.083 0.234 ;
     RECT  30.083 0.144 30.479 0.162 ;
     RECT  29.939 2.151 30.739 32.409 ;
     RECT  30.739 2.106 31.199 32.409 ;
     RECT  31.199 2.151 32.107 32.409 ;
     RECT  32.215 33.741 32.423 33.759 ;
     RECT  32.107 2.151 33.547 32.454 ;
     RECT  33.547 1.728 33.647 32.454 ;
     RECT  33.647 2.151 34.267 32.454 ;
     RECT  34.267 2.151 34.555 32.49 ;
     RECT  34.555 2.151 34.771 33.066 ;
     RECT  34.771 1.728 34.871 33.066 ;
     RECT  34.871 2.151 35.231 33.066 ;
     RECT  35.231 2.151 35.375 32.598 ;
     RECT  35.375 2.151 35.555 32.526 ;
     RECT  31.639 0.144 35.663 0.162 ;
     RECT  35.555 2.151 37.067 32.454 ;
     RECT  37.067 2.151 41.04 32.409 ;
    LAYER M3 ;
     RECT  6.48 0.108 35.73 0.571 ;
     RECT  6.408 0.571 35.73 1.723 ;
     RECT  6.408 1.723 35.838 2.203 ;
     RECT  6.3 2.203 35.838 2.299 ;
     RECT  36.576 2.263 36.594 2.299 ;
     RECT  2.415 2.143 2.505 2.413 ;
     RECT  40.215 2.143 40.305 2.413 ;
     RECT  6.3 2.299 36.594 2.641 ;
     RECT  5.976 2.641 36.594 2.803 ;
     RECT  5.904 2.803 36.594 3.181 ;
     RECT  5.832 3.181 36.594 6.385 ;
     RECT  5.544 6.385 36.594 6.719 ;
     RECT  5.76 6.719 36.594 7.771 ;
     RECT  5.22 7.771 36.594 12.451 ;
     RECT  5.22 12.451 36.846 12.551 ;
     RECT  5.22 12.551 36.594 13.981 ;
     RECT  5.22 13.981 36.774 14.521 ;
     RECT  5.22 14.521 36.954 15.061 ;
     RECT  0.216 14.875 0.234 15.215 ;
     RECT  5.22 15.061 37.134 16.141 ;
     RECT  5.22 16.141 37.35 31.379 ;
     RECT  5.688 31.379 37.35 31.801 ;
     RECT  5.688 31.801 37.854 31.919 ;
     RECT  5.688 31.919 37.314 32.063 ;
     RECT  2.415 2.413 2.697 32.147 ;
     RECT  40.215 2.413 40.497 32.147 ;
     RECT  36.576 32.063 37.314 32.225 ;
     RECT  5.688 32.063 35.73 32.333 ;
     RECT  2.415 32.147 2.505 32.417 ;
     RECT  40.215 32.147 40.305 32.417 ;
     RECT  37.044 32.225 37.314 32.429 ;
     RECT  5.472 32.341 5.49 32.459 ;
     RECT  37.044 32.429 37.062 32.459 ;
     RECT  6.372 32.333 35.73 32.525 ;
     RECT  6.444 32.525 35.73 33.101 ;
     RECT  6.48 33.101 35.73 34.428 ;
     RECT  26.964 34.428 27.054 34.493 ;
    LAYER M4 ;
     RECT  0.229 10.656 2.408 10.68 ;
     RECT  2.408 2.148 2.512 32.412 ;
     RECT  2.512 2.418 2.704 32.142 ;
     RECT  5.713 31.824 6.361 31.848 ;
     RECT  6.361 31.824 6.433 32.52 ;
     RECT  6.289 2.208 6.577 2.232 ;
     RECT  6.577 1.728 6.649 2.232 ;
     RECT  6.037 7.44 6.829 7.464 ;
     RECT  6.433 31.824 6.865 33.096 ;
     RECT  6.829 6.864 7.045 7.464 ;
     RECT  6.901 8.496 7.045 8.52 ;
     RECT  6.893 29.664 7.045 29.688 ;
     RECT  7.093 9.648 7.333 9.672 ;
     RECT  2.704 10.656 7.333 10.68 ;
     RECT  7.333 9.648 7.381 10.68 ;
     RECT  7.381 9.648 7.429 11.352 ;
     RECT  6.865 31.824 7.429 33.672 ;
     RECT  6.649 1.728 7.477 2.28 ;
     RECT  7.045 28.752 7.477 29.688 ;
     RECT  7.477 28.32 7.513 30.216 ;
     RECT  6.397 0.576 7.571 0.6 ;
     RECT  7.429 9.648 7.573 11.544 ;
     RECT  7.261 12.768 7.573 12.792 ;
     RECT  7.513 28.32 7.573 30.312 ;
     RECT  7.429 31.344 7.573 33.672 ;
     RECT  6.865 3.984 7.649 4.008 ;
     RECT  7.477 1.728 7.808 2.856 ;
     RECT  7.649 3.984 7.808 4.584 ;
     RECT  7.045 6.864 7.808 8.52 ;
     RECT  7.573 9.648 7.808 12.792 ;
     RECT  7.573 28.32 7.808 33.672 ;
     RECT  7.808 1.728 7.859 33.672 ;
     RECT  7.859 1.728 8.104 33.048 ;
     RECT  8.104 9.936 8.129 14.136 ;
     RECT  8.104 1.728 8.291 1.8 ;
     RECT  7.957 0.288 8.339 0.312 ;
     RECT  8.104 26.544 8.387 33.048 ;
     RECT  8.387 26.544 8.453 28.536 ;
     RECT  8.387 29.76 8.531 32.52 ;
     RECT  8.104 2.784 8.561 6.264 ;
     RECT  8.533 0.576 8.633 0.6 ;
     RECT  8.129 12 8.849 14.136 ;
     RECT  8.561 2.832 8.893 6.264 ;
     RECT  8.849 12.528 9.011 14.136 ;
     RECT  8.453 27.84 9.029 28.536 ;
     RECT  9.011 12.528 9.059 12.6 ;
     RECT  8.893 5.712 9.107 6.264 ;
     RECT  8.104 7.392 9.145 8.52 ;
     RECT  9.107 6.24 9.205 6.264 ;
     RECT  8.129 9.936 9.205 10.68 ;
     RECT  8.453 26.544 9.281 26.76 ;
     RECT  9.011 13.632 9.347 14.136 ;
     RECT  9.145 7.968 9.349 8.52 ;
     RECT  9.205 9.936 9.349 11.016 ;
     RECT  8.531 30.192 9.389 32.52 ;
     RECT  9.349 7.968 9.433 11.016 ;
     RECT  9.347 14.112 9.445 14.136 ;
     RECT  9.029 28.464 9.445 28.536 ;
     RECT  9.281 26.736 9.521 26.76 ;
     RECT  9.445 28.464 9.533 29.16 ;
     RECT  9.389 30.24 9.685 32.52 ;
     RECT  8.989 33.648 9.685 33.672 ;
     RECT  9.205 6.24 9.781 6.312 ;
     RECT  9.685 30.24 9.82 33.672 ;
     RECT  9.709 22.8 9.821 22.824 ;
     RECT  8.893 2.832 9.857 4.584 ;
     RECT  9.433 8.448 9.877 11.016 ;
     RECT  9.059 12.528 9.877 12.552 ;
     RECT  9.82 30.24 9.916 33.72 ;
     RECT  9.445 14.112 9.965 14.808 ;
     RECT  8.291 1.728 9.997 1.752 ;
     RECT  9.521 26.736 9.997 27.336 ;
     RECT  9.877 8.448 10.021 12.552 ;
     RECT  9.857 3.264 10.069 4.584 ;
     RECT  9.533 28.464 10.177 29.112 ;
     RECT  9.997 26.736 10.217 27.384 ;
     RECT  10.217 27.264 10.309 27.384 ;
     RECT  10.177 28.416 10.309 29.112 ;
     RECT  10.021 8.448 10.325 12.936 ;
     RECT  10.325 8.448 10.403 10.68 ;
     RECT  8.104 16.512 10.493 16.536 ;
     RECT  10.403 8.448 10.573 9.672 ;
     RECT  9.916 30.24 10.613 33.048 ;
     RECT  10.573 7.968 10.657 9.672 ;
     RECT  9.781 6.24 10.681 6.888 ;
     RECT  10.493 16.464 10.721 16.536 ;
     RECT  10.325 11.856 10.753 12.936 ;
     RECT  9.997 1.728 10.817 1.8 ;
     RECT  10.657 8.448 10.835 9.672 ;
     RECT  10.309 27.264 10.933 29.112 ;
     RECT  10.613 30.24 10.933 31.896 ;
     RECT  10.613 32.88 10.933 33.048 ;
     RECT  10.753 11.856 10.973 13.128 ;
     RECT  10.817 1.152 11.041 1.8 ;
     RECT  10.961 15.936 11.045 15.96 ;
     RECT  10.973 11.856 11.161 12.984 ;
     RECT  11.041 1.152 11.171 2.28 ;
     RECT  10.933 27.264 11.249 31.896 ;
     RECT  10.069 3.264 11.317 5.112 ;
     RECT  9.965 14.112 11.369 14.712 ;
     RECT  11.317 3.216 11.404 5.112 ;
     RECT  11.161 11.856 11.449 12.024 ;
     RECT  11.369 14.64 11.509 14.712 ;
     RECT  11.401 25.104 11.513 25.128 ;
     RECT  11.249 27.216 11.605 31.896 ;
     RECT  10.933 32.88 11.605 33.672 ;
     RECT  11.605 27.216 11.617 33.672 ;
     RECT  11.617 26.784 11.651 33.672 ;
     RECT  11.651 27.792 11.657 33.672 ;
     RECT  10.681 6.24 11.665 6.984 ;
     RECT  11.665 6.816 11.689 6.984 ;
     RECT  11.657 27.792 11.693 33.048 ;
     RECT  11.171 1.152 11.761 1.752 ;
     RECT  11.509 14.64 11.761 14.856 ;
     RECT  11.725 17.088 11.809 17.112 ;
     RECT  11.651 26.784 11.843 26.808 ;
     RECT  11.693 27.792 11.891 31.56 ;
     RECT  11.761 14.64 11.941 14.952 ;
     RECT  11.557 25.152 11.987 25.176 ;
     RECT  11.891 27.792 11.987 31.464 ;
     RECT  11.689 6.816 12.013 7.464 ;
     RECT  10.835 8.448 12.013 9.096 ;
     RECT  11.404 3.408 12.044 5.112 ;
     RECT  11.987 27.936 12.061 31.464 ;
     RECT  10.403 10.656 12.085 10.68 ;
     RECT  12.044 3.408 12.131 5.352 ;
     RECT  11.761 1.056 12.179 1.752 ;
     RECT  12.013 6.816 12.233 9.096 ;
     RECT  12.085 10.656 12.469 10.824 ;
     RECT  11.449 11.856 12.469 11.976 ;
     RECT  12.469 10.656 12.589 11.976 ;
     RECT  12.085 26.688 12.709 26.76 ;
     RECT  12.589 10.224 12.805 11.976 ;
     RECT  12.709 26.448 12.853 26.76 ;
     RECT  12.805 13.632 12.869 13.656 ;
     RECT  12.131 3.408 12.913 4.632 ;
     RECT  12.853 26.448 12.997 26.904 ;
     RECT  12.061 27.936 12.997 27.96 ;
     RECT  11.941 14.64 13.045 15.384 ;
     RECT  12.913 3.312 13.093 4.632 ;
     RECT  12.997 26.448 13.093 27.96 ;
     RECT  12.061 28.944 13.093 31.464 ;
     RECT  11.693 32.928 13.093 33.048 ;
     RECT  12.179 1.728 13.208 1.752 ;
     RECT  13.093 3.312 13.208 4.68 ;
     RECT  12.233 6.816 13.208 8.568 ;
     RECT  12.805 9.696 13.208 11.976 ;
     RECT  12.869 13.056 13.208 13.656 ;
     RECT  13.045 14.64 13.208 15.912 ;
     RECT  12.697 25.104 13.208 25.128 ;
     RECT  13.093 26.352 13.208 27.96 ;
     RECT  13.093 28.944 13.208 33.672 ;
     RECT  12.565 0.288 13.331 0.6 ;
     RECT  13.208 1.728 13.504 33.672 ;
     RECT  13.504 28.512 13.573 33.672 ;
     RECT  13.504 8.496 13.619 8.616 ;
     RECT  13.504 14.64 13.637 15.384 ;
     RECT  13.504 11.904 13.681 13.464 ;
     RECT  13.619 8.592 13.715 8.616 ;
     RECT  13.504 16.512 13.789 17.112 ;
     RECT  13.504 26.256 13.811 27.336 ;
     RECT  13.331 0.576 13.816 0.6 ;
     RECT  13.504 2.832 13.817 5.688 ;
     RECT  13.681 11.904 13.907 12.936 ;
     RECT  13.907 11.904 13.969 12.552 ;
     RECT  13.811 26.448 14.099 27.336 ;
     RECT  13.573 28.512 14.099 33.72 ;
     RECT  13.816 0.576 14.105 0.648 ;
     RECT  13.817 2.832 14.105 4.632 ;
     RECT  13.504 1.728 14.173 1.752 ;
     RECT  14.099 28.512 14.177 33.672 ;
     RECT  13.969 11.904 14.185 12.312 ;
     RECT  14.177 28.512 14.195 29.064 ;
     RECT  13.504 6.816 14.249 7.416 ;
     RECT  13.789 16.512 14.249 16.536 ;
     RECT  14.249 7.392 14.285 7.416 ;
     RECT  14.173 1.152 14.429 1.752 ;
     RECT  13.817 5.664 14.435 5.688 ;
     RECT  14.177 30.24 14.473 33.672 ;
     RECT  14.105 2.832 14.501 2.904 ;
     RECT  13.504 10.32 14.533 10.68 ;
     RECT  13.637 14.784 14.641 15.384 ;
     RECT  14.533 10.224 14.821 10.68 ;
     RECT  14.099 26.736 14.825 27.336 ;
     RECT  14.429 1.728 14.828 1.752 ;
     RECT  14.825 27.216 14.893 27.336 ;
     RECT  14.828 1.728 14.915 2.28 ;
     RECT  14.821 10.224 14.933 10.776 ;
     RECT  14.105 3.888 15.001 4.632 ;
     RECT  14.893 27.216 15.005 27.912 ;
     RECT  14.185 11.952 15.061 12.312 ;
     RECT  14.473 30.24 15.085 33.048 ;
     RECT  14.641 14.784 15.109 15.96 ;
     RECT  14.195 28.944 15.145 29.064 ;
     RECT  15.005 27.312 15.157 27.912 ;
     RECT  15.145 28.944 15.157 29.112 ;
     RECT  15.001 3.888 15.205 5.16 ;
     RECT  15.205 3.264 15.251 5.16 ;
     RECT  15.157 27.312 15.251 29.112 ;
     RECT  14.933 10.224 15.253 10.68 ;
     RECT  15.061 11.952 15.253 12.552 ;
     RECT  15.109 14.112 15.292 15.96 ;
     RECT  15.292 15.312 15.349 15.96 ;
     RECT  15.301 17.088 15.349 17.112 ;
     RECT  15.253 11.904 15.361 12.552 ;
     RECT  15.251 3.264 15.395 4.824 ;
     RECT  15.085 30.24 15.469 32.472 ;
     RECT  14.915 1.728 15.491 1.752 ;
     RECT  15.361 0.528 15.635 0.552 ;
     RECT  15.253 9.696 15.649 10.68 ;
     RECT  14.677 8.544 15.685 8.568 ;
     RECT  15.649 9.6 15.797 10.68 ;
     RECT  15.349 15.312 15.905 17.112 ;
     RECT  15.685 7.968 15.973 8.568 ;
     RECT  15.973 7.44 16.021 8.568 ;
     RECT  15.469 30.192 16.021 32.472 ;
     RECT  16.021 7.248 16.069 8.568 ;
     RECT  15.395 3.264 16.076 4.632 ;
     RECT  16.021 29.664 16.117 32.472 ;
     RECT  15.649 33.648 16.117 33.672 ;
     RECT  15.251 27.312 16.153 28.584 ;
     RECT  16.076 2.88 16.163 4.632 ;
     RECT  16.163 3.312 16.193 4.632 ;
     RECT  15.797 9.984 16.211 10.68 ;
     RECT  16.153 27.264 16.225 28.584 ;
     RECT  16.117 29.664 16.225 33.672 ;
     RECT  16.193 3.408 16.229 4.632 ;
     RECT  16.225 27.264 16.265 33.672 ;
     RECT  16.22 5.664 16.307 5.688 ;
     RECT  16.265 27.264 16.309 33.096 ;
     RECT  15.905 15.936 16.409 17.112 ;
     RECT  16.309 26.688 16.453 33.096 ;
     RECT  16.453 26.592 16.501 33.096 ;
     RECT  16.229 3.408 16.517 4.584 ;
     RECT  16.153 0.576 16.621 0.6 ;
     RECT  16.621 0.48 16.669 0.6 ;
     RECT  16.211 10.224 16.693 10.68 ;
     RECT  15.361 11.904 16.693 13.08 ;
     RECT  16.669 0.48 16.787 0.504 ;
     RECT  16.069 6.672 16.837 8.568 ;
     RECT  16.693 10.224 16.877 13.08 ;
     RECT  16.409 17.088 16.877 17.112 ;
     RECT  16.837 6.672 17.365 9.096 ;
     RECT  16.877 10.368 17.365 13.08 ;
     RECT  15.292 14.112 17.365 14.136 ;
     RECT  16.501 26.448 17.377 33.096 ;
     RECT  17.365 6.288 17.413 9.096 ;
     RECT  17.377 26.448 17.509 33.672 ;
     RECT  16.517 3.744 17.521 4.584 ;
     RECT  17.413 6.288 17.525 9.144 ;
     RECT  17.509 26.16 17.561 33.672 ;
     RECT  17.525 6.288 17.597 9.096 ;
     RECT  17.521 3.744 17.665 5.16 ;
     RECT  17.365 2.736 17.737 2.76 ;
     RECT  17.665 3.744 17.737 5.208 ;
     RECT  17.365 10.368 17.797 14.136 ;
     RECT  17.561 28.896 18.037 33.672 ;
     RECT  18.037 28.896 18.085 33.768 ;
     RECT  18.085 28.896 18.101 33.864 ;
     RECT  18.101 33.648 18.227 33.864 ;
     RECT  17.989 0.288 18.388 0.312 ;
     RECT  17.561 26.16 18.565 27.912 ;
     RECT  18.101 28.896 18.565 32.568 ;
     RECT  17.729 1.728 18.608 1.752 ;
     RECT  17.737 2.736 18.608 5.208 ;
     RECT  17.597 6.768 18.608 9.096 ;
     RECT  17.797 10.368 18.608 14.808 ;
     RECT  17.845 16.128 18.608 16.152 ;
     RECT  18.421 22.8 18.608 22.824 ;
     RECT  18.565 26.16 18.608 32.568 ;
     RECT  18.608 1.728 18.659 32.568 ;
     RECT  18.659 1.728 18.904 32.52 ;
     RECT  18.388 0.288 19.045 0.36 ;
     RECT  18.904 6.384 19.109 6.888 ;
     RECT  18.904 13.056 19.117 14.856 ;
     RECT  19.117 13.056 19.139 14.472 ;
     RECT  18.904 2.832 19.153 4.68 ;
     RECT  19.045 0.288 19.187 0.408 ;
     RECT  18.227 33.648 19.285 33.672 ;
     RECT  18.904 1.728 19.379 1.8 ;
     RECT  19.285 33.648 19.426 33.72 ;
     RECT  19.426 33.648 19.477 33.768 ;
     RECT  19.477 33.648 19.619 33.816 ;
     RECT  18.904 15.936 19.715 16.008 ;
     RECT  18.904 26.784 19.724 32.52 ;
     RECT  19.619 33.648 19.724 33.768 ;
     RECT  19.724 26.784 19.763 33.768 ;
     RECT  19.139 13.056 19.793 13.416 ;
     RECT  19.715 15.936 19.865 15.96 ;
     RECT  19.109 6.384 19.897 6.408 ;
     RECT  19.793 13.056 19.945 13.08 ;
     RECT  19.187 0.288 19.955 0.312 ;
     RECT  18.904 7.92 19.955 8.568 ;
     RECT  19.153 3.936 19.957 4.68 ;
     RECT  19.897 5.664 19.957 6.408 ;
     RECT  19.763 26.784 19.97 33.72 ;
     RECT  19.153 2.832 19.981 2.856 ;
     RECT  19.97 29.52 20.009 33.72 ;
     RECT  18.904 9.744 20.117 11.4 ;
     RECT  19.957 3.936 20.153 6.408 ;
     RECT  19.955 7.92 20.204 7.992 ;
     RECT  20.009 29.664 20.243 33.72 ;
     RECT  20.153 3.936 20.285 4.632 ;
     RECT  20.204 7.392 20.291 7.992 ;
     RECT  20.153 5.664 20.293 6.408 ;
     RECT  20.243 33.072 20.339 33.72 ;
     RECT  20.293 9.072 20.377 9.096 ;
     RECT  20.285 3.84 20.387 4.632 ;
     RECT  20.117 10.368 20.401 11.4 ;
     RECT  19.139 14.448 20.573 14.472 ;
     RECT  20.293 5.664 20.579 6.84 ;
     RECT  19.97 26.784 20.579 28.536 ;
     RECT  20.573 14.208 20.833 14.472 ;
     RECT  20.387 3.84 20.869 4.584 ;
     RECT  20.833 13.44 20.933 14.472 ;
     RECT  20.869 17.088 20.953 17.112 ;
     RECT  20.933 13.44 21.017 15.384 ;
     RECT  20.579 26.784 21.049 27.384 ;
     RECT  20.869 3.744 21.149 4.584 ;
     RECT  20.579 6.24 21.301 6.84 ;
     RECT  20.291 7.92 21.301 7.992 ;
     RECT  21.017 13.44 21.341 14.856 ;
     RECT  21.013 0.288 21.347 0.312 ;
     RECT  20.579 28.464 21.397 28.536 ;
     RECT  20.243 29.664 21.397 31.992 ;
     RECT  21.397 28.464 21.436 31.992 ;
     RECT  21.301 6.24 21.485 7.992 ;
     RECT  21.341 13.44 21.517 13.848 ;
     RECT  19.379 1.728 21.565 1.752 ;
     RECT  21.445 16.992 21.593 17.016 ;
     RECT  20.401 10.368 21.665 11.832 ;
     RECT  21.589 15.936 21.673 15.96 ;
     RECT  21.436 28.464 21.731 31.944 ;
     RECT  21.665 10.368 21.733 11.4 ;
     RECT  21.485 6.24 21.745 6.84 ;
     RECT  21.733 9.648 21.769 11.4 ;
     RECT  21.769 9.072 21.805 11.4 ;
     RECT  21.805 8.688 21.817 11.4 ;
     RECT  20.339 33.072 21.874 33.672 ;
     RECT  21.149 2.832 21.875 4.584 ;
     RECT  21.341 14.832 21.875 14.856 ;
     RECT  21.805 5.664 21.923 5.688 ;
     RECT  21.731 28.464 21.925 28.776 ;
     RECT  21.049 26.736 21.973 27.384 ;
     RECT  21.925 28.464 21.973 28.536 ;
     RECT  21.973 26.736 22.021 28.536 ;
     RECT  21.817 10.224 22.133 11.4 ;
     RECT  21.875 3.12 22.201 4.584 ;
     RECT  21.874 33.072 22.241 33.72 ;
     RECT  22.193 0.576 22.277 0.6 ;
     RECT  22.201 3.12 22.403 5.16 ;
     RECT  21.745 6.816 22.489 6.84 ;
     RECT  22.381 0.192 22.547 0.216 ;
     RECT  21.731 30.096 22.633 31.944 ;
     RECT  22.489 6.816 22.643 7.512 ;
     RECT  22.633 30.096 22.717 31.992 ;
     RECT  22.643 6.816 22.739 7.464 ;
     RECT  21.517 12.864 22.741 13.848 ;
     RECT  22.021 26.448 22.789 28.536 ;
     RECT  21.817 8.688 22.813 9.096 ;
     RECT  22.717 30.096 22.817 31.944 ;
     RECT  22.133 10.272 22.825 11.4 ;
     RECT  22.739 6.816 22.925 7.416 ;
     RECT  22.241 33.648 22.933 33.72 ;
     RECT  22.825 10.848 22.981 11.4 ;
     RECT  22.789 26.4 22.981 28.536 ;
     RECT  22.933 33.648 23.069 33.768 ;
     RECT  22.741 12.528 23.209 13.848 ;
     RECT  23.069 33.648 23.363 33.672 ;
     RECT  22.981 26.4 23.389 29.064 ;
     RECT  22.817 30.096 23.389 31.8 ;
     RECT  22.633 1.728 23.461 1.752 ;
     RECT  22.403 3.12 23.461 4.584 ;
     RECT  22.981 10.848 23.533 11.448 ;
     RECT  23.209 12.528 23.533 14.808 ;
     RECT  23.165 16.512 23.605 16.536 ;
     RECT  22.813 8.688 23.701 9.144 ;
     RECT  23.533 10.848 23.713 14.808 ;
     RECT  23.42 5.664 23.749 5.688 ;
     RECT  22.925 7.392 23.885 7.416 ;
     RECT  23.701 8.496 23.885 9.144 ;
     RECT  23.885 7.392 23.893 9.144 ;
     RECT  23.461 1.728 24.008 4.584 ;
     RECT  23.749 5.664 24.008 6.12 ;
     RECT  23.893 7.248 24.008 9.144 ;
     RECT  23.713 10.848 24.008 14.856 ;
     RECT  23.605 15.84 24.008 16.536 ;
     RECT  23.413 17.616 24.008 17.64 ;
     RECT  23.389 26.4 24.008 31.8 ;
     RECT  23.509 33.072 24.008 33.096 ;
     RECT  23.641 0.528 24.085 0.552 ;
     RECT  24.008 1.728 24.304 33.096 ;
     RECT  24.085 0.288 24.467 0.552 ;
     RECT  24.304 2.88 24.467 4.68 ;
     RECT  24.304 6.096 24.467 9.192 ;
     RECT  24.304 15.84 24.467 16.008 ;
     RECT  24.467 15.84 24.473 15.912 ;
     RECT  24.304 26.208 24.473 33.096 ;
     RECT  24.467 0.384 24.476 0.552 ;
     RECT  24.304 1.728 24.476 1.752 ;
     RECT  24.304 14.112 24.481 14.808 ;
     RECT  24.476 0.384 24.515 1.752 ;
     RECT  24.467 7.392 24.545 9.192 ;
     RECT  24.515 1.104 24.563 1.752 ;
     RECT  24.473 26.64 24.565 33.096 ;
     RECT  24.565 26.64 24.653 33.672 ;
     RECT  24.304 10.224 24.661 10.968 ;
     RECT  24.545 7.968 24.725 9.192 ;
     RECT  24.725 8.688 24.841 9.192 ;
     RECT  24.467 6.096 25.043 6.264 ;
     RECT  24.467 2.88 25.049 4.584 ;
     RECT  25.043 6.096 25.049 6.12 ;
     RECT  24.653 26.64 25.121 33.096 ;
     RECT  25.049 3.36 25.337 4.584 ;
     RECT  24.661 10.272 25.477 10.968 ;
     RECT  24.304 11.952 25.477 13.08 ;
     RECT  25.121 26.64 25.625 31.992 ;
     RECT  25.625 26.64 25.661 31.944 ;
     RECT  24.481 14.4 25.717 14.808 ;
     RECT  24.473 15.888 25.717 15.912 ;
     RECT  25.657 0.576 25.741 0.6 ;
     RECT  25.477 10.272 25.765 13.08 ;
     RECT  25.765 10.272 25.829 13.128 ;
     RECT  25.717 14.4 25.829 15.912 ;
     RECT  25.861 16.992 25.909 17.016 ;
     RECT  25.829 10.272 25.913 15.912 ;
     RECT  25.121 33.072 25.949 33.096 ;
     RECT  25.913 10.272 25.957 13.032 ;
     RECT  25.337 3.408 25.981 4.584 ;
     RECT  25.909 16.992 25.993 17.64 ;
     RECT  24.841 8.688 26.081 9.096 ;
     RECT  25.981 3.408 26.147 4.632 ;
     RECT  25.913 14.256 26.149 15.912 ;
     RECT  26.081 7.968 26.165 9.096 ;
     RECT  26.149 14.256 26.195 16.008 ;
     RECT  26.147 3.408 26.201 4.584 ;
     RECT  26.195 14.256 26.237 14.808 ;
     RECT  24.563 1.728 26.305 1.752 ;
     RECT  26.017 6.384 26.449 6.408 ;
     RECT  26.201 3.936 26.483 4.584 ;
     RECT  26.449 6.24 26.533 6.408 ;
     RECT  26.533 6.384 26.549 6.408 ;
     RECT  26.195 15.984 26.597 16.008 ;
     RECT  26.305 1.728 26.657 1.8 ;
     RECT  25.993 16.992 26.669 17.016 ;
     RECT  25.661 26.784 26.677 31.944 ;
     RECT  25.957 10.224 26.705 13.032 ;
     RECT  26.657 1.728 26.741 1.848 ;
     RECT  26.677 26.784 26.777 32.376 ;
     RECT  26.809 2.88 26.893 2.904 ;
     RECT  26.237 14.688 27.197 14.808 ;
     RECT  27.197 14.688 27.205 14.856 ;
     RECT  26.705 10.272 27.251 13.032 ;
     RECT  26.165 8.448 27.313 9.096 ;
     RECT  26.549 6.384 27.349 6.84 ;
     RECT  27.251 10.272 27.353 12.552 ;
     RECT  27.353 10.848 27.395 12.552 ;
     RECT  27.205 14.688 27.425 14.952 ;
     RECT  26.161 33.648 27.541 33.72 ;
     RECT  26.777 26.784 27.587 32.04 ;
     RECT  27.587 29.808 27.781 32.04 ;
     RECT  27.541 33.072 27.781 33.72 ;
     RECT  27.781 16.512 27.809 16.536 ;
     RECT  27.349 6.384 27.821 7.416 ;
     RECT  27.395 12.192 27.821 12.552 ;
     RECT  27.809 15.936 27.893 16.536 ;
     RECT  26.483 3.984 27.925 4.584 ;
     RECT  27.313 8.448 27.925 9.288 ;
     RECT  27.587 26.784 27.925 28.776 ;
     RECT  27.781 29.808 27.925 33.72 ;
     RECT  27.925 3.408 27.961 4.584 ;
     RECT  27.961 3.408 28.033 5.112 ;
     RECT  27.925 29.808 28.067 33.768 ;
     RECT  27.821 6.384 28.069 6.408 ;
     RECT  28.069 13.632 28.163 13.656 ;
     RECT  27.925 26.208 28.181 28.776 ;
     RECT  27.925 7.968 28.211 9.288 ;
     RECT  27.821 12.528 28.213 12.552 ;
     RECT  28.181 26.64 28.307 28.776 ;
     RECT  28.213 12.528 28.321 12.6 ;
     RECT  28.033 2.832 28.357 5.112 ;
     RECT  26.741 1.728 28.549 1.752 ;
     RECT  27.425 14.688 28.573 14.712 ;
     RECT  28.549 1.152 28.721 1.752 ;
     RECT  28.067 29.808 28.739 33.672 ;
     RECT  28.307 28.368 28.741 28.776 ;
     RECT  28.739 29.808 28.741 32.664 ;
     RECT  28.211 9.072 28.789 9.288 ;
     RECT  27.395 10.848 28.789 10.872 ;
     RECT  28.069 6.24 29.041 6.408 ;
     RECT  28.721 1.728 29.077 1.752 ;
     RECT  28.357 2.832 29.077 5.16 ;
     RECT  28.789 9.072 29.077 10.872 ;
     RECT  28.321 12.528 29.077 12.648 ;
     RECT  28.739 33.648 29.117 33.672 ;
     RECT  29.077 1.728 29.197 5.16 ;
     RECT  29.041 6.24 29.221 6.6 ;
     RECT  29.197 2.016 29.408 5.16 ;
     RECT  29.221 6.24 29.408 6.84 ;
     RECT  28.981 7.92 29.408 7.944 ;
     RECT  29.077 9.072 29.408 12.648 ;
     RECT  28.573 14.688 29.408 15.24 ;
     RECT  27.893 16.512 29.408 16.536 ;
     RECT  28.307 26.64 29.408 27.336 ;
     RECT  28.741 28.368 29.408 32.664 ;
     RECT  29.408 2.016 29.704 32.664 ;
     RECT  29.704 7.92 29.873 9.816 ;
     RECT  29.704 10.848 29.891 16.008 ;
     RECT  29.704 2.016 29.909 4.776 ;
     RECT  29.173 0.288 29.987 0.312 ;
     RECT  29.704 6.576 30.125 6.888 ;
     RECT  29.704 26.784 30.197 32.664 ;
     RECT  29.909 2.016 30.257 4.104 ;
     RECT  30.125 6.768 30.275 6.888 ;
     RECT  30.229 33.072 30.277 33.096 ;
     RECT  29.873 7.968 30.449 9.816 ;
     RECT  29.891 10.848 30.565 15.816 ;
     RECT  30.257 1.728 30.611 4.104 ;
     RECT  30.277 33.072 30.613 33.672 ;
     RECT  30.611 1.728 30.755 1.752 ;
     RECT  30.611 2.736 30.755 4.104 ;
     RECT  30.449 9.648 30.809 9.816 ;
     RECT  30.565 12.528 30.949 15.816 ;
     RECT  30.755 3.984 30.985 4.104 ;
     RECT  30.613 33.072 30.997 33.72 ;
     RECT  30.197 26.784 31.013 31.944 ;
     RECT  30.949 12.528 31.033 15.96 ;
     RECT  31.013 26.736 31.097 31.944 ;
     RECT  30.997 33.072 31.241 33.768 ;
     RECT  31.097 26.784 31.244 31.944 ;
     RECT  31.241 33.072 31.244 33.72 ;
     RECT  30.275 6.768 31.309 6.84 ;
     RECT  31.244 26.784 31.331 33.72 ;
     RECT  31.309 6.288 31.333 6.84 ;
     RECT  30.449 7.968 31.333 8.472 ;
     RECT  31.331 33.072 31.379 33.72 ;
     RECT  30.755 2.736 31.385 2.76 ;
     RECT  31.165 16.512 31.465 16.536 ;
     RECT  31.345 0.192 31.475 0.216 ;
     RECT  31.333 6.288 31.493 8.472 ;
     RECT  31.493 6.288 31.601 7.224 ;
     RECT  31.493 8.448 31.673 8.472 ;
     RECT  30.985 3.984 31.705 4.584 ;
     RECT  30.809 9.648 31.777 9.768 ;
     RECT  31.705 3.984 31.805 5.16 ;
     RECT  31.805 3.984 31.813 5.256 ;
     RECT  31.813 3.84 31.817 5.256 ;
     RECT  31.817 3.84 31.861 4.008 ;
     RECT  31.817 5.136 31.889 5.256 ;
     RECT  31.669 0.288 31.907 0.312 ;
     RECT  31.889 5.136 31.907 5.16 ;
     RECT  31.777 9.024 31.925 9.768 ;
     RECT  31.033 12.528 31.957 15.096 ;
     RECT  30.565 10.848 32.053 11.256 ;
     RECT  31.925 9.024 32.149 9.096 ;
     RECT  32.053 10.848 32.353 11.352 ;
     RECT  31.957 12.48 32.353 15.096 ;
     RECT  32.353 10.848 32.389 15.096 ;
     RECT  31.379 33.072 32.429 33.672 ;
     RECT  32.137 1.728 32.437 1.752 ;
     RECT  32.389 10.8 32.437 15.096 ;
     RECT  32.437 1.728 32.54 1.8 ;
     RECT  31.601 7.2 32.725 7.224 ;
     RECT  32.725 7.2 32.749 7.8 ;
     RECT  32.749 7.2 32.773 7.992 ;
     RECT  32.54 1.728 32.785 2.28 ;
     RECT  31.861 3.312 32.785 4.008 ;
     RECT  32.437 10.8 32.789 11.448 ;
     RECT  32.785 1.728 32.849 4.008 ;
     RECT  32.849 1.728 32.929 4.584 ;
     RECT  32.789 10.992 33.041 11.448 ;
     RECT  32.429 33.072 33.041 33.192 ;
     RECT  32.929 1.728 33.059 4.68 ;
     RECT  31.331 26.784 33.059 31.944 ;
     RECT  33.059 1.728 33.077 4.632 ;
     RECT  33.059 27.36 33.1 31.944 ;
     RECT  32.437 12.528 33.101 15.096 ;
     RECT  33.1 29.616 33.109 31.944 ;
     RECT  32.149 9.072 33.149 9.096 ;
     RECT  33.101 12.528 33.325 15.384 ;
     RECT  32.993 16.512 33.325 16.536 ;
     RECT  33.325 12.528 33.365 16.536 ;
     RECT  33.365 12.528 33.395 15.96 ;
     RECT  33.395 13.104 33.409 15.96 ;
     RECT  33.409 13.104 33.437 15.096 ;
     RECT  33.1 27.36 33.443 28.536 ;
     RECT  32.773 6.816 33.473 7.992 ;
     RECT  33.473 6.816 33.493 6.84 ;
     RECT  33.077 2.736 33.494 4.632 ;
     RECT  33.041 11.232 33.539 11.448 ;
     RECT  33.437 13.104 33.625 14.856 ;
     RECT  33.397 0.288 33.635 0.312 ;
     RECT  33.493 6.72 33.635 6.84 ;
     RECT  33.625 13.104 33.635 14.28 ;
     RECT  33.494 2.736 33.689 4.584 ;
     RECT  33.541 8.496 33.833 8.616 ;
     RECT  33.109 29.616 34.117 32.472 ;
     RECT  33.443 27.792 34.165 28.536 ;
     RECT  34.117 29.52 34.165 32.472 ;
     RECT  33.833 8.592 34.441 8.616 ;
     RECT  33.077 1.728 34.453 1.752 ;
     RECT  34.165 27.792 34.453 32.472 ;
     RECT  33.689 3.408 34.585 4.584 ;
     RECT  34.549 5.712 34.585 5.736 ;
     RECT  34.453 27.792 34.625 33.096 ;
     RECT  33.539 11.232 34.645 11.256 ;
     RECT  34.453 1.728 34.808 2.04 ;
     RECT  34.585 3.408 34.808 5.736 ;
     RECT  33.635 6.816 34.808 6.84 ;
     RECT  34.441 8.592 34.808 9.096 ;
     RECT  34.645 11.232 34.808 11.4 ;
     RECT  33.635 13.104 34.808 13.944 ;
     RECT  34.625 27.792 34.808 33.048 ;
     RECT  34.808 1.728 35.104 33.048 ;
     RECT  35.104 1.728 35.219 3.432 ;
     RECT  35.104 12.528 35.219 14.808 ;
     RECT  35.104 4.416 35.237 4.68 ;
     RECT  34.885 0.288 35.267 0.312 ;
     RECT  35.237 4.56 35.267 4.68 ;
     RECT  35.104 10.224 35.315 10.248 ;
     RECT  35.104 29.088 35.315 30.408 ;
     RECT  35.104 31.392 35.315 33.048 ;
     RECT  35.219 3.408 35.353 3.432 ;
     RECT  35.104 6.24 35.363 6.264 ;
     RECT  35.315 31.392 35.363 32.472 ;
     RECT  35.267 4.56 35.489 4.584 ;
     RECT  35.315 29.76 35.597 30.408 ;
     RECT  35.219 13.92 35.633 14.808 ;
     RECT  35.363 31.92 35.633 32.472 ;
     RECT  35.219 1.728 35.651 2.28 ;
     RECT  35.651 1.728 35.849 1.752 ;
     RECT  35.633 13.92 35.939 13.944 ;
     RECT  35.597 30.384 35.939 30.408 ;
     RECT  35.219 12.528 36.317 12.552 ;
     RECT  35.633 31.92 36.569 32.424 ;
     RECT  36.569 31.968 36.965 32.424 ;
     RECT  36.965 32.4 37.325 32.424 ;
     RECT  40.208 2.148 40.312 32.412 ;
     RECT  40.312 2.418 40.504 32.142 ;
    LAYER M5 ;
     RECT  6.528 0.144 35.784 0.611 ;
     RECT  6.672 0.611 35.784 1.763 ;
     RECT  2.4 2.137 2.52 2.151 ;
     RECT  40.2 2.137 40.32 2.151 ;
     RECT  6.816 1.763 35.64 2.243 ;
     RECT  6.96 2.243 35.64 2.291 ;
     RECT  6.96 2.291 35.352 4.019 ;
     RECT  7.68 4.019 35.352 4.595 ;
     RECT  27.936 4.595 35.304 5.267 ;
     RECT  7.8 4.595 26.472 5.699 ;
     RECT  15.264 5.699 26.472 6.229 ;
     RECT  32.448 5.267 35.304 6.229 ;
     RECT  15.264 6.229 26.52 6.373 ;
     RECT  27.936 5.267 31.128 6.373 ;
     RECT  7.8 5.699 14.04 6.805 ;
     RECT  15.264 6.373 31.128 6.805 ;
     RECT  32.448 6.229 35.352 6.851 ;
     RECT  15.264 6.805 31.368 7.619 ;
     RECT  7.8 6.805 14.232 8.485 ;
     RECT  32.448 6.851 33.624 8.485 ;
     RECT  34.656 6.851 35.352 8.485 ;
     RECT  15.264 7.619 31.128 8.579 ;
     RECT  20.304 8.579 31.128 9.013 ;
     RECT  32.448 8.485 35.352 9.013 ;
     RECT  20.304 9.013 35.352 9.107 ;
     RECT  20.304 9.107 33.816 9.203 ;
     RECT  15.264 8.579 19.176 9.731 ;
     RECT  15.6 9.731 19.176 10.021 ;
     RECT  20.304 9.203 24.408 10.021 ;
     RECT  6.912 8.485 14.232 10.213 ;
     RECT  15.6 10.021 24.408 10.213 ;
     RECT  25.44 9.203 33.816 10.213 ;
     RECT  15.6 10.213 33.816 11.365 ;
     RECT  34.8 9.107 35.352 11.365 ;
     RECT  6.912 10.213 14.568 11.893 ;
     RECT  15.6 11.365 35.352 11.893 ;
     RECT  6.912 11.893 35.352 13.139 ;
     RECT  33.552 13.139 35.352 13.909 ;
     RECT  6.912 13.139 32.472 14.773 ;
     RECT  33.552 13.909 35.928 14.773 ;
     RECT  0.24 10.645 0.264 15.923 ;
     RECT  6.912 14.773 35.928 29.699 ;
     RECT  7.392 29.699 35.928 30.419 ;
     RECT  7.392 30.419 35.352 31.813 ;
     RECT  6.528 31.813 35.352 31.957 ;
     RECT  6.528 31.957 35.496 32.005 ;
     RECT  6.528 32.005 35.64 32.389 ;
     RECT  2.4 2.151 2.712 32.409 ;
     RECT  40.2 2.151 40.512 32.409 ;
     RECT  2.4 32.409 2.52 32.423 ;
     RECT  40.2 32.409 40.32 32.423 ;
     RECT  6.528 32.389 35.784 34.384 ;
     RECT  26.472 4.595 27.936 6.229 ;
     RECT  31.128 5.267 32.448 6.805 ;
     RECT  14.04 5.699 15.264 6.805 ;
     RECT  26.52 6.229 27.936 6.373 ;
     RECT  14.232 6.805 15.264 9.731 ;
     RECT  31.368 6.805 32.448 7.619 ;
     RECT  33.624 6.851 34.656 8.485 ;
     RECT  31.128 7.619 32.448 9.013 ;
     RECT  19.176 8.579 20.304 10.021 ;
     RECT  33.816 9.107 34.8 11.365 ;
     RECT  24.408 9.203 25.44 10.213 ;
     RECT  14.232 9.731 15.6 10.213 ;
     RECT  14.568 10.213 15.6 11.893 ;
     RECT  32.472 13.139 33.552 14.773 ;
  END
END ot_s81_pq_bc_slice1
END LIBRARY
